VERSION 5.7 ;
  NOWIREEXTENSIONATPIN ON ;
  DIVIDERCHAR "/" ;
  BUSBITCHARS "[]" ;
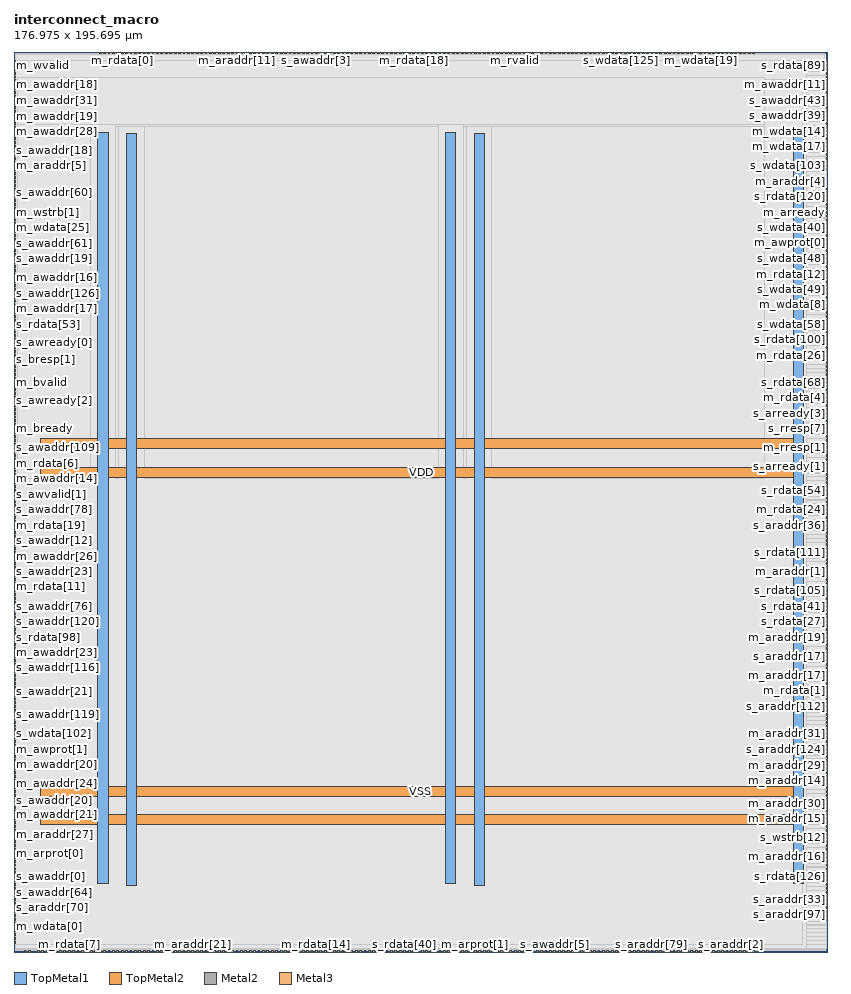
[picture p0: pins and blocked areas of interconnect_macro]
MACRO interconnect_macro
  CLASS BLOCK ;
  FOREIGN interconnect_macro ;
  ORIGIN 0.000 0.000 ;
  SIZE 176.975 BY 195.695 ;
  PIN VDD
    DIRECTION INOUT ;
    USE POWER ;
    PORT
      LAYER TopMetal1 ;
        RECT 18.260 14.900 20.460 178.290 ;
    END
    PORT
      LAYER TopMetal1 ;
        RECT 93.860 14.900 96.060 178.290 ;
    END
    PORT
      LAYER TopMetal1 ;
        RECT 169.460 14.900 171.660 178.290 ;
    END
    PORT
      LAYER TopMetal2 ;
        RECT 5.760 27.620 171.660 29.820 ;
    END
    PORT
      LAYER TopMetal2 ;
        RECT 5.760 103.220 171.660 105.420 ;
    END
  END VDD
  PIN VSS
    DIRECTION INOUT ;
    USE GROUND ;
    PORT
      LAYER TopMetal1 ;
        RECT 24.460 14.490 26.660 177.880 ;
    END
    PORT
      LAYER TopMetal1 ;
        RECT 100.060 14.490 102.260 177.880 ;
    END
    PORT
      LAYER TopMetal2 ;
        RECT 5.760 33.820 170.880 36.020 ;
    END
    PORT
      LAYER TopMetal2 ;
        RECT 5.760 109.420 170.880 111.620 ;
    END
  END VSS
  PIN clk_i
    DIRECTION INPUT ;
    USE SIGNAL ;
    PORT
      LAYER Metal2 ;
        RECT 2.200 0.000 2.600 0.400 ;
    END
  END clk_i
  PIN m_araddr[0]
    DIRECTION INPUT ;
    USE SIGNAL ;
    ANTENNAGATEAREA 0.109200 ;
    PORT
      LAYER Metal2 ;
        RECT 5.080 0.000 5.480 0.400 ;
    END
  END m_araddr[0]
  PIN m_araddr[10]
    DIRECTION INPUT ;
    USE SIGNAL ;
    ANTENNAGATEAREA 0.109200 ;
    PORT
      LAYER Metal2 ;
        RECT 18.520 195.295 18.920 195.695 ;
    END
  END m_araddr[10]
  PIN m_araddr[11]
    DIRECTION INPUT ;
    USE SIGNAL ;
    ANTENNAGATEAREA 0.109200 ;
    PORT
      LAYER Metal2 ;
        RECT 48.280 195.295 48.680 195.695 ;
    END
  END m_araddr[11]
  PIN m_araddr[12]
    DIRECTION INPUT ;
    USE SIGNAL ;
    ANTENNAGATEAREA 0.180700 ;
    PORT
      LAYER Metal3 ;
        RECT 176.575 6.940 176.975 7.340 ;
    END
  END m_araddr[12]
  PIN m_araddr[13]
    DIRECTION INPUT ;
    USE SIGNAL ;
    ANTENNAGATEAREA 0.180700 ;
    PORT
      LAYER Metal3 ;
        RECT 176.575 12.820 176.975 13.220 ;
    END
  END m_araddr[13]
  PIN m_araddr[14]
    DIRECTION INPUT ;
    USE SIGNAL ;
    ANTENNAGATEAREA 0.180700 ;
    PORT
      LAYER Metal3 ;
        RECT 176.575 37.180 176.975 37.580 ;
    END
  END m_araddr[14]
  PIN m_araddr[15]
    DIRECTION INPUT ;
    USE SIGNAL ;
    ANTENNAGATEAREA 0.180700 ;
    PORT
      LAYER Metal3 ;
        RECT 176.575 28.780 176.975 29.180 ;
    END
  END m_araddr[15]
  PIN m_araddr[16]
    DIRECTION INPUT ;
    USE SIGNAL ;
    ANTENNAGATEAREA 0.180700 ;
    PORT
      LAYER Metal3 ;
        RECT 176.575 22.060 176.975 22.460 ;
    END
  END m_araddr[16]
  PIN m_araddr[17]
    DIRECTION INPUT ;
    USE SIGNAL ;
    ANTENNAGATEAREA 0.180700 ;
    PORT
      LAYER Metal3 ;
        RECT 176.575 61.540 176.975 61.940 ;
    END
  END m_araddr[17]
  PIN m_araddr[18]
    DIRECTION INPUT ;
    USE SIGNAL ;
    ANTENNAGATEAREA 0.180700 ;
    PORT
      LAYER Metal3 ;
        RECT 176.575 18.700 176.975 19.100 ;
    END
  END m_araddr[18]
  PIN m_araddr[19]
    DIRECTION INPUT ;
    USE SIGNAL ;
    ANTENNAGATEAREA 0.180700 ;
    PORT
      LAYER Metal3 ;
        RECT 176.575 68.260 176.975 68.660 ;
    END
  END m_araddr[19]
  PIN m_araddr[1]
    DIRECTION INPUT ;
    USE SIGNAL ;
    ANTENNAGATEAREA 0.109200 ;
    PORT
      LAYER Metal3 ;
        RECT 176.575 82.540 176.975 82.940 ;
    END
  END m_araddr[1]
  PIN m_araddr[20]
    DIRECTION INPUT ;
    USE SIGNAL ;
    ANTENNAGATEAREA 0.180700 ;
    PORT
      LAYER Metal2 ;
        RECT 61.720 0.000 62.120 0.400 ;
    END
  END m_araddr[20]
  PIN m_araddr[21]
    DIRECTION INPUT ;
    USE SIGNAL ;
    ANTENNAGATEAREA 0.180700 ;
    PORT
      LAYER Metal2 ;
        RECT 38.680 0.000 39.080 0.400 ;
    END
  END m_araddr[21]
  PIN m_araddr[22]
    DIRECTION INPUT ;
    USE SIGNAL ;
    ANTENNAGATEAREA 0.180700 ;
    PORT
      LAYER Metal2 ;
        RECT 63.640 0.000 64.040 0.400 ;
    END
  END m_araddr[22]
  PIN m_araddr[23]
    DIRECTION INPUT ;
    USE SIGNAL ;
    ANTENNAGATEAREA 0.180700 ;
    PORT
      LAYER Metal2 ;
        RECT 36.760 0.000 37.160 0.400 ;
    END
  END m_araddr[23]
  PIN m_araddr[24]
    DIRECTION INPUT ;
    USE SIGNAL ;
    ANTENNAGATEAREA 0.180700 ;
    PORT
      LAYER Metal2 ;
        RECT 40.600 0.000 41.000 0.400 ;
    END
  END m_araddr[24]
  PIN m_araddr[25]
    DIRECTION INPUT ;
    USE SIGNAL ;
    ANTENNAGATEAREA 0.180700 ;
    PORT
      LAYER Metal2 ;
        RECT 49.240 0.000 49.640 0.400 ;
    END
  END m_araddr[25]
  PIN m_araddr[26]
    DIRECTION INPUT ;
    USE SIGNAL ;
    ANTENNAGATEAREA 0.180700 ;
    PORT
      LAYER Metal2 ;
        RECT 52.120 0.000 52.520 0.400 ;
    END
  END m_araddr[26]
  PIN m_araddr[27]
    DIRECTION INPUT ;
    USE SIGNAL ;
    ANTENNAGATEAREA 0.180700 ;
    PORT
      LAYER Metal3 ;
        RECT 0.000 25.420 0.400 25.820 ;
    END
  END m_araddr[27]
  PIN m_araddr[28]
    DIRECTION INPUT ;
    USE SIGNAL ;
    ANTENNAGATEAREA 0.180700 ;
    PORT
      LAYER Metal3 ;
        RECT 176.575 22.900 176.975 23.300 ;
    END
  END m_araddr[28]
  PIN m_araddr[29]
    DIRECTION INPUT ;
    USE SIGNAL ;
    ANTENNAGATEAREA 0.180700 ;
    PORT
      LAYER Metal3 ;
        RECT 176.575 38.860 176.975 39.260 ;
    END
  END m_araddr[29]
  PIN m_araddr[2]
    DIRECTION INPUT ;
    USE SIGNAL ;
    ANTENNAGATEAREA 0.109200 ;
    PORT
      LAYER Metal2 ;
        RECT 158.680 0.000 159.080 0.400 ;
    END
  END m_araddr[2]
  PIN m_araddr[30]
    DIRECTION INPUT ;
    USE SIGNAL ;
    ANTENNAGATEAREA 0.109200 ;
    PORT
      LAYER Metal3 ;
        RECT 176.575 30.460 176.975 30.860 ;
    END
  END m_araddr[30]
  PIN m_araddr[31]
    DIRECTION INPUT ;
    USE SIGNAL ;
    ANTENNAGATEAREA 0.180700 ;
    PORT
      LAYER Metal3 ;
        RECT 176.575 47.260 176.975 47.660 ;
    END
  END m_araddr[31]
  PIN m_araddr[3]
    DIRECTION INPUT ;
    USE SIGNAL ;
    ANTENNAGATEAREA 0.109200 ;
    PORT
      LAYER Metal2 ;
        RECT 160.600 195.295 161.000 195.695 ;
    END
  END m_araddr[3]
  PIN m_araddr[4]
    DIRECTION INPUT ;
    USE SIGNAL ;
    ANTENNAGATEAREA 0.109200 ;
    PORT
      LAYER Metal3 ;
        RECT 176.575 165.700 176.975 166.100 ;
    END
  END m_araddr[4]
  PIN m_araddr[5]
    DIRECTION INPUT ;
    USE SIGNAL ;
    ANTENNAGATEAREA 0.109200 ;
    PORT
      LAYER Metal3 ;
        RECT 0.000 170.740 0.400 171.140 ;
    END
  END m_araddr[5]
  PIN m_araddr[6]
    DIRECTION INPUT ;
    USE SIGNAL ;
    ANTENNAGATEAREA 0.109200 ;
    PORT
      LAYER Metal3 ;
        RECT 0.000 11.980 0.400 12.380 ;
    END
  END m_araddr[6]
  PIN m_araddr[7]
    DIRECTION INPUT ;
    USE SIGNAL ;
    ANTENNAGATEAREA 0.109200 ;
    PORT
      LAYER Metal2 ;
        RECT 143.320 0.000 143.720 0.400 ;
    END
  END m_araddr[7]
  PIN m_araddr[8]
    DIRECTION INPUT ;
    USE SIGNAL ;
    ANTENNAGATEAREA 0.109200 ;
    PORT
      LAYER Metal2 ;
        RECT 63.640 195.295 64.040 195.695 ;
    END
  END m_araddr[8]
  PIN m_araddr[9]
    DIRECTION INPUT ;
    USE SIGNAL ;
    ANTENNAGATEAREA 0.109200 ;
    PORT
      LAYER Metal2 ;
        RECT 59.800 195.295 60.200 195.695 ;
    END
  END m_araddr[9]
  PIN m_arprot[0]
    DIRECTION INPUT ;
    USE SIGNAL ;
    ANTENNAGATEAREA 0.109200 ;
    PORT
      LAYER Metal3 ;
        RECT 0.000 21.220 0.400 21.620 ;
    END
  END m_arprot[0]
  PIN m_arprot[1]
    DIRECTION INPUT ;
    USE SIGNAL ;
    ANTENNAGATEAREA 0.109200 ;
    PORT
      LAYER Metal2 ;
        RECT 100.120 0.000 100.520 0.400 ;
    END
  END m_arprot[1]
  PIN m_arprot[2]
    DIRECTION INPUT ;
    USE SIGNAL ;
    ANTENNAGATEAREA 0.109200 ;
    PORT
      LAYER Metal2 ;
        RECT 140.440 195.295 140.840 195.695 ;
    END
  END m_arprot[2]
  PIN m_arready
    DIRECTION OUTPUT ;
    USE SIGNAL ;
    ANTENNADIFFAREA 0.708600 ;
    PORT
      LAYER Metal3 ;
        RECT 176.575 158.980 176.975 159.380 ;
    END
  END m_arready
  PIN m_arvalid
    DIRECTION INPUT ;
    USE SIGNAL ;
    ANTENNAGATEAREA 0.180700 ;
    PORT
      LAYER Metal3 ;
        RECT 176.575 48.100 176.975 48.500 ;
    END
  END m_arvalid
  PIN m_awaddr[0]
    DIRECTION INPUT ;
    USE SIGNAL ;
    ANTENNAGATEAREA 0.109200 ;
    PORT
      LAYER Metal3 ;
        RECT 0.000 3.580 0.400 3.980 ;
    END
  END m_awaddr[0]
  PIN m_awaddr[10]
    DIRECTION INPUT ;
    USE SIGNAL ;
    ANTENNAGATEAREA 0.109200 ;
    PORT
      LAYER Metal2 ;
        RECT 57.880 195.295 58.280 195.695 ;
    END
  END m_awaddr[10]
  PIN m_awaddr[11]
    DIRECTION INPUT ;
    USE SIGNAL ;
    ANTENNAGATEAREA 0.109200 ;
    PORT
      LAYER Metal3 ;
        RECT 176.575 190.060 176.975 190.460 ;
    END
  END m_awaddr[11]
  PIN m_awaddr[12]
    DIRECTION INPUT ;
    USE SIGNAL ;
    ANTENNAGATEAREA 0.180700 ;
    PORT
      LAYER Metal3 ;
        RECT 0.000 90.100 0.400 90.500 ;
    END
  END m_awaddr[12]
  PIN m_awaddr[13]
    DIRECTION INPUT ;
    USE SIGNAL ;
    ANTENNAGATEAREA 0.180700 ;
    PORT
      LAYER Metal3 ;
        RECT 0.000 193.420 0.400 193.820 ;
    END
  END m_awaddr[13]
  PIN m_awaddr[14]
    DIRECTION INPUT ;
    USE SIGNAL ;
    ANTENNAGATEAREA 0.180700 ;
    PORT
      LAYER Metal3 ;
        RECT 0.000 102.700 0.400 103.100 ;
    END
  END m_awaddr[14]
  PIN m_awaddr[15]
    DIRECTION INPUT ;
    USE SIGNAL ;
    ANTENNAGATEAREA 0.180700 ;
    PORT
      LAYER Metal3 ;
        RECT 0.000 103.540 0.400 103.940 ;
    END
  END m_awaddr[15]
  PIN m_awaddr[16]
    DIRECTION INPUT ;
    USE SIGNAL ;
    ANTENNAGATEAREA 0.180700 ;
    PORT
      LAYER Metal3 ;
        RECT 0.000 146.380 0.400 146.780 ;
    END
  END m_awaddr[16]
  PIN m_awaddr[17]
    DIRECTION INPUT ;
    USE SIGNAL ;
    ANTENNAGATEAREA 0.180700 ;
    PORT
      LAYER Metal3 ;
        RECT 0.000 141.340 0.400 141.740 ;
    END
  END m_awaddr[17]
  PIN m_awaddr[18]
    DIRECTION INPUT ;
    USE SIGNAL ;
    ANTENNAGATEAREA 0.180700 ;
    PORT
      LAYER Metal3 ;
        RECT 0.000 188.380 0.400 188.780 ;
    END
  END m_awaddr[18]
  PIN m_awaddr[19]
    DIRECTION INPUT ;
    USE SIGNAL ;
    ANTENNAGATEAREA 0.180700 ;
    PORT
      LAYER Metal3 ;
        RECT 0.000 179.980 0.400 180.380 ;
    END
  END m_awaddr[19]
  PIN m_awaddr[1]
    DIRECTION INPUT ;
    USE SIGNAL ;
    ANTENNAGATEAREA 0.109200 ;
    PORT
      LAYER Metal2 ;
        RECT 132.760 0.000 133.160 0.400 ;
    END
  END m_awaddr[1]
  PIN m_awaddr[20]
    DIRECTION INPUT ;
    USE SIGNAL ;
    ANTENNAGATEAREA 0.180700 ;
    PORT
      LAYER Metal3 ;
        RECT 0.000 40.540 0.400 40.940 ;
    END
  END m_awaddr[20]
  PIN m_awaddr[21]
    DIRECTION INPUT ;
    USE SIGNAL ;
    ANTENNAGATEAREA 0.180700 ;
    PORT
      LAYER Metal3 ;
        RECT 0.000 29.620 0.400 30.020 ;
    END
  END m_awaddr[21]
  PIN m_awaddr[22]
    DIRECTION INPUT ;
    USE SIGNAL ;
    ANTENNAGATEAREA 0.180700 ;
    PORT
      LAYER Metal3 ;
        RECT 0.000 80.020 0.400 80.420 ;
    END
  END m_awaddr[22]
  PIN m_awaddr[23]
    DIRECTION INPUT ;
    USE SIGNAL ;
    ANTENNAGATEAREA 0.180700 ;
    PORT
      LAYER Metal3 ;
        RECT 0.000 64.900 0.400 65.300 ;
    END
  END m_awaddr[23]
  PIN m_awaddr[24]
    DIRECTION INPUT ;
    USE SIGNAL ;
    ANTENNAGATEAREA 0.180700 ;
    PORT
      LAYER Metal3 ;
        RECT 0.000 36.340 0.400 36.740 ;
    END
  END m_awaddr[24]
  PIN m_awaddr[25]
    DIRECTION INPUT ;
    USE SIGNAL ;
    ANTENNAGATEAREA 0.180700 ;
    PORT
      LAYER Metal3 ;
        RECT 0.000 84.220 0.400 84.620 ;
    END
  END m_awaddr[25]
  PIN m_awaddr[26]
    DIRECTION INPUT ;
    USE SIGNAL ;
    ANTENNAGATEAREA 0.180700 ;
    PORT
      LAYER Metal3 ;
        RECT 0.000 85.900 0.400 86.300 ;
    END
  END m_awaddr[26]
  PIN m_awaddr[27]
    DIRECTION INPUT ;
    USE SIGNAL ;
    ANTENNAGATEAREA 0.180700 ;
    PORT
      LAYER Metal3 ;
        RECT 0.000 75.820 0.400 76.220 ;
    END
  END m_awaddr[27]
  PIN m_awaddr[28]
    DIRECTION INPUT ;
    USE SIGNAL ;
    ANTENNAGATEAREA 0.180700 ;
    PORT
      LAYER Metal3 ;
        RECT 0.000 178.300 0.400 178.700 ;
    END
  END m_awaddr[28]
  PIN m_awaddr[29]
    DIRECTION INPUT ;
    USE SIGNAL ;
    ANTENNAGATEAREA 0.180700 ;
    PORT
      LAYER Metal3 ;
        RECT 0.000 181.660 0.400 182.060 ;
    END
  END m_awaddr[29]
  PIN m_awaddr[2]
    DIRECTION INPUT ;
    USE SIGNAL ;
    ANTENNAGATEAREA 0.109200 ;
    PORT
      LAYER Metal2 ;
        RECT 62.680 0.000 63.080 0.400 ;
    END
  END m_awaddr[2]
  PIN m_awaddr[30]
    DIRECTION INPUT ;
    USE SIGNAL ;
    ANTENNAGATEAREA 0.180700 ;
    PORT
      LAYER Metal3 ;
        RECT 0.000 182.500 0.400 182.900 ;
    END
  END m_awaddr[30]
  PIN m_awaddr[31]
    DIRECTION INPUT ;
    USE SIGNAL ;
    ANTENNAGATEAREA 0.180700 ;
    PORT
      LAYER Metal3 ;
        RECT 0.000 185.020 0.400 185.420 ;
    END
  END m_awaddr[31]
  PIN m_awaddr[3]
    DIRECTION INPUT ;
    USE SIGNAL ;
    ANTENNAGATEAREA 0.109200 ;
    PORT
      LAYER Metal2 ;
        RECT 61.720 195.295 62.120 195.695 ;
    END
  END m_awaddr[3]
  PIN m_awaddr[4]
    DIRECTION INPUT ;
    USE SIGNAL ;
    ANTENNAGATEAREA 0.109200 ;
    PORT
      LAYER Metal3 ;
        RECT 176.575 182.500 176.975 182.900 ;
    END
  END m_awaddr[4]
  PIN m_awaddr[5]
    DIRECTION INPUT ;
    USE SIGNAL ;
    ANTENNAGATEAREA 0.109200 ;
    PORT
      LAYER Metal2 ;
        RECT 140.440 0.000 140.840 0.400 ;
    END
  END m_awaddr[5]
  PIN m_awaddr[6]
    DIRECTION INPUT ;
    USE SIGNAL ;
    ANTENNAGATEAREA 0.109200 ;
    PORT
      LAYER Metal2 ;
        RECT 157.720 0.000 158.120 0.400 ;
    END
  END m_awaddr[6]
  PIN m_awaddr[7]
    DIRECTION INPUT ;
    USE SIGNAL ;
    ANTENNAGATEAREA 0.109200 ;
    PORT
      LAYER Metal3 ;
        RECT 176.575 180.820 176.975 181.220 ;
    END
  END m_awaddr[7]
  PIN m_awaddr[8]
    DIRECTION INPUT ;
    USE SIGNAL ;
    ANTENNAGATEAREA 0.109200 ;
    PORT
      LAYER Metal3 ;
        RECT 0.000 19.540 0.400 19.940 ;
    END
  END m_awaddr[8]
  PIN m_awaddr[9]
    DIRECTION INPUT ;
    USE SIGNAL ;
    ANTENNAGATEAREA 0.109200 ;
    PORT
      LAYER Metal2 ;
        RECT 103.000 195.295 103.400 195.695 ;
    END
  END m_awaddr[9]
  PIN m_awprot[0]
    DIRECTION INPUT ;
    USE SIGNAL ;
    ANTENNAGATEAREA 0.109200 ;
    PORT
      LAYER Metal3 ;
        RECT 176.575 155.620 176.975 156.020 ;
    END
  END m_awprot[0]
  PIN m_awprot[1]
    DIRECTION INPUT ;
    USE SIGNAL ;
    ANTENNAGATEAREA 0.109200 ;
    PORT
      LAYER Metal3 ;
        RECT 0.000 43.900 0.400 44.300 ;
    END
  END m_awprot[1]
  PIN m_awprot[2]
    DIRECTION INPUT ;
    USE SIGNAL ;
    ANTENNAGATEAREA 0.109200 ;
    PORT
      LAYER Metal2 ;
        RECT 43.480 0.000 43.880 0.400 ;
    END
  END m_awprot[2]
  PIN m_awready
    DIRECTION OUTPUT ;
    USE SIGNAL ;
    ANTENNADIFFAREA 0.708600 ;
    PORT
      LAYER Metal3 ;
        RECT 0.000 137.140 0.400 137.540 ;
    END
  END m_awready
  PIN m_awvalid
    DIRECTION INPUT ;
    USE SIGNAL ;
    ANTENNAGATEAREA 0.180700 ;
    PORT
      LAYER Metal3 ;
        RECT 0.000 114.460 0.400 114.860 ;
    END
  END m_awvalid
  PIN m_bready
    DIRECTION INPUT ;
    USE SIGNAL ;
    ANTENNAGATEAREA 0.180700 ;
    PORT
      LAYER Metal3 ;
        RECT 0.000 113.620 0.400 114.020 ;
    END
  END m_bready
  PIN m_bresp[0]
    DIRECTION OUTPUT ;
    USE SIGNAL ;
    ANTENNADIFFAREA 0.708600 ;
    PORT
      LAYER Metal3 ;
        RECT 0.000 122.020 0.400 122.420 ;
    END
  END m_bresp[0]
  PIN m_bresp[1]
    DIRECTION OUTPUT ;
    USE SIGNAL ;
    ANTENNADIFFAREA 0.708600 ;
    PORT
      LAYER Metal3 ;
        RECT 0.000 135.460 0.400 135.860 ;
    END
  END m_bresp[1]
  PIN m_bvalid
    DIRECTION OUTPUT ;
    USE SIGNAL ;
    ANTENNADIFFAREA 0.708600 ;
    PORT
      LAYER Metal3 ;
        RECT 0.000 123.700 0.400 124.100 ;
    END
  END m_bvalid
  PIN m_rdata[0]
    DIRECTION OUTPUT ;
    USE SIGNAL ;
    ANTENNADIFFAREA 0.708600 ;
    PORT
      LAYER Metal2 ;
        RECT 23.320 195.295 23.720 195.695 ;
    END
  END m_rdata[0]
  PIN m_rdata[10]
    DIRECTION OUTPUT ;
    USE SIGNAL ;
    ANTENNADIFFAREA 0.708600 ;
    PORT
      LAYER Metal2 ;
        RECT 35.800 0.000 36.200 0.400 ;
    END
  END m_rdata[10]
  PIN m_rdata[11]
    DIRECTION OUTPUT ;
    USE SIGNAL ;
    ANTENNADIFFAREA 0.708600 ;
    PORT
      LAYER Metal3 ;
        RECT 0.000 79.180 0.400 79.580 ;
    END
  END m_rdata[11]
  PIN m_rdata[12]
    DIRECTION OUTPUT ;
    USE SIGNAL ;
    ANTENNADIFFAREA 0.708600 ;
    PORT
      LAYER Metal3 ;
        RECT 176.575 145.540 176.975 145.940 ;
    END
  END m_rdata[12]
  PIN m_rdata[13]
    DIRECTION OUTPUT ;
    USE SIGNAL ;
    ANTENNADIFFAREA 0.708600 ;
    PORT
      LAYER Metal3 ;
        RECT 0.000 125.380 0.400 125.780 ;
    END
  END m_rdata[13]
  PIN m_rdata[14]
    DIRECTION OUTPUT ;
    USE SIGNAL ;
    ANTENNADIFFAREA 0.708600 ;
    PORT
      LAYER Metal2 ;
        RECT 65.560 0.000 65.960 0.400 ;
    END
  END m_rdata[14]
  PIN m_rdata[15]
    DIRECTION OUTPUT ;
    USE SIGNAL ;
    ANTENNADIFFAREA 0.708600 ;
    PORT
      LAYER Metal3 ;
        RECT 176.575 86.740 176.975 87.140 ;
    END
  END m_rdata[15]
  PIN m_rdata[16]
    DIRECTION OUTPUT ;
    USE SIGNAL ;
    ANTENNADIFFAREA 0.708600 ;
    PORT
      LAYER Metal2 ;
        RECT 106.840 0.000 107.240 0.400 ;
    END
  END m_rdata[16]
  PIN m_rdata[17]
    DIRECTION OUTPUT ;
    USE SIGNAL ;
    ANTENNADIFFAREA 0.708600 ;
    PORT
      LAYER Metal2 ;
        RECT 103.960 0.000 104.360 0.400 ;
    END
  END m_rdata[17]
  PIN m_rdata[18]
    DIRECTION OUTPUT ;
    USE SIGNAL ;
    ANTENNADIFFAREA 0.708600 ;
    PORT
      LAYER Metal2 ;
        RECT 86.680 195.295 87.080 195.695 ;
    END
  END m_rdata[18]
  PIN m_rdata[19]
    DIRECTION OUTPUT ;
    USE SIGNAL ;
    ANTENNADIFFAREA 0.708600 ;
    PORT
      LAYER Metal3 ;
        RECT 0.000 92.620 0.400 93.020 ;
    END
  END m_rdata[19]
  PIN m_rdata[1]
    DIRECTION OUTPUT ;
    USE SIGNAL ;
    ANTENNADIFFAREA 0.708600 ;
    PORT
      LAYER Metal3 ;
        RECT 176.575 58.180 176.975 58.580 ;
    END
  END m_rdata[1]
  PIN m_rdata[20]
    DIRECTION OUTPUT ;
    USE SIGNAL ;
    ANTENNADIFFAREA 0.708600 ;
    PORT
      LAYER Metal2 ;
        RECT 151.960 195.295 152.360 195.695 ;
    END
  END m_rdata[20]
  PIN m_rdata[21]
    DIRECTION OUTPUT ;
    USE SIGNAL ;
    ANTENNADIFFAREA 0.708600 ;
    PORT
      LAYER Metal2 ;
        RECT 27.160 195.295 27.560 195.695 ;
    END
  END m_rdata[21]
  PIN m_rdata[22]
    DIRECTION OUTPUT ;
    USE SIGNAL ;
    ANTENNADIFFAREA 0.708600 ;
    PORT
      LAYER Metal3 ;
        RECT 176.575 95.140 176.975 95.540 ;
    END
  END m_rdata[22]
  PIN m_rdata[23]
    DIRECTION OUTPUT ;
    USE SIGNAL ;
    ANTENNADIFFAREA 0.708600 ;
    PORT
      LAYER Metal2 ;
        RECT 130.840 195.295 131.240 195.695 ;
    END
  END m_rdata[23]
  PIN m_rdata[24]
    DIRECTION OUTPUT ;
    USE SIGNAL ;
    ANTENNADIFFAREA 0.708600 ;
    PORT
      LAYER Metal3 ;
        RECT 176.575 95.980 176.975 96.380 ;
    END
  END m_rdata[24]
  PIN m_rdata[25]
    DIRECTION OUTPUT ;
    USE SIGNAL ;
    ANTENNADIFFAREA 0.708600 ;
    PORT
      LAYER Metal3 ;
        RECT 176.575 151.420 176.975 151.820 ;
    END
  END m_rdata[25]
  PIN m_rdata[26]
    DIRECTION OUTPUT ;
    USE SIGNAL ;
    ANTENNADIFFAREA 0.708600 ;
    PORT
      LAYER Metal3 ;
        RECT 176.575 129.580 176.975 129.980 ;
    END
  END m_rdata[26]
  PIN m_rdata[27]
    DIRECTION OUTPUT ;
    USE SIGNAL ;
    ANTENNADIFFAREA 0.708600 ;
    PORT
      LAYER Metal3 ;
        RECT 176.575 17.860 176.975 18.260 ;
    END
  END m_rdata[27]
  PIN m_rdata[28]
    DIRECTION OUTPUT ;
    USE SIGNAL ;
    ANTENNADIFFAREA 0.708600 ;
    PORT
      LAYER Metal3 ;
        RECT 176.575 81.700 176.975 82.100 ;
    END
  END m_rdata[28]
  PIN m_rdata[29]
    DIRECTION OUTPUT ;
    USE SIGNAL ;
    ANTENNADIFFAREA 0.708600 ;
    PORT
      LAYER Metal3 ;
        RECT 176.575 101.020 176.975 101.420 ;
    END
  END m_rdata[29]
  PIN m_rdata[2]
    DIRECTION OUTPUT ;
    USE SIGNAL ;
    ANTENNADIFFAREA 0.708600 ;
    PORT
      LAYER Metal3 ;
        RECT 0.000 69.940 0.400 70.340 ;
    END
  END m_rdata[2]
  PIN m_rdata[30]
    DIRECTION OUTPUT ;
    USE SIGNAL ;
    ANTENNADIFFAREA 0.708600 ;
    PORT
      LAYER Metal3 ;
        RECT 176.575 23.740 176.975 24.140 ;
    END
  END m_rdata[30]
  PIN m_rdata[31]
    DIRECTION OUTPUT ;
    USE SIGNAL ;
    ANTENNADIFFAREA 0.708600 ;
    PORT
      LAYER Metal3 ;
        RECT 176.575 108.580 176.975 108.980 ;
    END
  END m_rdata[31]
  PIN m_rdata[3]
    DIRECTION OUTPUT ;
    USE SIGNAL ;
    ANTENNADIFFAREA 0.708600 ;
    PORT
      LAYER Metal2 ;
        RECT 114.520 0.000 114.920 0.400 ;
    END
  END m_rdata[3]
  PIN m_rdata[4]
    DIRECTION OUTPUT ;
    USE SIGNAL ;
    ANTENNADIFFAREA 0.708600 ;
    PORT
      LAYER Metal3 ;
        RECT 176.575 120.340 176.975 120.740 ;
    END
  END m_rdata[4]
  PIN m_rdata[5]
    DIRECTION OUTPUT ;
    USE SIGNAL ;
    ANTENNADIFFAREA 0.708600 ;
    PORT
      LAYER Metal2 ;
        RECT 159.640 195.295 160.040 195.695 ;
    END
  END m_rdata[5]
  PIN m_rdata[6]
    DIRECTION OUTPUT ;
    USE SIGNAL ;
    ANTENNADIFFAREA 0.708600 ;
    PORT
      LAYER Metal3 ;
        RECT 0.000 106.060 0.400 106.460 ;
    END
  END m_rdata[6]
  PIN m_rdata[7]
    DIRECTION OUTPUT ;
    USE SIGNAL ;
    ANTENNADIFFAREA 0.708600 ;
    PORT
      LAYER Metal2 ;
        RECT 11.800 0.000 12.200 0.400 ;
    END
  END m_rdata[7]
  PIN m_rdata[8]
    DIRECTION OUTPUT ;
    USE SIGNAL ;
    ANTENNADIFFAREA 0.708600 ;
    PORT
      LAYER Metal2 ;
        RECT 91.480 0.000 91.880 0.400 ;
    END
  END m_rdata[8]
  PIN m_rdata[9]
    DIRECTION OUTPUT ;
    USE SIGNAL ;
    ANTENNADIFFAREA 0.708600 ;
    PORT
      LAYER Metal3 ;
        RECT 176.575 77.500 176.975 77.900 ;
    END
  END m_rdata[9]
  PIN m_rready
    DIRECTION INPUT ;
    USE SIGNAL ;
    ANTENNAGATEAREA 0.180700 ;
    PORT
      LAYER Metal3 ;
        RECT 176.575 56.500 176.975 56.900 ;
    END
  END m_rready
  PIN m_rresp[0]
    DIRECTION OUTPUT ;
    USE SIGNAL ;
    ANTENNADIFFAREA 0.708600 ;
    PORT
      LAYER Metal3 ;
        RECT 176.575 104.380 176.975 104.780 ;
    END
  END m_rresp[0]
  PIN m_rresp[1]
    DIRECTION OUTPUT ;
    USE SIGNAL ;
    ANTENNADIFFAREA 0.708600 ;
    PORT
      LAYER Metal3 ;
        RECT 176.575 109.420 176.975 109.820 ;
    END
  END m_rresp[1]
  PIN m_rvalid
    DIRECTION OUTPUT ;
    USE SIGNAL ;
    ANTENNADIFFAREA 0.708600 ;
    PORT
      LAYER Metal2 ;
        RECT 108.760 195.295 109.160 195.695 ;
    END
  END m_rvalid
  PIN m_wdata[0]
    DIRECTION INPUT ;
    USE SIGNAL ;
    ANTENNAGATEAREA 0.109200 ;
    PORT
      LAYER Metal3 ;
        RECT 0.000 6.940 0.400 7.340 ;
    END
  END m_wdata[0]
  PIN m_wdata[10]
    DIRECTION INPUT ;
    USE SIGNAL ;
    ANTENNAGATEAREA 0.109200 ;
    PORT
      LAYER Metal2 ;
        RECT 114.520 195.295 114.920 195.695 ;
    END
  END m_wdata[10]
  PIN m_wdata[11]
    DIRECTION INPUT ;
    USE SIGNAL ;
    ANTENNAGATEAREA 0.109200 ;
    PORT
      LAYER Metal3 ;
        RECT 176.575 115.300 176.975 115.700 ;
    END
  END m_wdata[11]
  PIN m_wdata[12]
    DIRECTION INPUT ;
    USE SIGNAL ;
    ANTENNAGATEAREA 0.109200 ;
    PORT
      LAYER Metal3 ;
        RECT 0.000 166.540 0.400 166.940 ;
    END
  END m_wdata[12]
  PIN m_wdata[13]
    DIRECTION INPUT ;
    USE SIGNAL ;
    ANTENNAGATEAREA 0.109200 ;
    PORT
      LAYER Metal2 ;
        RECT 8.920 0.000 9.320 0.400 ;
    END
  END m_wdata[13]
  PIN m_wdata[14]
    DIRECTION INPUT ;
    USE SIGNAL ;
    ANTENNAGATEAREA 0.109200 ;
    PORT
      LAYER Metal3 ;
        RECT 176.575 178.300 176.975 178.700 ;
    END
  END m_wdata[14]
  PIN m_wdata[15]
    DIRECTION INPUT ;
    USE SIGNAL ;
    ANTENNAGATEAREA 0.109200 ;
    PORT
      LAYER Metal2 ;
        RECT 49.240 195.295 49.640 195.695 ;
    END
  END m_wdata[15]
  PIN m_wdata[16]
    DIRECTION INPUT ;
    USE SIGNAL ;
    ANTENNAGATEAREA 0.109200 ;
    PORT
      LAYER Metal3 ;
        RECT 176.575 177.460 176.975 177.860 ;
    END
  END m_wdata[16]
  PIN m_wdata[17]
    DIRECTION INPUT ;
    USE SIGNAL ;
    ANTENNAGATEAREA 0.109200 ;
    PORT
      LAYER Metal3 ;
        RECT 176.575 174.940 176.975 175.340 ;
    END
  END m_wdata[17]
  PIN m_wdata[18]
    DIRECTION INPUT ;
    USE SIGNAL ;
    ANTENNAGATEAREA 0.109200 ;
    PORT
      LAYER Metal2 ;
        RECT 128.920 0.000 129.320 0.400 ;
    END
  END m_wdata[18]
  PIN m_wdata[19]
    DIRECTION INPUT ;
    USE SIGNAL ;
    ANTENNAGATEAREA 0.109200 ;
    PORT
      LAYER Metal2 ;
        RECT 149.080 195.295 149.480 195.695 ;
    END
  END m_wdata[19]
  PIN m_wdata[1]
    DIRECTION INPUT ;
    USE SIGNAL ;
    ANTENNAGATEAREA 0.109200 ;
    PORT
      LAYER Metal2 ;
        RECT 50.200 195.295 50.600 195.695 ;
    END
  END m_wdata[1]
  PIN m_wdata[20]
    DIRECTION INPUT ;
    USE SIGNAL ;
    ANTENNAGATEAREA 0.109200 ;
    PORT
      LAYER Metal3 ;
        RECT 0.000 185.860 0.400 186.260 ;
    END
  END m_wdata[20]
  PIN m_wdata[21]
    DIRECTION INPUT ;
    USE SIGNAL ;
    ANTENNAGATEAREA 0.109200 ;
    PORT
      LAYER Metal2 ;
        RECT 156.760 0.000 157.160 0.400 ;
    END
  END m_wdata[21]
  PIN m_wdata[22]
    DIRECTION INPUT ;
    USE SIGNAL ;
    ANTENNAGATEAREA 0.109200 ;
    PORT
      LAYER Metal3 ;
        RECT 0.000 5.260 0.400 5.660 ;
    END
  END m_wdata[22]
  PIN m_wdata[23]
    DIRECTION INPUT ;
    USE SIGNAL ;
    ANTENNAGATEAREA 0.109200 ;
    PORT
      LAYER Metal2 ;
        RECT 98.200 195.295 98.600 195.695 ;
    END
  END m_wdata[23]
  PIN m_wdata[24]
    DIRECTION INPUT ;
    USE SIGNAL ;
    ANTENNAGATEAREA 0.109200 ;
    PORT
      LAYER Metal2 ;
        RECT 93.400 195.295 93.800 195.695 ;
    END
  END m_wdata[24]
  PIN m_wdata[25]
    DIRECTION INPUT ;
    USE SIGNAL ;
    ANTENNAGATEAREA 0.109200 ;
    PORT
      LAYER Metal3 ;
        RECT 0.000 157.300 0.400 157.700 ;
    END
  END m_wdata[25]
  PIN m_wdata[26]
    DIRECTION INPUT ;
    USE SIGNAL ;
    ANTENNAGATEAREA 0.109200 ;
    PORT
      LAYER Metal3 ;
        RECT 176.575 147.220 176.975 147.620 ;
    END
  END m_wdata[26]
  PIN m_wdata[27]
    DIRECTION INPUT ;
    USE SIGNAL ;
    ANTENNAGATEAREA 0.109200 ;
    PORT
      LAYER Metal3 ;
        RECT 176.575 175.780 176.975 176.180 ;
    END
  END m_wdata[27]
  PIN m_wdata[28]
    DIRECTION INPUT ;
    USE SIGNAL ;
    ANTENNAGATEAREA 0.109200 ;
    PORT
      LAYER Metal3 ;
        RECT 176.575 116.140 176.975 116.540 ;
    END
  END m_wdata[28]
  PIN m_wdata[29]
    DIRECTION INPUT ;
    USE SIGNAL ;
    ANTENNAGATEAREA 0.109200 ;
    PORT
      LAYER Metal2 ;
        RECT 111.640 195.295 112.040 195.695 ;
    END
  END m_wdata[29]
  PIN m_wdata[2]
    DIRECTION INPUT ;
    USE SIGNAL ;
    ANTENNAGATEAREA 0.109200 ;
    PORT
      LAYER Metal2 ;
        RECT 17.560 0.000 17.960 0.400 ;
    END
  END m_wdata[2]
  PIN m_wdata[30]
    DIRECTION INPUT ;
    USE SIGNAL ;
    ANTENNAGATEAREA 0.109200 ;
    PORT
      LAYER Metal2 ;
        RECT 73.240 0.000 73.640 0.400 ;
    END
  END m_wdata[30]
  PIN m_wdata[31]
    DIRECTION INPUT ;
    USE SIGNAL ;
    ANTENNAGATEAREA 0.109200 ;
    PORT
      LAYER Metal3 ;
        RECT 0.000 80.860 0.400 81.260 ;
    END
  END m_wdata[31]
  PIN m_wdata[3]
    DIRECTION INPUT ;
    USE SIGNAL ;
    ANTENNAGATEAREA 0.109200 ;
    PORT
      LAYER Metal2 ;
        RECT 86.680 0.000 87.080 0.400 ;
    END
  END m_wdata[3]
  PIN m_wdata[4]
    DIRECTION INPUT ;
    USE SIGNAL ;
    ANTENNAGATEAREA 0.109200 ;
    PORT
      LAYER Metal2 ;
        RECT 36.760 195.295 37.160 195.695 ;
    END
  END m_wdata[4]
  PIN m_wdata[5]
    DIRECTION INPUT ;
    USE SIGNAL ;
    ANTENNAGATEAREA 0.109200 ;
    PORT
      LAYER Metal2 ;
        RECT 125.080 195.295 125.480 195.695 ;
    END
  END m_wdata[5]
  PIN m_wdata[6]
    DIRECTION INPUT ;
    USE SIGNAL ;
    ANTENNAGATEAREA 0.109200 ;
    PORT
      LAYER Metal3 ;
        RECT 0.000 13.660 0.400 14.060 ;
    END
  END m_wdata[6]
  PIN m_wdata[7]
    DIRECTION INPUT ;
    USE SIGNAL ;
    ANTENNAGATEAREA 0.109200 ;
    PORT
      LAYER Metal3 ;
        RECT 176.575 169.900 176.975 170.300 ;
    END
  END m_wdata[7]
  PIN m_wdata[8]
    DIRECTION INPUT ;
    USE SIGNAL ;
    ANTENNAGATEAREA 0.109200 ;
    PORT
      LAYER Metal3 ;
        RECT 176.575 140.500 176.975 140.900 ;
    END
  END m_wdata[8]
  PIN m_wdata[9]
    DIRECTION INPUT ;
    USE SIGNAL ;
    ANTENNAGATEAREA 0.109200 ;
    PORT
      LAYER Metal3 ;
        RECT 176.575 146.380 176.975 146.780 ;
    END
  END m_wdata[9]
  PIN m_wready
    DIRECTION OUTPUT ;
    USE SIGNAL ;
    ANTENNADIFFAREA 0.708600 ;
    PORT
      LAYER Metal3 ;
        RECT 0.000 122.860 0.400 123.260 ;
    END
  END m_wready
  PIN m_wstrb[0]
    DIRECTION INPUT ;
    USE SIGNAL ;
    ANTENNAGATEAREA 0.109200 ;
    PORT
      LAYER Metal3 ;
        RECT 176.575 27.940 176.975 28.340 ;
    END
  END m_wstrb[0]
  PIN m_wstrb[1]
    DIRECTION INPUT ;
    USE SIGNAL ;
    ANTENNAGATEAREA 0.109200 ;
    PORT
      LAYER Metal3 ;
        RECT 0.000 160.660 0.400 161.060 ;
    END
  END m_wstrb[1]
  PIN m_wstrb[2]
    DIRECTION INPUT ;
    USE SIGNAL ;
    ANTENNAGATEAREA 0.109200 ;
    PORT
      LAYER Metal2 ;
        RECT 83.800 195.295 84.200 195.695 ;
    END
  END m_wstrb[2]
  PIN m_wstrb[3]
    DIRECTION INPUT ;
    USE SIGNAL ;
    ANTENNAGATEAREA 0.109200 ;
    PORT
      LAYER Metal2 ;
        RECT 91.480 195.295 91.880 195.695 ;
    END
  END m_wstrb[3]
  PIN m_wvalid
    DIRECTION INPUT ;
    USE SIGNAL ;
    ANTENNAGATEAREA 0.180700 ;
    PORT
      LAYER Metal3 ;
        RECT 0.000 192.580 0.400 192.980 ;
    END
  END m_wvalid
  PIN rst_ni
    DIRECTION INPUT ;
    USE SIGNAL ;
    PORT
      LAYER Metal2 ;
        RECT 3.160 0.000 3.560 0.400 ;
    END
  END rst_ni
  PIN s_araddr[0]
    DIRECTION OUTPUT ;
    USE SIGNAL ;
    ANTENNADIFFAREA 0.708600 ;
    PORT
      LAYER Metal2 ;
        RECT 30.040 0.000 30.440 0.400 ;
    END
  END s_araddr[0]
  PIN s_araddr[100]
    DIRECTION OUTPUT ;
    USE SIGNAL ;
    ANTENNADIFFAREA 0.708600 ;
    PORT
      LAYER Metal3 ;
        RECT 176.575 162.340 176.975 162.740 ;
    END
  END s_araddr[100]
  PIN s_araddr[101]
    DIRECTION OUTPUT ;
    USE SIGNAL ;
    ANTENNADIFFAREA 0.708600 ;
    PORT
      LAYER Metal3 ;
        RECT 0.000 168.220 0.400 168.620 ;
    END
  END s_araddr[101]
  PIN s_araddr[102]
    DIRECTION OUTPUT ;
    USE SIGNAL ;
    ANTENNADIFFAREA 0.708600 ;
    PORT
      LAYER Metal3 ;
        RECT 0.000 15.340 0.400 15.740 ;
    END
  END s_araddr[102]
  PIN s_araddr[103]
    DIRECTION OUTPUT ;
    USE SIGNAL ;
    ANTENNADIFFAREA 0.708600 ;
    PORT
      LAYER Metal2 ;
        RECT 135.640 0.000 136.040 0.400 ;
    END
  END s_araddr[103]
  PIN s_araddr[104]
    DIRECTION OUTPUT ;
    USE SIGNAL ;
    ANTENNADIFFAREA 0.708600 ;
    PORT
      LAYER Metal2 ;
        RECT 55.960 195.295 56.360 195.695 ;
    END
  END s_araddr[104]
  PIN s_araddr[105]
    DIRECTION OUTPUT ;
    USE SIGNAL ;
    ANTENNADIFFAREA 0.708600 ;
    PORT
      LAYER Metal2 ;
        RECT 75.160 195.295 75.560 195.695 ;
    END
  END s_araddr[105]
  PIN s_araddr[106]
    DIRECTION OUTPUT ;
    USE SIGNAL ;
    ANTENNADIFFAREA 0.708600 ;
    PORT
      LAYER Metal2 ;
        RECT 41.560 195.295 41.960 195.695 ;
    END
  END s_araddr[106]
  PIN s_araddr[107]
    DIRECTION OUTPUT ;
    USE SIGNAL ;
    ANTENNADIFFAREA 0.708600 ;
    PORT
      LAYER Metal2 ;
        RECT 21.400 195.295 21.800 195.695 ;
    END
  END s_araddr[107]
  PIN s_araddr[108]
    DIRECTION OUTPUT ;
    USE SIGNAL ;
    ANTENNADIFFAREA 0.708600 ;
    PORT
      LAYER Metal2 ;
        RECT 134.680 0.000 135.080 0.400 ;
    END
  END s_araddr[108]
  PIN s_araddr[109]
    DIRECTION OUTPUT ;
    USE SIGNAL ;
    ANTENNADIFFAREA 0.708600 ;
    PORT
      LAYER Metal2 ;
        RECT 111.640 0.000 112.040 0.400 ;
    END
  END s_araddr[109]
  PIN s_araddr[10]
    DIRECTION OUTPUT ;
    USE SIGNAL ;
    ANTENNADIFFAREA 0.708600 ;
    PORT
      LAYER Metal2 ;
        RECT 44.440 195.295 44.840 195.695 ;
    END
  END s_araddr[10]
  PIN s_araddr[110]
    DIRECTION OUTPUT ;
    USE SIGNAL ;
    ANTENNADIFFAREA 0.708600 ;
    PORT
      LAYER Metal3 ;
        RECT 176.575 32.140 176.975 32.540 ;
    END
  END s_araddr[110]
  PIN s_araddr[111]
    DIRECTION OUTPUT ;
    USE SIGNAL ;
    ANTENNADIFFAREA 0.708600 ;
    PORT
      LAYER Metal2 ;
        RECT 151.000 0.000 151.400 0.400 ;
    END
  END s_araddr[111]
  PIN s_araddr[112]
    DIRECTION OUTPUT ;
    USE SIGNAL ;
    ANTENNADIFFAREA 0.708600 ;
    PORT
      LAYER Metal3 ;
        RECT 176.575 53.140 176.975 53.540 ;
    END
  END s_araddr[112]
  PIN s_araddr[113]
    DIRECTION OUTPUT ;
    USE SIGNAL ;
    ANTENNADIFFAREA 0.708600 ;
    PORT
      LAYER Metal3 ;
        RECT 176.575 20.380 176.975 20.780 ;
    END
  END s_araddr[113]
  PIN s_araddr[114]
    DIRECTION OUTPUT ;
    USE SIGNAL ;
    ANTENNADIFFAREA 0.708600 ;
    PORT
      LAYER Metal3 ;
        RECT 176.575 70.780 176.975 71.180 ;
    END
  END s_araddr[114]
  PIN s_araddr[115]
    DIRECTION OUTPUT ;
    USE SIGNAL ;
    ANTENNADIFFAREA 0.708600 ;
    PORT
      LAYER Metal3 ;
        RECT 176.575 14.500 176.975 14.900 ;
    END
  END s_araddr[115]
  PIN s_araddr[116]
    DIRECTION OUTPUT ;
    USE SIGNAL ;
    ANTENNADIFFAREA 0.708600 ;
    PORT
      LAYER Metal2 ;
        RECT 26.200 0.000 26.600 0.400 ;
    END
  END s_araddr[116]
  PIN s_araddr[117]
    DIRECTION OUTPUT ;
    USE SIGNAL ;
    ANTENNADIFFAREA 0.708600 ;
    PORT
      LAYER Metal2 ;
        RECT 41.560 0.000 41.960 0.400 ;
    END
  END s_araddr[117]
  PIN s_araddr[118]
    DIRECTION OUTPUT ;
    USE SIGNAL ;
    ANTENNADIFFAREA 0.708600 ;
    PORT
      LAYER Metal2 ;
        RECT 24.280 0.000 24.680 0.400 ;
    END
  END s_araddr[118]
  PIN s_araddr[119]
    DIRECTION OUTPUT ;
    USE SIGNAL ;
    ANTENNADIFFAREA 0.708600 ;
    PORT
      LAYER Metal2 ;
        RECT 79.000 0.000 79.400 0.400 ;
    END
  END s_araddr[119]
  PIN s_araddr[11]
    DIRECTION OUTPUT ;
    USE SIGNAL ;
    ANTENNADIFFAREA 0.708600 ;
    PORT
      LAYER Metal2 ;
        RECT 30.040 195.295 30.440 195.695 ;
    END
  END s_araddr[11]
  PIN s_araddr[120]
    DIRECTION OUTPUT ;
    USE SIGNAL ;
    ANTENNADIFFAREA 0.708600 ;
    PORT
      LAYER Metal2 ;
        RECT 53.080 0.000 53.480 0.400 ;
    END
  END s_araddr[120]
  PIN s_araddr[121]
    DIRECTION OUTPUT ;
    USE SIGNAL ;
    ANTENNADIFFAREA 0.708600 ;
    PORT
      LAYER Metal3 ;
        RECT 0.000 7.780 0.400 8.180 ;
    END
  END s_araddr[121]
  PIN s_araddr[122]
    DIRECTION OUTPUT ;
    USE SIGNAL ;
    ANTENNADIFFAREA 0.708600 ;
    PORT
      LAYER Metal2 ;
        RECT 45.400 0.000 45.800 0.400 ;
    END
  END s_araddr[122]
  PIN s_araddr[123]
    DIRECTION OUTPUT ;
    USE SIGNAL ;
    ANTENNADIFFAREA 0.708600 ;
    PORT
      LAYER Metal3 ;
        RECT 0.000 22.900 0.400 23.300 ;
    END
  END s_araddr[123]
  PIN s_araddr[124]
    DIRECTION OUTPUT ;
    USE SIGNAL ;
    ANTENNADIFFAREA 0.708600 ;
    PORT
      LAYER Metal3 ;
        RECT 176.575 43.900 176.975 44.300 ;
    END
  END s_araddr[124]
  PIN s_araddr[125]
    DIRECTION OUTPUT ;
    USE SIGNAL ;
    ANTENNADIFFAREA 0.708600 ;
    PORT
      LAYER Metal3 ;
        RECT 176.575 40.540 176.975 40.940 ;
    END
  END s_araddr[125]
  PIN s_araddr[126]
    DIRECTION OUTPUT ;
    USE SIGNAL ;
    ANTENNADIFFAREA 0.708600 ;
    PORT
      LAYER Metal3 ;
        RECT 176.575 32.980 176.975 33.380 ;
    END
  END s_araddr[126]
  PIN s_araddr[127]
    DIRECTION OUTPUT ;
    USE SIGNAL ;
    ANTENNADIFFAREA 0.708600 ;
    PORT
      LAYER Metal3 ;
        RECT 176.575 52.300 176.975 52.700 ;
    END
  END s_araddr[127]
  PIN s_araddr[12]
    DIRECTION OUTPUT ;
    USE SIGNAL ;
    ANTENNADIFFAREA 0.708600 ;
    PORT
      LAYER Metal2 ;
        RECT 144.280 0.000 144.680 0.400 ;
    END
  END s_araddr[12]
  PIN s_araddr[13]
    DIRECTION OUTPUT ;
    USE SIGNAL ;
    ANTENNADIFFAREA 0.708600 ;
    PORT
      LAYER Metal2 ;
        RECT 103.000 0.000 103.400 0.400 ;
    END
  END s_araddr[13]
  PIN s_araddr[14]
    DIRECTION OUTPUT ;
    USE SIGNAL ;
    ANTENNADIFFAREA 0.708600 ;
    PORT
      LAYER Metal3 ;
        RECT 176.575 31.300 176.975 31.700 ;
    END
  END s_araddr[14]
  PIN s_araddr[15]
    DIRECTION OUTPUT ;
    USE SIGNAL ;
    ANTENNADIFFAREA 0.708600 ;
    PORT
      LAYER Metal2 ;
        RECT 137.560 0.000 137.960 0.400 ;
    END
  END s_araddr[15]
  PIN s_araddr[16]
    DIRECTION OUTPUT ;
    USE SIGNAL ;
    ANTENNADIFFAREA 0.708600 ;
    PORT
      LAYER Metal3 ;
        RECT 176.575 60.700 176.975 61.100 ;
    END
  END s_araddr[16]
  PIN s_araddr[17]
    DIRECTION OUTPUT ;
    USE SIGNAL ;
    ANTENNADIFFAREA 0.708600 ;
    PORT
      LAYER Metal3 ;
        RECT 176.575 64.060 176.975 64.460 ;
    END
  END s_araddr[17]
  PIN s_araddr[18]
    DIRECTION OUTPUT ;
    USE SIGNAL ;
    ANTENNADIFFAREA 0.708600 ;
    PORT
      LAYER Metal3 ;
        RECT 176.575 69.940 176.975 70.340 ;
    END
  END s_araddr[18]
  PIN s_araddr[19]
    DIRECTION OUTPUT ;
    USE SIGNAL ;
    ANTENNADIFFAREA 0.708600 ;
    PORT
      LAYER Metal3 ;
        RECT 176.575 76.660 176.975 77.060 ;
    END
  END s_araddr[19]
  PIN s_araddr[1]
    DIRECTION OUTPUT ;
    USE SIGNAL ;
    ANTENNADIFFAREA 0.708600 ;
    PORT
      LAYER Metal3 ;
        RECT 176.575 11.980 176.975 12.380 ;
    END
  END s_araddr[1]
  PIN s_araddr[20]
    DIRECTION OUTPUT ;
    USE SIGNAL ;
    ANTENNADIFFAREA 0.708600 ;
    PORT
      LAYER Metal2 ;
        RECT 68.440 0.000 68.840 0.400 ;
    END
  END s_araddr[20]
  PIN s_araddr[21]
    DIRECTION OUTPUT ;
    USE SIGNAL ;
    ANTENNADIFFAREA 0.708600 ;
    PORT
      LAYER Metal2 ;
        RECT 60.760 0.000 61.160 0.400 ;
    END
  END s_araddr[21]
  PIN s_araddr[22]
    DIRECTION OUTPUT ;
    USE SIGNAL ;
    ANTENNADIFFAREA 0.708600 ;
    PORT
      LAYER Metal2 ;
        RECT 22.360 0.000 22.760 0.400 ;
    END
  END s_araddr[22]
  PIN s_araddr[23]
    DIRECTION OUTPUT ;
    USE SIGNAL ;
    ANTENNADIFFAREA 0.708600 ;
    PORT
      LAYER Metal2 ;
        RECT 10.840 0.000 11.240 0.400 ;
    END
  END s_araddr[23]
  PIN s_araddr[24]
    DIRECTION OUTPUT ;
    USE SIGNAL ;
    ANTENNADIFFAREA 0.708600 ;
    PORT
      LAYER Metal2 ;
        RECT 51.160 0.000 51.560 0.400 ;
    END
  END s_araddr[24]
  PIN s_araddr[25]
    DIRECTION OUTPUT ;
    USE SIGNAL ;
    ANTENNADIFFAREA 0.708600 ;
    PORT
      LAYER Metal3 ;
        RECT 0.000 6.100 0.400 6.500 ;
    END
  END s_araddr[25]
  PIN s_araddr[26]
    DIRECTION OUTPUT ;
    USE SIGNAL ;
    ANTENNADIFFAREA 0.708600 ;
    PORT
      LAYER Metal2 ;
        RECT 46.360 0.000 46.760 0.400 ;
    END
  END s_araddr[26]
  PIN s_araddr[27]
    DIRECTION OUTPUT ;
    USE SIGNAL ;
    ANTENNADIFFAREA 0.708600 ;
    PORT
      LAYER Metal3 ;
        RECT 0.000 4.420 0.400 4.820 ;
    END
  END s_araddr[27]
  PIN s_araddr[28]
    DIRECTION OUTPUT ;
    USE SIGNAL ;
    ANTENNADIFFAREA 0.708600 ;
    PORT
      LAYER Metal3 ;
        RECT 176.575 38.020 176.975 38.420 ;
    END
  END s_araddr[28]
  PIN s_araddr[29]
    DIRECTION OUTPUT ;
    USE SIGNAL ;
    ANTENNADIFFAREA 0.708600 ;
    PORT
      LAYER Metal3 ;
        RECT 176.575 43.060 176.975 43.460 ;
    END
  END s_araddr[29]
  PIN s_araddr[2]
    DIRECTION OUTPUT ;
    USE SIGNAL ;
    ANTENNADIFFAREA 0.708600 ;
    PORT
      LAYER Metal2 ;
        RECT 155.800 0.000 156.200 0.400 ;
    END
  END s_araddr[2]
  PIN s_araddr[30]
    DIRECTION OUTPUT ;
    USE SIGNAL ;
    ANTENNADIFFAREA 0.708600 ;
    PORT
      LAYER Metal3 ;
        RECT 176.575 35.500 176.975 35.900 ;
    END
  END s_araddr[30]
  PIN s_araddr[31]
    DIRECTION OUTPUT ;
    USE SIGNAL ;
    ANTENNADIFFAREA 0.708600 ;
    PORT
      LAYER Metal3 ;
        RECT 176.575 46.420 176.975 46.820 ;
    END
  END s_araddr[31]
  PIN s_araddr[32]
    DIRECTION OUTPUT ;
    USE SIGNAL ;
    ANTENNADIFFAREA 0.708600 ;
    PORT
      LAYER Metal2 ;
        RECT 28.120 0.000 28.520 0.400 ;
    END
  END s_araddr[32]
  PIN s_araddr[33]
    DIRECTION OUTPUT ;
    USE SIGNAL ;
    ANTENNADIFFAREA 0.708600 ;
    PORT
      LAYER Metal3 ;
        RECT 176.575 11.140 176.975 11.540 ;
    END
  END s_araddr[33]
  PIN s_araddr[34]
    DIRECTION OUTPUT ;
    USE SIGNAL ;
    ANTENNADIFFAREA 0.708600 ;
    PORT
      LAYER Metal2 ;
        RECT 154.840 0.000 155.240 0.400 ;
    END
  END s_araddr[34]
  PIN s_araddr[35]
    DIRECTION OUTPUT ;
    USE SIGNAL ;
    ANTENNADIFFAREA 0.708600 ;
    PORT
      LAYER Metal2 ;
        RECT 106.840 195.295 107.240 195.695 ;
    END
  END s_araddr[35]
  PIN s_araddr[36]
    DIRECTION OUTPUT ;
    USE SIGNAL ;
    ANTENNADIFFAREA 0.708600 ;
    PORT
      LAYER Metal3 ;
        RECT 176.575 92.620 176.975 93.020 ;
    END
  END s_araddr[36]
  PIN s_araddr[37]
    DIRECTION OUTPUT ;
    USE SIGNAL ;
    ANTENNADIFFAREA 0.708600 ;
    PORT
      LAYER Metal3 ;
        RECT 0.000 180.820 0.400 181.220 ;
    END
  END s_araddr[37]
  PIN s_araddr[38]
    DIRECTION OUTPUT ;
    USE SIGNAL ;
    ANTENNADIFFAREA 0.708600 ;
    PORT
      LAYER Metal3 ;
        RECT 0.000 22.060 0.400 22.460 ;
    END
  END s_araddr[38]
  PIN s_araddr[39]
    DIRECTION OUTPUT ;
    USE SIGNAL ;
    ANTENNADIFFAREA 0.708600 ;
    PORT
      LAYER Metal2 ;
        RECT 130.840 0.000 131.240 0.400 ;
    END
  END s_araddr[39]
  PIN s_araddr[3]
    DIRECTION OUTPUT ;
    USE SIGNAL ;
    ANTENNADIFFAREA 0.708600 ;
    PORT
      LAYER Metal2 ;
        RECT 133.720 195.295 134.120 195.695 ;
    END
  END s_araddr[3]
  PIN s_araddr[40]
    DIRECTION OUTPUT ;
    USE SIGNAL ;
    ANTENNADIFFAREA 0.708600 ;
    PORT
      LAYER Metal2 ;
        RECT 71.320 195.295 71.720 195.695 ;
    END
  END s_araddr[40]
  PIN s_araddr[41]
    DIRECTION OUTPUT ;
    USE SIGNAL ;
    ANTENNADIFFAREA 0.708600 ;
    PORT
      LAYER Metal2 ;
        RECT 82.840 195.295 83.240 195.695 ;
    END
  END s_araddr[41]
  PIN s_araddr[42]
    DIRECTION OUTPUT ;
    USE SIGNAL ;
    ANTENNADIFFAREA 0.708600 ;
    PORT
      LAYER Metal2 ;
        RECT 45.400 195.295 45.800 195.695 ;
    END
  END s_araddr[42]
  PIN s_araddr[43]
    DIRECTION OUTPUT ;
    USE SIGNAL ;
    ANTENNADIFFAREA 0.708600 ;
    PORT
      LAYER Metal2 ;
        RECT 29.080 195.295 29.480 195.695 ;
    END
  END s_araddr[43]
  PIN s_araddr[44]
    DIRECTION OUTPUT ;
    USE SIGNAL ;
    ANTENNADIFFAREA 0.708600 ;
    PORT
      LAYER Metal2 ;
        RECT 133.720 0.000 134.120 0.400 ;
    END
  END s_araddr[44]
  PIN s_araddr[45]
    DIRECTION OUTPUT ;
    USE SIGNAL ;
    ANTENNADIFFAREA 0.708600 ;
    PORT
      LAYER Metal2 ;
        RECT 105.880 0.000 106.280 0.400 ;
    END
  END s_araddr[45]
  PIN s_araddr[46]
    DIRECTION OUTPUT ;
    USE SIGNAL ;
    ANTENNADIFFAREA 0.708600 ;
    PORT
      LAYER Metal3 ;
        RECT 176.575 36.340 176.975 36.740 ;
    END
  END s_araddr[46]
  PIN s_araddr[47]
    DIRECTION OUTPUT ;
    USE SIGNAL ;
    ANTENNADIFFAREA 0.708600 ;
    PORT
      LAYER Metal2 ;
        RECT 139.480 0.000 139.880 0.400 ;
    END
  END s_araddr[47]
  PIN s_araddr[48]
    DIRECTION OUTPUT ;
    USE SIGNAL ;
    ANTENNADIFFAREA 0.708600 ;
    PORT
      LAYER Metal3 ;
        RECT 176.575 54.820 176.975 55.220 ;
    END
  END s_araddr[48]
  PIN s_araddr[49]
    DIRECTION OUTPUT ;
    USE SIGNAL ;
    ANTENNADIFFAREA 0.708600 ;
    PORT
      LAYER Metal3 ;
        RECT 176.575 62.380 176.975 62.780 ;
    END
  END s_araddr[49]
  PIN s_araddr[4]
    DIRECTION OUTPUT ;
    USE SIGNAL ;
    ANTENNADIFFAREA 0.708600 ;
    PORT
      LAYER Metal3 ;
        RECT 176.575 93.460 176.975 93.860 ;
    END
  END s_araddr[4]
  PIN s_araddr[50]
    DIRECTION OUTPUT ;
    USE SIGNAL ;
    ANTENNADIFFAREA 0.708600 ;
    PORT
      LAYER Metal3 ;
        RECT 176.575 69.100 176.975 69.500 ;
    END
  END s_araddr[50]
  PIN s_araddr[51]
    DIRECTION OUTPUT ;
    USE SIGNAL ;
    ANTENNADIFFAREA 0.708600 ;
    PORT
      LAYER Metal3 ;
        RECT 176.575 13.660 176.975 14.060 ;
    END
  END s_araddr[51]
  PIN s_araddr[52]
    DIRECTION OUTPUT ;
    USE SIGNAL ;
    ANTENNADIFFAREA 0.708600 ;
    PORT
      LAYER Metal2 ;
        RECT 67.480 0.000 67.880 0.400 ;
    END
  END s_araddr[52]
  PIN s_araddr[53]
    DIRECTION OUTPUT ;
    USE SIGNAL ;
    ANTENNADIFFAREA 0.708600 ;
    PORT
      LAYER Metal2 ;
        RECT 39.640 0.000 40.040 0.400 ;
    END
  END s_araddr[53]
  PIN s_araddr[54]
    DIRECTION OUTPUT ;
    USE SIGNAL ;
    ANTENNADIFFAREA 0.708600 ;
    PORT
      LAYER Metal2 ;
        RECT 23.320 0.000 23.720 0.400 ;
    END
  END s_araddr[54]
  PIN s_araddr[55]
    DIRECTION OUTPUT ;
    USE SIGNAL ;
    ANTENNADIFFAREA 0.708600 ;
    PORT
      LAYER Metal2 ;
        RECT 79.960 0.000 80.360 0.400 ;
    END
  END s_araddr[55]
  PIN s_araddr[56]
    DIRECTION OUTPUT ;
    USE SIGNAL ;
    ANTENNADIFFAREA 0.708600 ;
    PORT
      LAYER Metal2 ;
        RECT 48.280 0.000 48.680 0.400 ;
    END
  END s_araddr[56]
  PIN s_araddr[57]
    DIRECTION OUTPUT ;
    USE SIGNAL ;
    ANTENNADIFFAREA 0.708600 ;
    PORT
      LAYER Metal3 ;
        RECT 0.000 2.740 0.400 3.140 ;
    END
  END s_araddr[57]
  PIN s_araddr[58]
    DIRECTION OUTPUT ;
    USE SIGNAL ;
    ANTENNADIFFAREA 0.708600 ;
    PORT
      LAYER Metal2 ;
        RECT 44.440 0.000 44.840 0.400 ;
    END
  END s_araddr[58]
  PIN s_araddr[59]
    DIRECTION OUTPUT ;
    USE SIGNAL ;
    ANTENNADIFFAREA 0.708600 ;
    PORT
      LAYER Metal3 ;
        RECT 0.000 18.700 0.400 19.100 ;
    END
  END s_araddr[59]
  PIN s_araddr[5]
    DIRECTION OUTPUT ;
    USE SIGNAL ;
    ANTENNADIFFAREA 0.708600 ;
    PORT
      LAYER Metal3 ;
        RECT 0.000 167.380 0.400 167.780 ;
    END
  END s_araddr[5]
  PIN s_araddr[60]
    DIRECTION OUTPUT ;
    USE SIGNAL ;
    ANTENNADIFFAREA 0.708600 ;
    PORT
      LAYER Metal3 ;
        RECT 176.575 45.580 176.975 45.980 ;
    END
  END s_araddr[60]
  PIN s_araddr[61]
    DIRECTION OUTPUT ;
    USE SIGNAL ;
    ANTENNADIFFAREA 0.708600 ;
    PORT
      LAYER Metal3 ;
        RECT 176.575 42.220 176.975 42.620 ;
    END
  END s_araddr[61]
  PIN s_araddr[62]
    DIRECTION OUTPUT ;
    USE SIGNAL ;
    ANTENNADIFFAREA 0.708600 ;
    PORT
      LAYER Metal3 ;
        RECT 176.575 34.660 176.975 35.060 ;
    END
  END s_araddr[62]
  PIN s_araddr[63]
    DIRECTION OUTPUT ;
    USE SIGNAL ;
    ANTENNADIFFAREA 0.708600 ;
    PORT
      LAYER Metal3 ;
        RECT 176.575 51.460 176.975 51.860 ;
    END
  END s_araddr[63]
  PIN s_araddr[64]
    DIRECTION OUTPUT ;
    USE SIGNAL ;
    ANTENNADIFFAREA 0.708600 ;
    PORT
      LAYER Metal2 ;
        RECT 27.160 0.000 27.560 0.400 ;
    END
  END s_araddr[64]
  PIN s_araddr[65]
    DIRECTION OUTPUT ;
    USE SIGNAL ;
    ANTENNADIFFAREA 0.708600 ;
    PORT
      LAYER Metal3 ;
        RECT 176.575 10.300 176.975 10.700 ;
    END
  END s_araddr[65]
  PIN s_araddr[66]
    DIRECTION OUTPUT ;
    USE SIGNAL ;
    ANTENNADIFFAREA 0.708600 ;
    PORT
      LAYER Metal2 ;
        RECT 152.920 0.000 153.320 0.400 ;
    END
  END s_araddr[66]
  PIN s_araddr[67]
    DIRECTION OUTPUT ;
    USE SIGNAL ;
    ANTENNADIFFAREA 0.708600 ;
    PORT
      LAYER Metal2 ;
        RECT 137.560 195.295 137.960 195.695 ;
    END
  END s_araddr[67]
  PIN s_araddr[68]
    DIRECTION OUTPUT ;
    USE SIGNAL ;
    ANTENNADIFFAREA 0.708600 ;
    PORT
      LAYER Metal3 ;
        RECT 176.575 97.660 176.975 98.060 ;
    END
  END s_araddr[68]
  PIN s_araddr[69]
    DIRECTION OUTPUT ;
    USE SIGNAL ;
    ANTENNADIFFAREA 0.708600 ;
    PORT
      LAYER Metal3 ;
        RECT 0.000 169.060 0.400 169.460 ;
    END
  END s_araddr[69]
  PIN s_araddr[6]
    DIRECTION OUTPUT ;
    USE SIGNAL ;
    ANTENNADIFFAREA 0.708600 ;
    PORT
      LAYER Metal3 ;
        RECT 0.000 20.380 0.400 20.780 ;
    END
  END s_araddr[6]
  PIN s_araddr[70]
    DIRECTION OUTPUT ;
    USE SIGNAL ;
    ANTENNADIFFAREA 0.708600 ;
    PORT
      LAYER Metal3 ;
        RECT 0.000 9.460 0.400 9.860 ;
    END
  END s_araddr[70]
  PIN s_araddr[71]
    DIRECTION OUTPUT ;
    USE SIGNAL ;
    ANTENNADIFFAREA 0.708600 ;
    PORT
      LAYER Metal2 ;
        RECT 129.880 0.000 130.280 0.400 ;
    END
  END s_araddr[71]
  PIN s_araddr[72]
    DIRECTION OUTPUT ;
    USE SIGNAL ;
    ANTENNADIFFAREA 0.708600 ;
    PORT
      LAYER Metal2 ;
        RECT 19.480 195.295 19.880 195.695 ;
    END
  END s_araddr[72]
  PIN s_araddr[73]
    DIRECTION OUTPUT ;
    USE SIGNAL ;
    ANTENNADIFFAREA 0.708600 ;
    PORT
      LAYER Metal2 ;
        RECT 79.000 195.295 79.400 195.695 ;
    END
  END s_araddr[73]
  PIN s_araddr[74]
    DIRECTION OUTPUT ;
    USE SIGNAL ;
    ANTENNADIFFAREA 0.708600 ;
    PORT
      LAYER Metal2 ;
        RECT 38.680 195.295 39.080 195.695 ;
    END
  END s_araddr[74]
  PIN s_araddr[75]
    DIRECTION OUTPUT ;
    USE SIGNAL ;
    ANTENNADIFFAREA 0.708600 ;
    PORT
      LAYER Metal2 ;
        RECT 70.360 195.295 70.760 195.695 ;
    END
  END s_araddr[75]
  PIN s_araddr[76]
    DIRECTION OUTPUT ;
    USE SIGNAL ;
    ANTENNADIFFAREA 0.708600 ;
    PORT
      LAYER Metal2 ;
        RECT 136.600 0.000 137.000 0.400 ;
    END
  END s_araddr[76]
  PIN s_araddr[77]
    DIRECTION OUTPUT ;
    USE SIGNAL ;
    ANTENNADIFFAREA 0.708600 ;
    PORT
      LAYER Metal2 ;
        RECT 102.040 0.000 102.440 0.400 ;
    END
  END s_araddr[77]
  PIN s_araddr[78]
    DIRECTION OUTPUT ;
    USE SIGNAL ;
    ANTENNADIFFAREA 0.708600 ;
    PORT
      LAYER Metal3 ;
        RECT 176.575 29.620 176.975 30.020 ;
    END
  END s_araddr[78]
  PIN s_araddr[79]
    DIRECTION OUTPUT ;
    USE SIGNAL ;
    ANTENNADIFFAREA 0.708600 ;
    PORT
      LAYER Metal2 ;
        RECT 138.520 0.000 138.920 0.400 ;
    END
  END s_araddr[79]
  PIN s_araddr[7]
    DIRECTION OUTPUT ;
    USE SIGNAL ;
    ANTENNADIFFAREA 0.708600 ;
    PORT
      LAYER Metal2 ;
        RECT 131.800 0.000 132.200 0.400 ;
    END
  END s_araddr[7]
  PIN s_araddr[80]
    DIRECTION OUTPUT ;
    USE SIGNAL ;
    ANTENNADIFFAREA 0.708600 ;
    PORT
      LAYER Metal3 ;
        RECT 176.575 57.340 176.975 57.740 ;
    END
  END s_araddr[80]
  PIN s_araddr[81]
    DIRECTION OUTPUT ;
    USE SIGNAL ;
    ANTENNADIFFAREA 0.708600 ;
    PORT
      LAYER Metal3 ;
        RECT 176.575 64.900 176.975 65.300 ;
    END
  END s_araddr[81]
  PIN s_araddr[82]
    DIRECTION OUTPUT ;
    USE SIGNAL ;
    ANTENNADIFFAREA 0.708600 ;
    PORT
      LAYER Metal3 ;
        RECT 176.575 66.580 176.975 66.980 ;
    END
  END s_araddr[82]
  PIN s_araddr[83]
    DIRECTION OUTPUT ;
    USE SIGNAL ;
    ANTENNADIFFAREA 0.708600 ;
    PORT
      LAYER Metal3 ;
        RECT 176.575 75.820 176.975 76.220 ;
    END
  END s_araddr[83]
  PIN s_araddr[84]
    DIRECTION OUTPUT ;
    USE SIGNAL ;
    ANTENNADIFFAREA 0.708600 ;
    PORT
      LAYER Metal2 ;
        RECT 69.400 0.000 69.800 0.400 ;
    END
  END s_araddr[84]
  PIN s_araddr[85]
    DIRECTION OUTPUT ;
    USE SIGNAL ;
    ANTENNADIFFAREA 0.708600 ;
    PORT
      LAYER Metal2 ;
        RECT 59.800 0.000 60.200 0.400 ;
    END
  END s_araddr[85]
  PIN s_araddr[86]
    DIRECTION OUTPUT ;
    USE SIGNAL ;
    ANTENNADIFFAREA 0.708600 ;
    PORT
      LAYER Metal2 ;
        RECT 21.400 0.000 21.800 0.400 ;
    END
  END s_araddr[86]
  PIN s_araddr[87]
    DIRECTION OUTPUT ;
    USE SIGNAL ;
    ANTENNADIFFAREA 0.708600 ;
    PORT
      LAYER Metal2 ;
        RECT 9.880 0.000 10.280 0.400 ;
    END
  END s_araddr[87]
  PIN s_araddr[88]
    DIRECTION OUTPUT ;
    USE SIGNAL ;
    ANTENNADIFFAREA 0.708600 ;
    PORT
      LAYER Metal2 ;
        RECT 50.200 0.000 50.600 0.400 ;
    END
  END s_araddr[88]
  PIN s_araddr[89]
    DIRECTION OUTPUT ;
    USE SIGNAL ;
    ANTENNADIFFAREA 0.708600 ;
    PORT
      LAYER Metal3 ;
        RECT 0.000 8.620 0.400 9.020 ;
    END
  END s_araddr[89]
  PIN s_araddr[8]
    DIRECTION OUTPUT ;
    USE SIGNAL ;
    ANTENNADIFFAREA 0.708600 ;
    PORT
      LAYER Metal2 ;
        RECT 51.160 195.295 51.560 195.695 ;
    END
  END s_araddr[8]
  PIN s_araddr[90]
    DIRECTION OUTPUT ;
    USE SIGNAL ;
    ANTENNADIFFAREA 0.708600 ;
    PORT
      LAYER Metal2 ;
        RECT 54.040 0.000 54.440 0.400 ;
    END
  END s_araddr[90]
  PIN s_araddr[91]
    DIRECTION OUTPUT ;
    USE SIGNAL ;
    ANTENNADIFFAREA 0.708600 ;
    PORT
      LAYER Metal3 ;
        RECT 0.000 17.860 0.400 18.260 ;
    END
  END s_araddr[91]
  PIN s_araddr[92]
    DIRECTION OUTPUT ;
    USE SIGNAL ;
    ANTENNADIFFAREA 0.708600 ;
    PORT
      LAYER Metal3 ;
        RECT 176.575 39.700 176.975 40.100 ;
    END
  END s_araddr[92]
  PIN s_araddr[93]
    DIRECTION OUTPUT ;
    USE SIGNAL ;
    ANTENNADIFFAREA 0.708600 ;
    PORT
      LAYER Metal3 ;
        RECT 176.575 41.380 176.975 41.780 ;
    END
  END s_araddr[93]
  PIN s_araddr[94]
    DIRECTION OUTPUT ;
    USE SIGNAL ;
    ANTENNADIFFAREA 0.708600 ;
    PORT
      LAYER Metal3 ;
        RECT 176.575 33.820 176.975 34.220 ;
    END
  END s_araddr[94]
  PIN s_araddr[95]
    DIRECTION OUTPUT ;
    USE SIGNAL ;
    ANTENNADIFFAREA 0.708600 ;
    PORT
      LAYER Metal3 ;
        RECT 176.575 50.620 176.975 51.020 ;
    END
  END s_araddr[95]
  PIN s_araddr[96]
    DIRECTION OUTPUT ;
    USE SIGNAL ;
    ANTENNADIFFAREA 0.708600 ;
    PORT
      LAYER Metal2 ;
        RECT 29.080 0.000 29.480 0.400 ;
    END
  END s_araddr[96]
  PIN s_araddr[97]
    DIRECTION OUTPUT ;
    USE SIGNAL ;
    ANTENNADIFFAREA 0.708600 ;
    PORT
      LAYER Metal3 ;
        RECT 176.575 9.460 176.975 9.860 ;
    END
  END s_araddr[97]
  PIN s_araddr[98]
    DIRECTION OUTPUT ;
    USE SIGNAL ;
    ANTENNADIFFAREA 0.708600 ;
    PORT
      LAYER Metal2 ;
        RECT 153.880 0.000 154.280 0.400 ;
    END
  END s_araddr[98]
  PIN s_araddr[99]
    DIRECTION OUTPUT ;
    USE SIGNAL ;
    ANTENNADIFFAREA 0.708600 ;
    PORT
      LAYER Metal2 ;
        RECT 138.520 195.295 138.920 195.695 ;
    END
  END s_araddr[99]
  PIN s_araddr[9]
    DIRECTION OUTPUT ;
    USE SIGNAL ;
    ANTENNADIFFAREA 0.708600 ;
    PORT
      LAYER Metal2 ;
        RECT 25.240 195.295 25.640 195.695 ;
    END
  END s_araddr[9]
  PIN s_arprot[0]
    DIRECTION OUTPUT ;
    USE SIGNAL ;
    ANTENNADIFFAREA 0.708600 ;
    PORT
      LAYER Metal3 ;
        RECT 0.000 24.580 0.400 24.980 ;
    END
  END s_arprot[0]
  PIN s_arprot[10]
    DIRECTION OUTPUT ;
    USE SIGNAL ;
    ANTENNADIFFAREA 0.708600 ;
    PORT
      LAYER Metal2 ;
        RECT 93.400 0.000 93.800 0.400 ;
    END
  END s_arprot[10]
  PIN s_arprot[11]
    DIRECTION OUTPUT ;
    USE SIGNAL ;
    ANTENNADIFFAREA 0.708600 ;
    PORT
      LAYER Metal2 ;
        RECT 116.440 195.295 116.840 195.695 ;
    END
  END s_arprot[11]
  PIN s_arprot[1]
    DIRECTION OUTPUT ;
    USE SIGNAL ;
    ANTENNADIFFAREA 0.708600 ;
    PORT
      LAYER Metal2 ;
        RECT 88.600 0.000 89.000 0.400 ;
    END
  END s_arprot[1]
  PIN s_arprot[2]
    DIRECTION OUTPUT ;
    USE SIGNAL ;
    ANTENNADIFFAREA 0.708600 ;
    PORT
      LAYER Metal2 ;
        RECT 120.280 195.295 120.680 195.695 ;
    END
  END s_arprot[2]
  PIN s_arprot[3]
    DIRECTION OUTPUT ;
    USE SIGNAL ;
    ANTENNADIFFAREA 0.708600 ;
    PORT
      LAYER Metal3 ;
        RECT 0.000 23.740 0.400 24.140 ;
    END
  END s_arprot[3]
  PIN s_arprot[4]
    DIRECTION OUTPUT ;
    USE SIGNAL ;
    ANTENNADIFFAREA 0.708600 ;
    PORT
      LAYER Metal2 ;
        RECT 99.160 0.000 99.560 0.400 ;
    END
  END s_arprot[4]
  PIN s_arprot[5]
    DIRECTION OUTPUT ;
    USE SIGNAL ;
    ANTENNADIFFAREA 0.708600 ;
    PORT
      LAYER Metal2 ;
        RECT 117.400 195.295 117.800 195.695 ;
    END
  END s_arprot[5]
  PIN s_arprot[6]
    DIRECTION OUTPUT ;
    USE SIGNAL ;
    ANTENNADIFFAREA 0.708600 ;
    PORT
      LAYER Metal3 ;
        RECT 0.000 17.020 0.400 17.420 ;
    END
  END s_arprot[6]
  PIN s_arprot[7]
    DIRECTION OUTPUT ;
    USE SIGNAL ;
    ANTENNADIFFAREA 0.708600 ;
    PORT
      LAYER Metal2 ;
        RECT 97.240 0.000 97.640 0.400 ;
    END
  END s_arprot[7]
  PIN s_arprot[8]
    DIRECTION OUTPUT ;
    USE SIGNAL ;
    ANTENNADIFFAREA 0.708600 ;
    PORT
      LAYER Metal2 ;
        RECT 119.320 195.295 119.720 195.695 ;
    END
  END s_arprot[8]
  PIN s_arprot[9]
    DIRECTION OUTPUT ;
    USE SIGNAL ;
    ANTENNADIFFAREA 0.708600 ;
    PORT
      LAYER Metal3 ;
        RECT 0.000 10.300 0.400 10.700 ;
    END
  END s_arprot[9]
  PIN s_arready[0]
    DIRECTION INPUT ;
    USE SIGNAL ;
    ANTENNAGATEAREA 0.180700 ;
    PORT
      LAYER Metal3 ;
        RECT 176.575 111.940 176.975 112.340 ;
    END
  END s_arready[0]
  PIN s_arready[1]
    DIRECTION INPUT ;
    USE SIGNAL ;
    ANTENNAGATEAREA 0.180700 ;
    PORT
      LAYER Metal3 ;
        RECT 176.575 106.900 176.975 107.300 ;
    END
  END s_arready[1]
  PIN s_arready[2]
    DIRECTION INPUT ;
    USE SIGNAL ;
    ANTENNAGATEAREA 0.180700 ;
    PORT
      LAYER Metal2 ;
        RECT 97.240 195.295 97.640 195.695 ;
    END
  END s_arready[2]
  PIN s_arready[3]
    DIRECTION INPUT ;
    USE SIGNAL ;
    ANTENNAGATEAREA 0.180700 ;
    PORT
      LAYER Metal3 ;
        RECT 176.575 116.980 176.975 117.380 ;
    END
  END s_arready[3]
  PIN s_arvalid[0]
    DIRECTION OUTPUT ;
    USE SIGNAL ;
    ANTENNADIFFAREA 0.708600 ;
    PORT
      LAYER Metal3 ;
        RECT 176.575 53.980 176.975 54.380 ;
    END
  END s_arvalid[0]
  PIN s_arvalid[1]
    DIRECTION OUTPUT ;
    USE SIGNAL ;
    ANTENNADIFFAREA 0.708600 ;
    PORT
      LAYER Metal3 ;
        RECT 176.575 48.940 176.975 49.340 ;
    END
  END s_arvalid[1]
  PIN s_arvalid[2]
    DIRECTION OUTPUT ;
    USE SIGNAL ;
    ANTENNADIFFAREA 0.708600 ;
    PORT
      LAYER Metal3 ;
        RECT 176.575 49.780 176.975 50.180 ;
    END
  END s_arvalid[2]
  PIN s_arvalid[3]
    DIRECTION OUTPUT ;
    USE SIGNAL ;
    ANTENNADIFFAREA 0.708600 ;
    PORT
      LAYER Metal2 ;
        RECT 145.240 0.000 145.640 0.400 ;
    END
  END s_arvalid[3]
  PIN s_awaddr[0]
    DIRECTION OUTPUT ;
    USE SIGNAL ;
    ANTENNADIFFAREA 0.708600 ;
    PORT
      LAYER Metal3 ;
        RECT 0.000 16.180 0.400 16.580 ;
    END
  END s_awaddr[0]
  PIN s_awaddr[100]
    DIRECTION OUTPUT ;
    USE SIGNAL ;
    ANTENNADIFFAREA 0.708600 ;
    PORT
      LAYER Metal3 ;
        RECT 176.575 174.100 176.975 174.500 ;
    END
  END s_awaddr[100]
  PIN s_awaddr[101]
    DIRECTION OUTPUT ;
    USE SIGNAL ;
    ANTENNADIFFAREA 0.708600 ;
    PORT
      LAYER Metal2 ;
        RECT 120.280 0.000 120.680 0.400 ;
    END
  END s_awaddr[101]
  PIN s_awaddr[102]
    DIRECTION OUTPUT ;
    USE SIGNAL ;
    ANTENNADIFFAREA 0.708600 ;
    PORT
      LAYER Metal2 ;
        RECT 115.480 0.000 115.880 0.400 ;
    END
  END s_awaddr[102]
  PIN s_awaddr[103]
    DIRECTION OUTPUT ;
    USE SIGNAL ;
    ANTENNADIFFAREA 0.708600 ;
    PORT
      LAYER Metal3 ;
        RECT 176.575 186.700 176.975 187.100 ;
    END
  END s_awaddr[103]
  PIN s_awaddr[104]
    DIRECTION OUTPUT ;
    USE SIGNAL ;
    ANTENNADIFFAREA 0.708600 ;
    PORT
      LAYER Metal3 ;
        RECT 0.000 1.900 0.400 2.300 ;
    END
  END s_awaddr[104]
  PIN s_awaddr[105]
    DIRECTION OUTPUT ;
    USE SIGNAL ;
    ANTENNADIFFAREA 0.708600 ;
    PORT
      LAYER Metal2 ;
        RECT 103.960 195.295 104.360 195.695 ;
    END
  END s_awaddr[105]
  PIN s_awaddr[106]
    DIRECTION OUTPUT ;
    USE SIGNAL ;
    ANTENNADIFFAREA 0.708600 ;
    PORT
      LAYER Metal2 ;
        RECT 72.280 195.295 72.680 195.695 ;
    END
  END s_awaddr[106]
  PIN s_awaddr[107]
    DIRECTION OUTPUT ;
    USE SIGNAL ;
    ANTENNADIFFAREA 0.708600 ;
    PORT
      LAYER Metal3 ;
        RECT 176.575 176.620 176.975 177.020 ;
    END
  END s_awaddr[107]
  PIN s_awaddr[108]
    DIRECTION OUTPUT ;
    USE SIGNAL ;
    ANTENNADIFFAREA 0.708600 ;
    PORT
      LAYER Metal3 ;
        RECT 0.000 87.580 0.400 87.980 ;
    END
  END s_awaddr[108]
  PIN s_awaddr[109]
    DIRECTION OUTPUT ;
    USE SIGNAL ;
    ANTENNADIFFAREA 0.708600 ;
    PORT
      LAYER Metal3 ;
        RECT 0.000 109.420 0.400 109.820 ;
    END
  END s_awaddr[109]
  PIN s_awaddr[10]
    DIRECTION OUTPUT ;
    USE SIGNAL ;
    ANTENNADIFFAREA 0.708600 ;
    PORT
      LAYER Metal2 ;
        RECT 62.680 195.295 63.080 195.695 ;
    END
  END s_awaddr[10]
  PIN s_awaddr[110]
    DIRECTION OUTPUT ;
    USE SIGNAL ;
    ANTENNADIFFAREA 0.708600 ;
    PORT
      LAYER Metal3 ;
        RECT 0.000 97.660 0.400 98.060 ;
    END
  END s_awaddr[110]
  PIN s_awaddr[111]
    DIRECTION OUTPUT ;
    USE SIGNAL ;
    ANTENNADIFFAREA 0.708600 ;
    PORT
      LAYER Metal3 ;
        RECT 0.000 90.940 0.400 91.340 ;
    END
  END s_awaddr[111]
  PIN s_awaddr[112]
    DIRECTION OUTPUT ;
    USE SIGNAL ;
    ANTENNADIFFAREA 0.708600 ;
    PORT
      LAYER Metal3 ;
        RECT 0.000 191.740 0.400 192.140 ;
    END
  END s_awaddr[112]
  PIN s_awaddr[113]
    DIRECTION OUTPUT ;
    USE SIGNAL ;
    ANTENNADIFFAREA 0.708600 ;
    PORT
      LAYER Metal3 ;
        RECT 0.000 139.660 0.400 140.060 ;
    END
  END s_awaddr[113]
  PIN s_awaddr[114]
    DIRECTION OUTPUT ;
    USE SIGNAL ;
    ANTENNADIFFAREA 0.708600 ;
    PORT
      LAYER Metal3 ;
        RECT 0.000 147.220 0.400 147.620 ;
    END
  END s_awaddr[114]
  PIN s_awaddr[115]
    DIRECTION OUTPUT ;
    USE SIGNAL ;
    ANTENNADIFFAREA 0.708600 ;
    PORT
      LAYER Metal3 ;
        RECT 0.000 148.060 0.400 148.460 ;
    END
  END s_awaddr[115]
  PIN s_awaddr[116]
    DIRECTION OUTPUT ;
    USE SIGNAL ;
    ANTENNADIFFAREA 0.708600 ;
    PORT
      LAYER Metal3 ;
        RECT 0.000 63.220 0.400 63.620 ;
    END
  END s_awaddr[116]
  PIN s_awaddr[117]
    DIRECTION OUTPUT ;
    USE SIGNAL ;
    ANTENNADIFFAREA 0.708600 ;
    PORT
      LAYER Metal3 ;
        RECT 0.000 76.660 0.400 77.060 ;
    END
  END s_awaddr[117]
  PIN s_awaddr[118]
    DIRECTION OUTPUT ;
    USE SIGNAL ;
    ANTENNADIFFAREA 0.708600 ;
    PORT
      LAYER Metal3 ;
        RECT 0.000 73.300 0.400 73.700 ;
    END
  END s_awaddr[118]
  PIN s_awaddr[119]
    DIRECTION OUTPUT ;
    USE SIGNAL ;
    ANTENNADIFFAREA 0.708600 ;
    PORT
      LAYER Metal3 ;
        RECT 0.000 51.460 0.400 51.860 ;
    END
  END s_awaddr[119]
  PIN s_awaddr[11]
    DIRECTION OUTPUT ;
    USE SIGNAL ;
    ANTENNADIFFAREA 0.708600 ;
    PORT
      LAYER Metal3 ;
        RECT 176.575 190.900 176.975 191.300 ;
    END
  END s_awaddr[11]
  PIN s_awaddr[120]
    DIRECTION OUTPUT ;
    USE SIGNAL ;
    ANTENNADIFFAREA 0.708600 ;
    PORT
      LAYER Metal3 ;
        RECT 0.000 71.620 0.400 72.020 ;
    END
  END s_awaddr[120]
  PIN s_awaddr[121]
    DIRECTION OUTPUT ;
    USE SIGNAL ;
    ANTENNADIFFAREA 0.708600 ;
    PORT
      LAYER Metal3 ;
        RECT 0.000 35.500 0.400 35.900 ;
    END
  END s_awaddr[121]
  PIN s_awaddr[122]
    DIRECTION OUTPUT ;
    USE SIGNAL ;
    ANTENNADIFFAREA 0.708600 ;
    PORT
      LAYER Metal3 ;
        RECT 0.000 64.060 0.400 64.460 ;
    END
  END s_awaddr[122]
  PIN s_awaddr[123]
    DIRECTION OUTPUT ;
    USE SIGNAL ;
    ANTENNADIFFAREA 0.708600 ;
    PORT
      LAYER Metal3 ;
        RECT 0.000 70.780 0.400 71.180 ;
    END
  END s_awaddr[123]
  PIN s_awaddr[124]
    DIRECTION OUTPUT ;
    USE SIGNAL ;
    ANTENNADIFFAREA 0.708600 ;
    PORT
      LAYER Metal3 ;
        RECT 0.000 165.700 0.400 166.100 ;
    END
  END s_awaddr[124]
  PIN s_awaddr[125]
    DIRECTION OUTPUT ;
    USE SIGNAL ;
    ANTENNADIFFAREA 0.708600 ;
    PORT
      LAYER Metal3 ;
        RECT 0.000 151.420 0.400 151.820 ;
    END
  END s_awaddr[125]
  PIN s_awaddr[126]
    DIRECTION OUTPUT ;
    USE SIGNAL ;
    ANTENNADIFFAREA 0.708600 ;
    PORT
      LAYER Metal3 ;
        RECT 0.000 143.020 0.400 143.420 ;
    END
  END s_awaddr[126]
  PIN s_awaddr[127]
    DIRECTION OUTPUT ;
    USE SIGNAL ;
    ANTENNADIFFAREA 0.708600 ;
    PORT
      LAYER Metal3 ;
        RECT 0.000 144.700 0.400 145.100 ;
    END
  END s_awaddr[127]
  PIN s_awaddr[12]
    DIRECTION OUTPUT ;
    USE SIGNAL ;
    ANTENNADIFFAREA 0.708600 ;
    PORT
      LAYER Metal3 ;
        RECT 0.000 89.260 0.400 89.660 ;
    END
  END s_awaddr[12]
  PIN s_awaddr[13]
    DIRECTION OUTPUT ;
    USE SIGNAL ;
    ANTENNADIFFAREA 0.708600 ;
    PORT
      LAYER Metal3 ;
        RECT 0.000 115.300 0.400 115.700 ;
    END
  END s_awaddr[13]
  PIN s_awaddr[14]
    DIRECTION OUTPUT ;
    USE SIGNAL ;
    ANTENNADIFFAREA 0.708600 ;
    PORT
      LAYER Metal3 ;
        RECT 0.000 94.300 0.400 94.700 ;
    END
  END s_awaddr[14]
  PIN s_awaddr[15]
    DIRECTION OUTPUT ;
    USE SIGNAL ;
    ANTENNADIFFAREA 0.708600 ;
    PORT
      LAYER Metal3 ;
        RECT 0.000 93.460 0.400 93.860 ;
    END
  END s_awaddr[15]
  PIN s_awaddr[16]
    DIRECTION OUTPUT ;
    USE SIGNAL ;
    ANTENNADIFFAREA 0.708600 ;
    PORT
      LAYER Metal3 ;
        RECT 0.000 177.460 0.400 177.860 ;
    END
  END s_awaddr[16]
  PIN s_awaddr[17]
    DIRECTION OUTPUT ;
    USE SIGNAL ;
    ANTENNADIFFAREA 0.708600 ;
    PORT
      LAYER Metal3 ;
        RECT 0.000 137.980 0.400 138.380 ;
    END
  END s_awaddr[17]
  PIN s_awaddr[18]
    DIRECTION OUTPUT ;
    USE SIGNAL ;
    ANTENNADIFFAREA 0.708600 ;
    PORT
      LAYER Metal3 ;
        RECT 0.000 174.100 0.400 174.500 ;
    END
  END s_awaddr[18]
  PIN s_awaddr[19]
    DIRECTION OUTPUT ;
    USE SIGNAL ;
    ANTENNADIFFAREA 0.708600 ;
    PORT
      LAYER Metal3 ;
        RECT 0.000 150.580 0.400 150.980 ;
    END
  END s_awaddr[19]
  PIN s_awaddr[1]
    DIRECTION OUTPUT ;
    USE SIGNAL ;
    ANTENNADIFFAREA 0.708600 ;
    PORT
      LAYER Metal2 ;
        RECT 116.440 0.000 116.840 0.400 ;
    END
  END s_awaddr[1]
  PIN s_awaddr[20]
    DIRECTION OUTPUT ;
    USE SIGNAL ;
    ANTENNADIFFAREA 0.708600 ;
    PORT
      LAYER Metal3 ;
        RECT 0.000 31.300 0.400 31.700 ;
    END
  END s_awaddr[20]
  PIN s_awaddr[21]
    DIRECTION OUTPUT ;
    USE SIGNAL ;
    ANTENNADIFFAREA 0.708600 ;
    PORT
      LAYER Metal3 ;
        RECT 0.000 56.500 0.400 56.900 ;
    END
  END s_awaddr[21]
  PIN s_awaddr[22]
    DIRECTION OUTPUT ;
    USE SIGNAL ;
    ANTENNADIFFAREA 0.708600 ;
    PORT
      LAYER Metal3 ;
        RECT 0.000 81.700 0.400 82.100 ;
    END
  END s_awaddr[22]
  PIN s_awaddr[23]
    DIRECTION OUTPUT ;
    USE SIGNAL ;
    ANTENNADIFFAREA 0.708600 ;
    PORT
      LAYER Metal3 ;
        RECT 0.000 82.540 0.400 82.940 ;
    END
  END s_awaddr[23]
  PIN s_awaddr[24]
    DIRECTION OUTPUT ;
    USE SIGNAL ;
    ANTENNADIFFAREA 0.708600 ;
    PORT
      LAYER Metal3 ;
        RECT 0.000 62.380 0.400 62.780 ;
    END
  END s_awaddr[24]
  PIN s_awaddr[25]
    DIRECTION OUTPUT ;
    USE SIGNAL ;
    ANTENNADIFFAREA 0.708600 ;
    PORT
      LAYER Metal3 ;
        RECT 0.000 58.180 0.400 58.580 ;
    END
  END s_awaddr[25]
  PIN s_awaddr[26]
    DIRECTION OUTPUT ;
    USE SIGNAL ;
    ANTENNADIFFAREA 0.708600 ;
    PORT
      LAYER Metal3 ;
        RECT 0.000 85.060 0.400 85.460 ;
    END
  END s_awaddr[26]
  PIN s_awaddr[27]
    DIRECTION OUTPUT ;
    USE SIGNAL ;
    ANTENNADIFFAREA 0.708600 ;
    PORT
      LAYER Metal3 ;
        RECT 0.000 74.140 0.400 74.540 ;
    END
  END s_awaddr[27]
  PIN s_awaddr[28]
    DIRECTION OUTPUT ;
    USE SIGNAL ;
    ANTENNADIFFAREA 0.708600 ;
    PORT
      LAYER Metal3 ;
        RECT 0.000 169.900 0.400 170.300 ;
    END
  END s_awaddr[28]
  PIN s_awaddr[29]
    DIRECTION OUTPUT ;
    USE SIGNAL ;
    ANTENNADIFFAREA 0.708600 ;
    PORT
      LAYER Metal3 ;
        RECT 0.000 153.100 0.400 153.500 ;
    END
  END s_awaddr[29]
  PIN s_awaddr[2]
    DIRECTION OUTPUT ;
    USE SIGNAL ;
    ANTENNADIFFAREA 0.708600 ;
    PORT
      LAYER Metal2 ;
        RECT 66.520 0.000 66.920 0.400 ;
    END
  END s_awaddr[2]
  PIN s_awaddr[30]
    DIRECTION OUTPUT ;
    USE SIGNAL ;
    ANTENNADIFFAREA 0.708600 ;
    PORT
      LAYER Metal3 ;
        RECT 0.000 187.540 0.400 187.940 ;
    END
  END s_awaddr[30]
  PIN s_awaddr[31]
    DIRECTION OUTPUT ;
    USE SIGNAL ;
    ANTENNADIFFAREA 0.708600 ;
    PORT
      LAYER Metal3 ;
        RECT 0.000 145.540 0.400 145.940 ;
    END
  END s_awaddr[31]
  PIN s_awaddr[32]
    DIRECTION OUTPUT ;
    USE SIGNAL ;
    ANTENNADIFFAREA 0.708600 ;
    PORT
      LAYER Metal3 ;
        RECT 0.000 14.500 0.400 14.900 ;
    END
  END s_awaddr[32]
  PIN s_awaddr[33]
    DIRECTION OUTPUT ;
    USE SIGNAL ;
    ANTENNADIFFAREA 0.708600 ;
    PORT
      LAYER Metal2 ;
        RECT 112.600 0.000 113.000 0.400 ;
    END
  END s_awaddr[33]
  PIN s_awaddr[34]
    DIRECTION OUTPUT ;
    USE SIGNAL ;
    ANTENNADIFFAREA 0.708600 ;
    PORT
      LAYER Metal2 ;
        RECT 34.840 0.000 35.240 0.400 ;
    END
  END s_awaddr[34]
  PIN s_awaddr[35]
    DIRECTION OUTPUT ;
    USE SIGNAL ;
    ANTENNADIFFAREA 0.708600 ;
    PORT
      LAYER Metal2 ;
        RECT 68.440 195.295 68.840 195.695 ;
    END
  END s_awaddr[35]
  PIN s_awaddr[36]
    DIRECTION OUTPUT ;
    USE SIGNAL ;
    ANTENNADIFFAREA 0.708600 ;
    PORT
      LAYER Metal3 ;
        RECT 176.575 173.260 176.975 173.660 ;
    END
  END s_awaddr[36]
  PIN s_awaddr[37]
    DIRECTION OUTPUT ;
    USE SIGNAL ;
    ANTENNADIFFAREA 0.708600 ;
    PORT
      LAYER Metal2 ;
        RECT 119.320 0.000 119.720 0.400 ;
    END
  END s_awaddr[37]
  PIN s_awaddr[38]
    DIRECTION OUTPUT ;
    USE SIGNAL ;
    ANTENNADIFFAREA 0.708600 ;
    PORT
      LAYER Metal2 ;
        RECT 108.760 0.000 109.160 0.400 ;
    END
  END s_awaddr[38]
  PIN s_awaddr[39]
    DIRECTION OUTPUT ;
    USE SIGNAL ;
    ANTENNADIFFAREA 0.708600 ;
    PORT
      LAYER Metal3 ;
        RECT 176.575 181.660 176.975 182.060 ;
    END
  END s_awaddr[39]
  PIN s_awaddr[3]
    DIRECTION OUTPUT ;
    USE SIGNAL ;
    ANTENNADIFFAREA 0.708600 ;
    PORT
      LAYER Metal2 ;
        RECT 65.560 195.295 65.960 195.695 ;
    END
  END s_awaddr[3]
  PIN s_awaddr[40]
    DIRECTION OUTPUT ;
    USE SIGNAL ;
    ANTENNADIFFAREA 0.708600 ;
    PORT
      LAYER Metal3 ;
        RECT 0.000 12.820 0.400 13.220 ;
    END
  END s_awaddr[40]
  PIN s_awaddr[41]
    DIRECTION OUTPUT ;
    USE SIGNAL ;
    ANTENNADIFFAREA 0.708600 ;
    PORT
      LAYER Metal2 ;
        RECT 143.320 195.295 143.720 195.695 ;
    END
  END s_awaddr[41]
  PIN s_awaddr[42]
    DIRECTION OUTPUT ;
    USE SIGNAL ;
    ANTENNADIFFAREA 0.708600 ;
    PORT
      LAYER Metal2 ;
        RECT 77.080 195.295 77.480 195.695 ;
    END
  END s_awaddr[42]
  PIN s_awaddr[43]
    DIRECTION OUTPUT ;
    USE SIGNAL ;
    ANTENNADIFFAREA 0.708600 ;
    PORT
      LAYER Metal3 ;
        RECT 176.575 185.020 176.975 185.420 ;
    END
  END s_awaddr[43]
  PIN s_awaddr[44]
    DIRECTION OUTPUT ;
    USE SIGNAL ;
    ANTENNADIFFAREA 0.708600 ;
    PORT
      LAYER Metal3 ;
        RECT 0.000 57.340 0.400 57.740 ;
    END
  END s_awaddr[44]
  PIN s_awaddr[45]
    DIRECTION OUTPUT ;
    USE SIGNAL ;
    ANTENNADIFFAREA 0.708600 ;
    PORT
      LAYER Metal3 ;
        RECT 0.000 107.740 0.400 108.140 ;
    END
  END s_awaddr[45]
  PIN s_awaddr[46]
    DIRECTION OUTPUT ;
    USE SIGNAL ;
    ANTENNADIFFAREA 0.708600 ;
    PORT
      LAYER Metal3 ;
        RECT 0.000 95.140 0.400 95.540 ;
    END
  END s_awaddr[46]
  PIN s_awaddr[47]
    DIRECTION OUTPUT ;
    USE SIGNAL ;
    ANTENNADIFFAREA 0.708600 ;
    PORT
      LAYER Metal3 ;
        RECT 0.000 69.100 0.400 69.500 ;
    END
  END s_awaddr[47]
  PIN s_awaddr[48]
    DIRECTION OUTPUT ;
    USE SIGNAL ;
    ANTENNADIFFAREA 0.708600 ;
    PORT
      LAYER Metal3 ;
        RECT 0.000 179.140 0.400 179.540 ;
    END
  END s_awaddr[48]
  PIN s_awaddr[49]
    DIRECTION OUTPUT ;
    USE SIGNAL ;
    ANTENNADIFFAREA 0.708600 ;
    PORT
      LAYER Metal3 ;
        RECT 0.000 175.780 0.400 176.180 ;
    END
  END s_awaddr[49]
  PIN s_awaddr[4]
    DIRECTION OUTPUT ;
    USE SIGNAL ;
    ANTENNADIFFAREA 0.708600 ;
    PORT
      LAYER Metal3 ;
        RECT 176.575 189.220 176.975 189.620 ;
    END
  END s_awaddr[4]
  PIN s_awaddr[50]
    DIRECTION OUTPUT ;
    USE SIGNAL ;
    ANTENNADIFFAREA 0.708600 ;
    PORT
      LAYER Metal3 ;
        RECT 0.000 154.780 0.400 155.180 ;
    END
  END s_awaddr[50]
  PIN s_awaddr[51]
    DIRECTION OUTPUT ;
    USE SIGNAL ;
    ANTENNADIFFAREA 0.708600 ;
    PORT
      LAYER Metal3 ;
        RECT 0.000 148.900 0.400 149.300 ;
    END
  END s_awaddr[51]
  PIN s_awaddr[52]
    DIRECTION OUTPUT ;
    USE SIGNAL ;
    ANTENNADIFFAREA 0.708600 ;
    PORT
      LAYER Metal3 ;
        RECT 0.000 30.460 0.400 30.860 ;
    END
  END s_awaddr[52]
  PIN s_awaddr[53]
    DIRECTION OUTPUT ;
    USE SIGNAL ;
    ANTENNADIFFAREA 0.708600 ;
    PORT
      LAYER Metal3 ;
        RECT 0.000 52.300 0.400 52.700 ;
    END
  END s_awaddr[53]
  PIN s_awaddr[54]
    DIRECTION OUTPUT ;
    USE SIGNAL ;
    ANTENNADIFFAREA 0.708600 ;
    PORT
      LAYER Metal3 ;
        RECT 0.000 65.740 0.400 66.140 ;
    END
  END s_awaddr[54]
  PIN s_awaddr[55]
    DIRECTION OUTPUT ;
    USE SIGNAL ;
    ANTENNADIFFAREA 0.708600 ;
    PORT
      LAYER Metal3 ;
        RECT 0.000 41.380 0.400 41.780 ;
    END
  END s_awaddr[55]
  PIN s_awaddr[56]
    DIRECTION OUTPUT ;
    USE SIGNAL ;
    ANTENNADIFFAREA 0.708600 ;
    PORT
      LAYER Metal3 ;
        RECT 0.000 26.260 0.400 26.660 ;
    END
  END s_awaddr[56]
  PIN s_awaddr[57]
    DIRECTION OUTPUT ;
    USE SIGNAL ;
    ANTENNADIFFAREA 0.708600 ;
    PORT
      LAYER Metal3 ;
        RECT 0.000 59.860 0.400 60.260 ;
    END
  END s_awaddr[57]
  PIN s_awaddr[58]
    DIRECTION OUTPUT ;
    USE SIGNAL ;
    ANTENNADIFFAREA 0.708600 ;
    PORT
      LAYER Metal3 ;
        RECT 0.000 42.220 0.400 42.620 ;
    END
  END s_awaddr[58]
  PIN s_awaddr[59]
    DIRECTION OUTPUT ;
    USE SIGNAL ;
    ANTENNADIFFAREA 0.708600 ;
    PORT
      LAYER Metal3 ;
        RECT 0.000 72.460 0.400 72.860 ;
    END
  END s_awaddr[59]
  PIN s_awaddr[5]
    DIRECTION OUTPUT ;
    USE SIGNAL ;
    ANTENNADIFFAREA 0.708600 ;
    PORT
      LAYER Metal2 ;
        RECT 117.400 0.000 117.800 0.400 ;
    END
  END s_awaddr[5]
  PIN s_awaddr[60]
    DIRECTION OUTPUT ;
    USE SIGNAL ;
    ANTENNADIFFAREA 0.708600 ;
    PORT
      LAYER Metal3 ;
        RECT 0.000 164.860 0.400 165.260 ;
    END
  END s_awaddr[60]
  PIN s_awaddr[61]
    DIRECTION OUTPUT ;
    USE SIGNAL ;
    ANTENNADIFFAREA 0.708600 ;
    PORT
      LAYER Metal3 ;
        RECT 0.000 153.940 0.400 154.340 ;
    END
  END s_awaddr[61]
  PIN s_awaddr[62]
    DIRECTION OUTPUT ;
    USE SIGNAL ;
    ANTENNADIFFAREA 0.708600 ;
    PORT
      LAYER Metal3 ;
        RECT 0.000 140.500 0.400 140.900 ;
    END
  END s_awaddr[62]
  PIN s_awaddr[63]
    DIRECTION OUTPUT ;
    USE SIGNAL ;
    ANTENNADIFFAREA 0.708600 ;
    PORT
      LAYER Metal3 ;
        RECT 0.000 143.860 0.400 144.260 ;
    END
  END s_awaddr[63]
  PIN s_awaddr[64]
    DIRECTION OUTPUT ;
    USE SIGNAL ;
    ANTENNADIFFAREA 0.708600 ;
    PORT
      LAYER Metal3 ;
        RECT 0.000 11.140 0.400 11.540 ;
    END
  END s_awaddr[64]
  PIN s_awaddr[65]
    DIRECTION OUTPUT ;
    USE SIGNAL ;
    ANTENNADIFFAREA 0.708600 ;
    PORT
      LAYER Metal2 ;
        RECT 127.960 0.000 128.360 0.400 ;
    END
  END s_awaddr[65]
  PIN s_awaddr[66]
    DIRECTION OUTPUT ;
    USE SIGNAL ;
    ANTENNADIFFAREA 0.708600 ;
    PORT
      LAYER Metal2 ;
        RECT 33.880 0.000 34.280 0.400 ;
    END
  END s_awaddr[66]
  PIN s_awaddr[67]
    DIRECTION OUTPUT ;
    USE SIGNAL ;
    ANTENNADIFFAREA 0.708600 ;
    PORT
      LAYER Metal2 ;
        RECT 55.000 195.295 55.400 195.695 ;
    END
  END s_awaddr[67]
  PIN s_awaddr[68]
    DIRECTION OUTPUT ;
    USE SIGNAL ;
    ANTENNADIFFAREA 0.708600 ;
    PORT
      LAYER Metal3 ;
        RECT 176.575 185.860 176.975 186.260 ;
    END
  END s_awaddr[68]
  PIN s_awaddr[69]
    DIRECTION OUTPUT ;
    USE SIGNAL ;
    ANTENNADIFFAREA 0.708600 ;
    PORT
      LAYER Metal2 ;
        RECT 142.360 0.000 142.760 0.400 ;
    END
  END s_awaddr[69]
  PIN s_awaddr[6]
    DIRECTION OUTPUT ;
    USE SIGNAL ;
    ANTENNADIFFAREA 0.708600 ;
    PORT
      LAYER Metal2 ;
        RECT 104.920 0.000 105.320 0.400 ;
    END
  END s_awaddr[6]
  PIN s_awaddr[70]
    DIRECTION OUTPUT ;
    USE SIGNAL ;
    ANTENNADIFFAREA 0.708600 ;
    PORT
      LAYER Metal2 ;
        RECT 109.720 0.000 110.120 0.400 ;
    END
  END s_awaddr[70]
  PIN s_awaddr[71]
    DIRECTION OUTPUT ;
    USE SIGNAL ;
    ANTENNADIFFAREA 0.708600 ;
    PORT
      LAYER Metal3 ;
        RECT 176.575 179.140 176.975 179.540 ;
    END
  END s_awaddr[71]
  PIN s_awaddr[72]
    DIRECTION OUTPUT ;
    USE SIGNAL ;
    ANTENNADIFFAREA 0.708600 ;
    PORT
      LAYER Metal2 ;
        RECT 31.960 0.000 32.360 0.400 ;
    END
  END s_awaddr[72]
  PIN s_awaddr[73]
    DIRECTION OUTPUT ;
    USE SIGNAL ;
    ANTENNADIFFAREA 0.708600 ;
    PORT
      LAYER Metal2 ;
        RECT 147.160 195.295 147.560 195.695 ;
    END
  END s_awaddr[73]
  PIN s_awaddr[74]
    DIRECTION OUTPUT ;
    USE SIGNAL ;
    ANTENNADIFFAREA 0.708600 ;
    PORT
      LAYER Metal2 ;
        RECT 73.240 195.295 73.640 195.695 ;
    END
  END s_awaddr[74]
  PIN s_awaddr[75]
    DIRECTION OUTPUT ;
    USE SIGNAL ;
    ANTENNADIFFAREA 0.708600 ;
    PORT
      LAYER Metal3 ;
        RECT 176.575 183.340 176.975 183.740 ;
    END
  END s_awaddr[75]
  PIN s_awaddr[76]
    DIRECTION OUTPUT ;
    USE SIGNAL ;
    ANTENNADIFFAREA 0.708600 ;
    PORT
      LAYER Metal3 ;
        RECT 0.000 74.980 0.400 75.380 ;
    END
  END s_awaddr[76]
  PIN s_awaddr[77]
    DIRECTION OUTPUT ;
    USE SIGNAL ;
    ANTENNADIFFAREA 0.708600 ;
    PORT
      LAYER Metal3 ;
        RECT 0.000 173.260 0.400 173.660 ;
    END
  END s_awaddr[77]
  PIN s_awaddr[78]
    DIRECTION OUTPUT ;
    USE SIGNAL ;
    ANTENNADIFFAREA 0.708600 ;
    PORT
      LAYER Metal3 ;
        RECT 0.000 95.980 0.400 96.380 ;
    END
  END s_awaddr[78]
  PIN s_awaddr[79]
    DIRECTION OUTPUT ;
    USE SIGNAL ;
    ANTENNADIFFAREA 0.708600 ;
    PORT
      LAYER Metal3 ;
        RECT 0.000 91.780 0.400 92.180 ;
    END
  END s_awaddr[79]
  PIN s_awaddr[7]
    DIRECTION OUTPUT ;
    USE SIGNAL ;
    ANTENNADIFFAREA 0.708600 ;
    PORT
      LAYER Metal3 ;
        RECT 176.575 184.180 176.975 184.580 ;
    END
  END s_awaddr[7]
  PIN s_awaddr[80]
    DIRECTION OUTPUT ;
    USE SIGNAL ;
    ANTENNADIFFAREA 0.708600 ;
    PORT
      LAYER Metal3 ;
        RECT 0.000 190.060 0.400 190.460 ;
    END
  END s_awaddr[80]
  PIN s_awaddr[81]
    DIRECTION OUTPUT ;
    USE SIGNAL ;
    ANTENNADIFFAREA 0.708600 ;
    PORT
      LAYER Metal3 ;
        RECT 0.000 138.820 0.400 139.220 ;
    END
  END s_awaddr[81]
  PIN s_awaddr[82]
    DIRECTION OUTPUT ;
    USE SIGNAL ;
    ANTENNADIFFAREA 0.708600 ;
    PORT
      LAYER Metal3 ;
        RECT 0.000 155.620 0.400 156.020 ;
    END
  END s_awaddr[82]
  PIN s_awaddr[83]
    DIRECTION OUTPUT ;
    USE SIGNAL ;
    ANTENNADIFFAREA 0.708600 ;
    PORT
      LAYER Metal3 ;
        RECT 0.000 149.740 0.400 150.140 ;
    END
  END s_awaddr[83]
  PIN s_awaddr[84]
    DIRECTION OUTPUT ;
    USE SIGNAL ;
    ANTENNADIFFAREA 0.708600 ;
    PORT
      LAYER Metal3 ;
        RECT 0.000 33.820 0.400 34.220 ;
    END
  END s_awaddr[84]
  PIN s_awaddr[85]
    DIRECTION OUTPUT ;
    USE SIGNAL ;
    ANTENNADIFFAREA 0.708600 ;
    PORT
      LAYER Metal3 ;
        RECT 0.000 28.780 0.400 29.180 ;
    END
  END s_awaddr[85]
  PIN s_awaddr[86]
    DIRECTION OUTPUT ;
    USE SIGNAL ;
    ANTENNADIFFAREA 0.708600 ;
    PORT
      LAYER Metal3 ;
        RECT 0.000 60.700 0.400 61.100 ;
    END
  END s_awaddr[86]
  PIN s_awaddr[87]
    DIRECTION OUTPUT ;
    USE SIGNAL ;
    ANTENNADIFFAREA 0.708600 ;
    PORT
      LAYER Metal3 ;
        RECT 0.000 77.500 0.400 77.900 ;
    END
  END s_awaddr[87]
  PIN s_awaddr[88]
    DIRECTION OUTPUT ;
    USE SIGNAL ;
    ANTENNADIFFAREA 0.708600 ;
    PORT
      LAYER Metal3 ;
        RECT 0.000 54.820 0.400 55.220 ;
    END
  END s_awaddr[88]
  PIN s_awaddr[89]
    DIRECTION OUTPUT ;
    USE SIGNAL ;
    ANTENNADIFFAREA 0.708600 ;
    PORT
      LAYER Metal3 ;
        RECT 0.000 27.940 0.400 28.340 ;
    END
  END s_awaddr[89]
  PIN s_awaddr[8]
    DIRECTION OUTPUT ;
    USE SIGNAL ;
    ANTENNADIFFAREA 0.708600 ;
    PORT
      LAYER Metal2 ;
        RECT 32.920 0.000 33.320 0.400 ;
    END
  END s_awaddr[8]
  PIN s_awaddr[90]
    DIRECTION OUTPUT ;
    USE SIGNAL ;
    ANTENNADIFFAREA 0.708600 ;
    PORT
      LAYER Metal3 ;
        RECT 0.000 83.380 0.400 83.780 ;
    END
  END s_awaddr[90]
  PIN s_awaddr[91]
    DIRECTION OUTPUT ;
    USE SIGNAL ;
    ANTENNADIFFAREA 0.708600 ;
    PORT
      LAYER Metal3 ;
        RECT 0.000 67.420 0.400 67.820 ;
    END
  END s_awaddr[91]
  PIN s_awaddr[92]
    DIRECTION OUTPUT ;
    USE SIGNAL ;
    ANTENNADIFFAREA 0.708600 ;
    PORT
      LAYER Metal3 ;
        RECT 0.000 171.580 0.400 171.980 ;
    END
  END s_awaddr[92]
  PIN s_awaddr[93]
    DIRECTION OUTPUT ;
    USE SIGNAL ;
    ANTENNADIFFAREA 0.708600 ;
    PORT
      LAYER Metal3 ;
        RECT 0.000 152.260 0.400 152.660 ;
    END
  END s_awaddr[93]
  PIN s_awaddr[94]
    DIRECTION OUTPUT ;
    USE SIGNAL ;
    ANTENNADIFFAREA 0.708600 ;
    PORT
      LAYER Metal3 ;
        RECT 0.000 190.900 0.400 191.300 ;
    END
  END s_awaddr[94]
  PIN s_awaddr[95]
    DIRECTION OUTPUT ;
    USE SIGNAL ;
    ANTENNADIFFAREA 0.708600 ;
    PORT
      LAYER Metal3 ;
        RECT 0.000 142.180 0.400 142.580 ;
    END
  END s_awaddr[95]
  PIN s_awaddr[96]
    DIRECTION OUTPUT ;
    USE SIGNAL ;
    ANTENNADIFFAREA 0.708600 ;
    PORT
      LAYER Metal2 ;
        RECT 47.320 0.000 47.720 0.400 ;
    END
  END s_awaddr[96]
  PIN s_awaddr[97]
    DIRECTION OUTPUT ;
    USE SIGNAL ;
    ANTENNADIFFAREA 0.708600 ;
    PORT
      LAYER Metal2 ;
        RECT 122.200 0.000 122.600 0.400 ;
    END
  END s_awaddr[97]
  PIN s_awaddr[98]
    DIRECTION OUTPUT ;
    USE SIGNAL ;
    ANTENNADIFFAREA 0.708600 ;
    PORT
      LAYER Metal2 ;
        RECT 31.000 0.000 31.400 0.400 ;
    END
  END s_awaddr[98]
  PIN s_awaddr[99]
    DIRECTION OUTPUT ;
    USE SIGNAL ;
    ANTENNADIFFAREA 0.708600 ;
    PORT
      LAYER Metal2 ;
        RECT 66.520 195.295 66.920 195.695 ;
    END
  END s_awaddr[99]
  PIN s_awaddr[9]
    DIRECTION OUTPUT ;
    USE SIGNAL ;
    ANTENNADIFFAREA 0.708600 ;
    PORT
      LAYER Metal2 ;
        RECT 148.120 195.295 148.520 195.695 ;
    END
  END s_awaddr[9]
  PIN s_awprot[0]
    DIRECTION OUTPUT ;
    USE SIGNAL ;
    ANTENNADIFFAREA 0.708600 ;
    PORT
      LAYER Metal3 ;
        RECT 176.575 125.380 176.975 125.780 ;
    END
  END s_awprot[0]
  PIN s_awprot[10]
    DIRECTION OUTPUT ;
    USE SIGNAL ;
    ANTENNADIFFAREA 0.708600 ;
    PORT
      LAYER Metal3 ;
        RECT 0.000 66.580 0.400 66.980 ;
    END
  END s_awprot[10]
  PIN s_awprot[11]
    DIRECTION OUTPUT ;
    USE SIGNAL ;
    ANTENNADIFFAREA 0.708600 ;
    PORT
      LAYER Metal2 ;
        RECT 57.880 0.000 58.280 0.400 ;
    END
  END s_awprot[11]
  PIN s_awprot[1]
    DIRECTION OUTPUT ;
    USE SIGNAL ;
    ANTENNADIFFAREA 0.708600 ;
    PORT
      LAYER Metal3 ;
        RECT 0.000 61.540 0.400 61.940 ;
    END
  END s_awprot[1]
  PIN s_awprot[2]
    DIRECTION OUTPUT ;
    USE SIGNAL ;
    ANTENNADIFFAREA 0.708600 ;
    PORT
      LAYER Metal2 ;
        RECT 56.920 0.000 57.320 0.400 ;
    END
  END s_awprot[2]
  PIN s_awprot[3]
    DIRECTION OUTPUT ;
    USE SIGNAL ;
    ANTENNADIFFAREA 0.708600 ;
    PORT
      LAYER Metal3 ;
        RECT 176.575 153.940 176.975 154.340 ;
    END
  END s_awprot[3]
  PIN s_awprot[4]
    DIRECTION OUTPUT ;
    USE SIGNAL ;
    ANTENNADIFFAREA 0.708600 ;
    PORT
      LAYER Metal3 ;
        RECT 0.000 53.980 0.400 54.380 ;
    END
  END s_awprot[4]
  PIN s_awprot[5]
    DIRECTION OUTPUT ;
    USE SIGNAL ;
    ANTENNADIFFAREA 0.708600 ;
    PORT
      LAYER Metal2 ;
        RECT 55.960 0.000 56.360 0.400 ;
    END
  END s_awprot[5]
  PIN s_awprot[6]
    DIRECTION OUTPUT ;
    USE SIGNAL ;
    ANTENNADIFFAREA 0.708600 ;
    PORT
      LAYER Metal3 ;
        RECT 176.575 122.860 176.975 123.260 ;
    END
  END s_awprot[6]
  PIN s_awprot[7]
    DIRECTION OUTPUT ;
    USE SIGNAL ;
    ANTENNADIFFAREA 0.708600 ;
    PORT
      LAYER Metal3 ;
        RECT 0.000 59.020 0.400 59.420 ;
    END
  END s_awprot[7]
  PIN s_awprot[8]
    DIRECTION OUTPUT ;
    USE SIGNAL ;
    ANTENNADIFFAREA 0.708600 ;
    PORT
      LAYER Metal2 ;
        RECT 55.000 0.000 55.400 0.400 ;
    END
  END s_awprot[8]
  PIN s_awprot[9]
    DIRECTION OUTPUT ;
    USE SIGNAL ;
    ANTENNADIFFAREA 0.708600 ;
    PORT
      LAYER Metal3 ;
        RECT 176.575 122.020 176.975 122.420 ;
    END
  END s_awprot[9]
  PIN s_awready[0]
    DIRECTION INPUT ;
    USE SIGNAL ;
    ANTENNAGATEAREA 0.180700 ;
    PORT
      LAYER Metal3 ;
        RECT 0.000 133.780 0.400 134.180 ;
    END
  END s_awready[0]
  PIN s_awready[1]
    DIRECTION INPUT ;
    USE SIGNAL ;
    ANTENNAGATEAREA 0.180700 ;
    PORT
      LAYER Metal3 ;
        RECT 0.000 134.620 0.400 135.020 ;
    END
  END s_awready[1]
  PIN s_awready[2]
    DIRECTION INPUT ;
    USE SIGNAL ;
    ANTENNAGATEAREA 0.180700 ;
    PORT
      LAYER Metal3 ;
        RECT 0.000 121.180 0.400 121.580 ;
    END
  END s_awready[2]
  PIN s_awready[3]
    DIRECTION INPUT ;
    USE SIGNAL ;
    ANTENNAGATEAREA 0.180700 ;
    PORT
      LAYER Metal3 ;
        RECT 0.000 118.660 0.400 119.060 ;
    END
  END s_awready[3]
  PIN s_awvalid[0]
    DIRECTION OUTPUT ;
    USE SIGNAL ;
    ANTENNADIFFAREA 0.708600 ;
    PORT
      LAYER Metal3 ;
        RECT 0.000 110.260 0.400 110.660 ;
    END
  END s_awvalid[0]
  PIN s_awvalid[1]
    DIRECTION OUTPUT ;
    USE SIGNAL ;
    ANTENNADIFFAREA 0.708600 ;
    PORT
      LAYER Metal3 ;
        RECT 0.000 99.340 0.400 99.740 ;
    END
  END s_awvalid[1]
  PIN s_awvalid[2]
    DIRECTION OUTPUT ;
    USE SIGNAL ;
    ANTENNADIFFAREA 0.708600 ;
    PORT
      LAYER Metal3 ;
        RECT 0.000 101.020 0.400 101.420 ;
    END
  END s_awvalid[2]
  PIN s_awvalid[3]
    DIRECTION OUTPUT ;
    USE SIGNAL ;
    ANTENNADIFFAREA 0.708600 ;
    PORT
      LAYER Metal3 ;
        RECT 0.000 176.620 0.400 177.020 ;
    END
  END s_awvalid[3]
  PIN s_bready[0]
    DIRECTION OUTPUT ;
    USE SIGNAL ;
    ANTENNADIFFAREA 0.708600 ;
    PORT
      LAYER Metal3 ;
        RECT 0.000 111.100 0.400 111.500 ;
    END
  END s_bready[0]
  PIN s_bready[1]
    DIRECTION OUTPUT ;
    USE SIGNAL ;
    ANTENNADIFFAREA 0.708600 ;
    PORT
      LAYER Metal3 ;
        RECT 0.000 100.180 0.400 100.580 ;
    END
  END s_bready[1]
  PIN s_bready[2]
    DIRECTION OUTPUT ;
    USE SIGNAL ;
    ANTENNADIFFAREA 0.708600 ;
    PORT
      LAYER Metal3 ;
        RECT 0.000 101.860 0.400 102.260 ;
    END
  END s_bready[2]
  PIN s_bready[3]
    DIRECTION OUTPUT ;
    USE SIGNAL ;
    ANTENNADIFFAREA 0.708600 ;
    PORT
      LAYER Metal3 ;
        RECT 0.000 108.580 0.400 108.980 ;
    END
  END s_bready[3]
  PIN s_bresp[0]
    DIRECTION INPUT ;
    USE SIGNAL ;
    ANTENNAGATEAREA 0.180700 ;
    PORT
      LAYER Metal3 ;
        RECT 0.000 132.940 0.400 133.340 ;
    END
  END s_bresp[0]
  PIN s_bresp[1]
    DIRECTION INPUT ;
    USE SIGNAL ;
    ANTENNAGATEAREA 0.180700 ;
    PORT
      LAYER Metal3 ;
        RECT 0.000 128.740 0.400 129.140 ;
    END
  END s_bresp[1]
  PIN s_bresp[2]
    DIRECTION INPUT ;
    USE SIGNAL ;
    ANTENNAGATEAREA 0.180700 ;
    PORT
      LAYER Metal3 ;
        RECT 0.000 112.780 0.400 113.180 ;
    END
  END s_bresp[2]
  PIN s_bresp[3]
    DIRECTION INPUT ;
    USE SIGNAL ;
    ANTENNAGATEAREA 0.180700 ;
    PORT
      LAYER Metal3 ;
        RECT 0.000 129.580 0.400 129.980 ;
    END
  END s_bresp[3]
  PIN s_bresp[4]
    DIRECTION INPUT ;
    USE SIGNAL ;
    ANTENNAGATEAREA 0.180700 ;
    PORT
      LAYER Metal3 ;
        RECT 0.000 120.340 0.400 120.740 ;
    END
  END s_bresp[4]
  PIN s_bresp[5]
    DIRECTION INPUT ;
    USE SIGNAL ;
    ANTENNAGATEAREA 0.180700 ;
    PORT
      LAYER Metal3 ;
        RECT 0.000 127.900 0.400 128.300 ;
    END
  END s_bresp[5]
  PIN s_bresp[6]
    DIRECTION INPUT ;
    USE SIGNAL ;
    ANTENNAGATEAREA 0.180700 ;
    PORT
      LAYER Metal3 ;
        RECT 0.000 126.220 0.400 126.620 ;
    END
  END s_bresp[6]
  PIN s_bresp[7]
    DIRECTION INPUT ;
    USE SIGNAL ;
    ANTENNAGATEAREA 0.180700 ;
    PORT
      LAYER Metal3 ;
        RECT 0.000 127.060 0.400 127.460 ;
    END
  END s_bresp[7]
  PIN s_bvalid[0]
    DIRECTION INPUT ;
    USE SIGNAL ;
    ANTENNAGATEAREA 0.180700 ;
    PORT
      LAYER Metal3 ;
        RECT 0.000 131.260 0.400 131.660 ;
    END
  END s_bvalid[0]
  PIN s_bvalid[1]
    DIRECTION INPUT ;
    USE SIGNAL ;
    ANTENNAGATEAREA 0.180700 ;
    PORT
      LAYER Metal3 ;
        RECT 0.000 111.940 0.400 112.340 ;
    END
  END s_bvalid[1]
  PIN s_bvalid[2]
    DIRECTION INPUT ;
    USE SIGNAL ;
    ANTENNAGATEAREA 0.180700 ;
    PORT
      LAYER Metal3 ;
        RECT 0.000 117.820 0.400 118.220 ;
    END
  END s_bvalid[2]
  PIN s_bvalid[3]
    DIRECTION INPUT ;
    USE SIGNAL ;
    ANTENNAGATEAREA 0.180700 ;
    PORT
      LAYER Metal3 ;
        RECT 0.000 116.980 0.400 117.380 ;
    END
  END s_bvalid[3]
  PIN s_rdata[0]
    DIRECTION INPUT ;
    USE SIGNAL ;
    ANTENNAGATEAREA 0.180700 ;
    PORT
      LAYER Metal2 ;
        RECT 81.880 195.295 82.280 195.695 ;
    END
  END s_rdata[0]
  PIN s_rdata[100]
    DIRECTION INPUT ;
    USE SIGNAL ;
    ANTENNAGATEAREA 0.180700 ;
    PORT
      LAYER Metal3 ;
        RECT 176.575 134.620 176.975 135.020 ;
    END
  END s_rdata[100]
  PIN s_rdata[101]
    DIRECTION INPUT ;
    USE SIGNAL ;
    ANTENNAGATEAREA 0.180700 ;
    PORT
      LAYER Metal2 ;
        RECT 88.600 195.295 89.000 195.695 ;
    END
  END s_rdata[101]
  PIN s_rdata[102]
    DIRECTION INPUT ;
    USE SIGNAL ;
    ANTENNAGATEAREA 0.180700 ;
    PORT
      LAYER Metal3 ;
        RECT 0.000 106.900 0.400 107.300 ;
    END
  END s_rdata[102]
  PIN s_rdata[103]
    DIRECTION INPUT ;
    USE SIGNAL ;
    ANTENNAGATEAREA 0.180700 ;
    PORT
      LAYER Metal2 ;
        RECT 12.760 0.000 13.160 0.400 ;
    END
  END s_rdata[103]
  PIN s_rdata[104]
    DIRECTION INPUT ;
    USE SIGNAL ;
    ANTENNAGATEAREA 0.180700 ;
    PORT
      LAYER Metal2 ;
        RECT 95.320 0.000 95.720 0.400 ;
    END
  END s_rdata[104]
  PIN s_rdata[105]
    DIRECTION INPUT ;
    USE SIGNAL ;
    ANTENNAGATEAREA 0.180700 ;
    PORT
      LAYER Metal3 ;
        RECT 176.575 78.340 176.975 78.740 ;
    END
  END s_rdata[105]
  PIN s_rdata[106]
    DIRECTION INPUT ;
    USE SIGNAL ;
    ANTENNAGATEAREA 0.180700 ;
    PORT
      LAYER Metal2 ;
        RECT 37.720 0.000 38.120 0.400 ;
    END
  END s_rdata[106]
  PIN s_rdata[107]
    DIRECTION INPUT ;
    USE SIGNAL ;
    ANTENNAGATEAREA 0.180700 ;
    PORT
      LAYER Metal3 ;
        RECT 0.000 53.140 0.400 53.540 ;
    END
  END s_rdata[107]
  PIN s_rdata[108]
    DIRECTION INPUT ;
    USE SIGNAL ;
    ANTENNAGATEAREA 0.180700 ;
    PORT
      LAYER Metal3 ;
        RECT 176.575 126.220 176.975 126.620 ;
    END
  END s_rdata[108]
  PIN s_rdata[109]
    DIRECTION INPUT ;
    USE SIGNAL ;
    ANTENNAGATEAREA 0.180700 ;
    PORT
      LAYER Metal3 ;
        RECT 0.000 119.500 0.400 119.900 ;
    END
  END s_rdata[109]
  PIN s_rdata[10]
    DIRECTION INPUT ;
    USE SIGNAL ;
    ANTENNAGATEAREA 0.180700 ;
    PORT
      LAYER Metal2 ;
        RECT 70.360 0.000 70.760 0.400 ;
    END
  END s_rdata[10]
  PIN s_rdata[110]
    DIRECTION INPUT ;
    USE SIGNAL ;
    ANTENNAGATEAREA 0.180700 ;
    PORT
      LAYER Metal2 ;
        RECT 64.600 0.000 65.000 0.400 ;
    END
  END s_rdata[110]
  PIN s_rdata[111]
    DIRECTION INPUT ;
    USE SIGNAL ;
    ANTENNAGATEAREA 0.180700 ;
    PORT
      LAYER Metal3 ;
        RECT 176.575 85.060 176.975 85.460 ;
    END
  END s_rdata[111]
  PIN s_rdata[112]
    DIRECTION INPUT ;
    USE SIGNAL ;
    ANTENNAGATEAREA 0.180700 ;
    PORT
      LAYER Metal2 ;
        RECT 141.400 0.000 141.800 0.400 ;
    END
  END s_rdata[112]
  PIN s_rdata[113]
    DIRECTION INPUT ;
    USE SIGNAL ;
    ANTENNAGATEAREA 0.180700 ;
    PORT
      LAYER Metal2 ;
        RECT 151.960 0.000 152.360 0.400 ;
    END
  END s_rdata[113]
  PIN s_rdata[114]
    DIRECTION INPUT ;
    USE SIGNAL ;
    ANTENNAGATEAREA 0.180700 ;
    PORT
      LAYER Metal2 ;
        RECT 78.040 195.295 78.440 195.695 ;
    END
  END s_rdata[114]
  PIN s_rdata[115]
    DIRECTION INPUT ;
    USE SIGNAL ;
    ANTENNAGATEAREA 0.180700 ;
    PORT
      LAYER Metal3 ;
        RECT 0.000 96.820 0.400 97.220 ;
    END
  END s_rdata[115]
  PIN s_rdata[116]
    DIRECTION INPUT ;
    USE SIGNAL ;
    ANTENNAGATEAREA 0.180700 ;
    PORT
      LAYER Metal2 ;
        RECT 151.000 195.295 151.400 195.695 ;
    END
  END s_rdata[116]
  PIN s_rdata[117]
    DIRECTION INPUT ;
    USE SIGNAL ;
    ANTENNAGATEAREA 0.180700 ;
    PORT
      LAYER Metal2 ;
        RECT 69.400 195.295 69.800 195.695 ;
    END
  END s_rdata[117]
  PIN s_rdata[118]
    DIRECTION INPUT ;
    USE SIGNAL ;
    ANTENNAGATEAREA 0.180700 ;
    PORT
      LAYER Metal3 ;
        RECT 176.575 91.780 176.975 92.180 ;
    END
  END s_rdata[118]
  PIN s_rdata[119]
    DIRECTION INPUT ;
    USE SIGNAL ;
    ANTENNAGATEAREA 0.180700 ;
    PORT
      LAYER Metal2 ;
        RECT 118.360 195.295 118.760 195.695 ;
    END
  END s_rdata[119]
  PIN s_rdata[11]
    DIRECTION INPUT ;
    USE SIGNAL ;
    ANTENNAGATEAREA 0.180700 ;
    PORT
      LAYER Metal2 ;
        RECT 72.280 0.000 72.680 0.400 ;
    END
  END s_rdata[11]
  PIN s_rdata[120]
    DIRECTION INPUT ;
    USE SIGNAL ;
    ANTENNAGATEAREA 0.180700 ;
    PORT
      LAYER Metal3 ;
        RECT 176.575 164.020 176.975 164.420 ;
    END
  END s_rdata[120]
  PIN s_rdata[121]
    DIRECTION INPUT ;
    USE SIGNAL ;
    ANTENNAGATEAREA 0.180700 ;
    PORT
      LAYER Metal3 ;
        RECT 176.575 154.780 176.975 155.180 ;
    END
  END s_rdata[121]
  PIN s_rdata[122]
    DIRECTION INPUT ;
    USE SIGNAL ;
    ANTENNAGATEAREA 0.180700 ;
    PORT
      LAYER Metal3 ;
        RECT 176.575 142.180 176.975 142.580 ;
    END
  END s_rdata[122]
  PIN s_rdata[123]
    DIRECTION INPUT ;
    USE SIGNAL ;
    ANTENNAGATEAREA 0.180700 ;
    PORT
      LAYER Metal3 ;
        RECT 176.575 44.740 176.975 45.140 ;
    END
  END s_rdata[123]
  PIN s_rdata[124]
    DIRECTION INPUT ;
    USE SIGNAL ;
    ANTENNAGATEAREA 0.180700 ;
    PORT
      LAYER Metal3 ;
        RECT 176.575 80.860 176.975 81.260 ;
    END
  END s_rdata[124]
  PIN s_rdata[125]
    DIRECTION INPUT ;
    USE SIGNAL ;
    ANTENNAGATEAREA 0.180700 ;
    PORT
      LAYER Metal3 ;
        RECT 176.575 96.820 176.975 97.220 ;
    END
  END s_rdata[125]
  PIN s_rdata[126]
    DIRECTION INPUT ;
    USE SIGNAL ;
    ANTENNAGATEAREA 0.180700 ;
    PORT
      LAYER Metal3 ;
        RECT 176.575 16.180 176.975 16.580 ;
    END
  END s_rdata[126]
  PIN s_rdata[127]
    DIRECTION INPUT ;
    USE SIGNAL ;
    ANTENNAGATEAREA 0.180700 ;
    PORT
      LAYER Metal3 ;
        RECT 176.575 164.860 176.975 165.260 ;
    END
  END s_rdata[127]
  PIN s_rdata[12]
    DIRECTION INPUT ;
    USE SIGNAL ;
    ANTENNAGATEAREA 0.180700 ;
    PORT
      LAYER Metal3 ;
        RECT 176.575 139.660 176.975 140.060 ;
    END
  END s_rdata[12]
  PIN s_rdata[13]
    DIRECTION INPUT ;
    USE SIGNAL ;
    ANTENNAGATEAREA 0.180700 ;
    PORT
      LAYER Metal3 ;
        RECT 0.000 116.140 0.400 116.540 ;
    END
  END s_rdata[13]
  PIN s_rdata[14]
    DIRECTION INPUT ;
    USE SIGNAL ;
    ANTENNAGATEAREA 0.180700 ;
    PORT
      LAYER Metal2 ;
        RECT 25.240 0.000 25.640 0.400 ;
    END
  END s_rdata[14]
  PIN s_rdata[15]
    DIRECTION INPUT ;
    USE SIGNAL ;
    ANTENNAGATEAREA 0.180700 ;
    PORT
      LAYER Metal3 ;
        RECT 176.575 84.220 176.975 84.620 ;
    END
  END s_rdata[15]
  PIN s_rdata[16]
    DIRECTION INPUT ;
    USE SIGNAL ;
    ANTENNAGATEAREA 0.180700 ;
    PORT
      LAYER Metal2 ;
        RECT 159.640 0.000 160.040 0.400 ;
    END
  END s_rdata[16]
  PIN s_rdata[17]
    DIRECTION INPUT ;
    USE SIGNAL ;
    ANTENNAGATEAREA 0.180700 ;
    PORT
      LAYER Metal2 ;
        RECT 94.360 0.000 94.760 0.400 ;
    END
  END s_rdata[17]
  PIN s_rdata[18]
    DIRECTION INPUT ;
    USE SIGNAL ;
    ANTENNAGATEAREA 0.180700 ;
    PORT
      LAYER Metal2 ;
        RECT 87.640 195.295 88.040 195.695 ;
    END
  END s_rdata[18]
  PIN s_rdata[19]
    DIRECTION INPUT ;
    USE SIGNAL ;
    ANTENNAGATEAREA 0.180700 ;
    PORT
      LAYER Metal3 ;
        RECT 0.000 86.740 0.400 87.140 ;
    END
  END s_rdata[19]
  PIN s_rdata[1]
    DIRECTION INPUT ;
    USE SIGNAL ;
    ANTENNAGATEAREA 0.180700 ;
    PORT
      LAYER Metal3 ;
        RECT 176.575 63.220 176.975 63.620 ;
    END
  END s_rdata[1]
  PIN s_rdata[20]
    DIRECTION INPUT ;
    USE SIGNAL ;
    ANTENNAGATEAREA 0.180700 ;
    PORT
      LAYER Metal2 ;
        RECT 152.920 195.295 153.320 195.695 ;
    END
  END s_rdata[20]
  PIN s_rdata[21]
    DIRECTION INPUT ;
    USE SIGNAL ;
    ANTENNAGATEAREA 0.180700 ;
    PORT
      LAYER Metal3 ;
        RECT 0.000 124.540 0.400 124.940 ;
    END
  END s_rdata[21]
  PIN s_rdata[22]
    DIRECTION INPUT ;
    USE SIGNAL ;
    ANTENNAGATEAREA 0.180700 ;
    PORT
      LAYER Metal3 ;
        RECT 176.575 94.300 176.975 94.700 ;
    END
  END s_rdata[22]
  PIN s_rdata[23]
    DIRECTION INPUT ;
    USE SIGNAL ;
    ANTENNAGATEAREA 0.180700 ;
    PORT
      LAYER Metal3 ;
        RECT 176.575 160.660 176.975 161.060 ;
    END
  END s_rdata[23]
  PIN s_rdata[24]
    DIRECTION INPUT ;
    USE SIGNAL ;
    ANTENNAGATEAREA 0.180700 ;
    PORT
      LAYER Metal3 ;
        RECT 176.575 87.580 176.975 87.980 ;
    END
  END s_rdata[24]
  PIN s_rdata[25]
    DIRECTION INPUT ;
    USE SIGNAL ;
    ANTENNAGATEAREA 0.180700 ;
    PORT
      LAYER Metal3 ;
        RECT 176.575 141.340 176.975 141.740 ;
    END
  END s_rdata[25]
  PIN s_rdata[26]
    DIRECTION INPUT ;
    USE SIGNAL ;
    ANTENNAGATEAREA 0.180700 ;
    PORT
      LAYER Metal3 ;
        RECT 176.575 148.900 176.975 149.300 ;
    END
  END s_rdata[26]
  PIN s_rdata[27]
    DIRECTION INPUT ;
    USE SIGNAL ;
    ANTENNAGATEAREA 0.180700 ;
    PORT
      LAYER Metal3 ;
        RECT 176.575 71.620 176.975 72.020 ;
    END
  END s_rdata[27]
  PIN s_rdata[28]
    DIRECTION INPUT ;
    USE SIGNAL ;
    ANTENNAGATEAREA 0.180700 ;
    PORT
      LAYER Metal3 ;
        RECT 176.575 79.180 176.975 79.580 ;
    END
  END s_rdata[28]
  PIN s_rdata[29]
    DIRECTION INPUT ;
    USE SIGNAL ;
    ANTENNAGATEAREA 0.180700 ;
    PORT
      LAYER Metal3 ;
        RECT 176.575 88.420 176.975 88.820 ;
    END
  END s_rdata[29]
  PIN s_rdata[2]
    DIRECTION INPUT ;
    USE SIGNAL ;
    ANTENNAGATEAREA 0.180700 ;
    PORT
      LAYER Metal3 ;
        RECT 0.000 88.420 0.400 88.820 ;
    END
  END s_rdata[2]
  PIN s_rdata[30]
    DIRECTION INPUT ;
    USE SIGNAL ;
    ANTENNAGATEAREA 0.180700 ;
    PORT
      LAYER Metal3 ;
        RECT 176.575 74.140 176.975 74.540 ;
    END
  END s_rdata[30]
  PIN s_rdata[31]
    DIRECTION INPUT ;
    USE SIGNAL ;
    ANTENNAGATEAREA 0.180700 ;
    PORT
      LAYER Metal3 ;
        RECT 176.575 110.260 176.975 110.660 ;
    END
  END s_rdata[31]
  PIN s_rdata[32]
    DIRECTION INPUT ;
    USE SIGNAL ;
    ANTENNAGATEAREA 0.180700 ;
    PORT
      LAYER Metal2 ;
        RECT 67.480 195.295 67.880 195.695 ;
    END
  END s_rdata[32]
  PIN s_rdata[33]
    DIRECTION INPUT ;
    USE SIGNAL ;
    ANTENNAGATEAREA 0.180700 ;
    PORT
      LAYER Metal3 ;
        RECT 176.575 67.420 176.975 67.820 ;
    END
  END s_rdata[33]
  PIN s_rdata[34]
    DIRECTION INPUT ;
    USE SIGNAL ;
    ANTENNAGATEAREA 0.180700 ;
    PORT
      LAYER Metal2 ;
        RECT 78.040 0.000 78.440 0.400 ;
    END
  END s_rdata[34]
  PIN s_rdata[35]
    DIRECTION INPUT ;
    USE SIGNAL ;
    ANTENNAGATEAREA 0.180700 ;
    PORT
      LAYER Metal2 ;
        RECT 110.680 0.000 111.080 0.400 ;
    END
  END s_rdata[35]
  PIN s_rdata[36]
    DIRECTION INPUT ;
    USE SIGNAL ;
    ANTENNAGATEAREA 0.180700 ;
    PORT
      LAYER Metal3 ;
        RECT 176.575 131.260 176.975 131.660 ;
    END
  END s_rdata[36]
  PIN s_rdata[37]
    DIRECTION INPUT ;
    USE SIGNAL ;
    ANTENNAGATEAREA 0.180700 ;
    PORT
      LAYER Metal2 ;
        RECT 92.440 195.295 92.840 195.695 ;
    END
  END s_rdata[37]
  PIN s_rdata[38]
    DIRECTION INPUT ;
    USE SIGNAL ;
    ANTENNAGATEAREA 0.180700 ;
    PORT
      LAYER Metal3 ;
        RECT 0.000 105.220 0.400 105.620 ;
    END
  END s_rdata[38]
  PIN s_rdata[39]
    DIRECTION INPUT ;
    USE SIGNAL ;
    ANTENNAGATEAREA 0.180700 ;
    PORT
      LAYER Metal2 ;
        RECT 83.800 0.000 84.200 0.400 ;
    END
  END s_rdata[39]
  PIN s_rdata[3]
    DIRECTION INPUT ;
    USE SIGNAL ;
    ANTENNAGATEAREA 0.180700 ;
    PORT
      LAYER Metal2 ;
        RECT 113.560 0.000 113.960 0.400 ;
    END
  END s_rdata[3]
  PIN s_rdata[40]
    DIRECTION INPUT ;
    USE SIGNAL ;
    ANTENNAGATEAREA 0.180700 ;
    PORT
      LAYER Metal2 ;
        RECT 84.760 0.000 85.160 0.400 ;
    END
  END s_rdata[40]
  PIN s_rdata[41]
    DIRECTION INPUT ;
    USE SIGNAL ;
    ANTENNAGATEAREA 0.180700 ;
    PORT
      LAYER Metal3 ;
        RECT 176.575 74.980 176.975 75.380 ;
    END
  END s_rdata[41]
  PIN s_rdata[42]
    DIRECTION INPUT ;
    USE SIGNAL ;
    ANTENNAGATEAREA 0.180700 ;
    PORT
      LAYER Metal2 ;
        RECT 18.520 0.000 18.920 0.400 ;
    END
  END s_rdata[42]
  PIN s_rdata[43]
    DIRECTION INPUT ;
    USE SIGNAL ;
    ANTENNAGATEAREA 0.180700 ;
    PORT
      LAYER Metal2 ;
        RECT 77.080 0.000 77.480 0.400 ;
    END
  END s_rdata[43]
  PIN s_rdata[44]
    DIRECTION INPUT ;
    USE SIGNAL ;
    ANTENNAGATEAREA 0.180700 ;
    PORT
      LAYER Metal3 ;
        RECT 176.575 132.100 176.975 132.500 ;
    END
  END s_rdata[44]
  PIN s_rdata[45]
    DIRECTION INPUT ;
    USE SIGNAL ;
    ANTENNAGATEAREA 0.180700 ;
    PORT
      LAYER Metal3 ;
        RECT 0.000 174.940 0.400 175.340 ;
    END
  END s_rdata[45]
  PIN s_rdata[46]
    DIRECTION INPUT ;
    USE SIGNAL ;
    ANTENNAGATEAREA 0.180700 ;
    PORT
      LAYER Metal2 ;
        RECT 74.200 0.000 74.600 0.400 ;
    END
  END s_rdata[46]
  PIN s_rdata[47]
    DIRECTION INPUT ;
    USE SIGNAL ;
    ANTENNAGATEAREA 0.180700 ;
    PORT
      LAYER Metal3 ;
        RECT 176.575 8.620 176.975 9.020 ;
    END
  END s_rdata[47]
  PIN s_rdata[48]
    DIRECTION INPUT ;
    USE SIGNAL ;
    ANTENNAGATEAREA 0.180700 ;
    PORT
      LAYER Metal2 ;
        RECT 118.360 0.000 118.760 0.400 ;
    END
  END s_rdata[48]
  PIN s_rdata[49]
    DIRECTION INPUT ;
    USE SIGNAL ;
    ANTENNAGATEAREA 0.180700 ;
    PORT
      LAYER Metal2 ;
        RECT 96.280 0.000 96.680 0.400 ;
    END
  END s_rdata[49]
  PIN s_rdata[4]
    DIRECTION INPUT ;
    USE SIGNAL ;
    ANTENNAGATEAREA 0.180700 ;
    PORT
      LAYER Metal3 ;
        RECT 176.575 112.780 176.975 113.180 ;
    END
  END s_rdata[4]
  PIN s_rdata[50]
    DIRECTION INPUT ;
    USE SIGNAL ;
    ANTENNAGATEAREA 0.180700 ;
    PORT
      LAYER Metal2 ;
        RECT 90.520 195.295 90.920 195.695 ;
    END
  END s_rdata[50]
  PIN s_rdata[51]
    DIRECTION INPUT ;
    USE SIGNAL ;
    ANTENNAGATEAREA 0.180700 ;
    PORT
      LAYER Metal3 ;
        RECT 0.000 98.500 0.400 98.900 ;
    END
  END s_rdata[51]
  PIN s_rdata[52]
    DIRECTION INPUT ;
    USE SIGNAL ;
    ANTENNAGATEAREA 0.180700 ;
    PORT
      LAYER Metal2 ;
        RECT 100.120 195.295 100.520 195.695 ;
    END
  END s_rdata[52]
  PIN s_rdata[53]
    DIRECTION INPUT ;
    USE SIGNAL ;
    ANTENNAGATEAREA 0.180700 ;
    PORT
      LAYER Metal3 ;
        RECT 0.000 136.300 0.400 136.700 ;
    END
  END s_rdata[53]
  PIN s_rdata[54]
    DIRECTION INPUT ;
    USE SIGNAL ;
    ANTENNAGATEAREA 0.180700 ;
    PORT
      LAYER Metal3 ;
        RECT 176.575 100.180 176.975 100.580 ;
    END
  END s_rdata[54]
  PIN s_rdata[55]
    DIRECTION INPUT ;
    USE SIGNAL ;
    ANTENNAGATEAREA 0.180700 ;
    PORT
      LAYER Metal3 ;
        RECT 176.575 159.820 176.975 160.220 ;
    END
  END s_rdata[55]
  PIN s_rdata[56]
    DIRECTION INPUT ;
    USE SIGNAL ;
    ANTENNAGATEAREA 0.180700 ;
    PORT
      LAYER Metal3 ;
        RECT 176.575 7.780 176.975 8.180 ;
    END
  END s_rdata[56]
  PIN s_rdata[57]
    DIRECTION INPUT ;
    USE SIGNAL ;
    ANTENNAGATEAREA 0.180700 ;
    PORT
      LAYER Metal3 ;
        RECT 176.575 121.180 176.975 121.580 ;
    END
  END s_rdata[57]
  PIN s_rdata[58]
    DIRECTION INPUT ;
    USE SIGNAL ;
    ANTENNAGATEAREA 0.180700 ;
    PORT
      LAYER Metal3 ;
        RECT 176.575 119.500 176.975 119.900 ;
    END
  END s_rdata[58]
  PIN s_rdata[59]
    DIRECTION INPUT ;
    USE SIGNAL ;
    ANTENNAGATEAREA 0.180700 ;
    PORT
      LAYER Metal3 ;
        RECT 176.575 17.020 176.975 17.420 ;
    END
  END s_rdata[59]
  PIN s_rdata[5]
    DIRECTION INPUT ;
    USE SIGNAL ;
    ANTENNAGATEAREA 0.180700 ;
    PORT
      LAYER Metal2 ;
        RECT 89.560 195.295 89.960 195.695 ;
    END
  END s_rdata[5]
  PIN s_rdata[60]
    DIRECTION INPUT ;
    USE SIGNAL ;
    ANTENNAGATEAREA 0.180700 ;
    PORT
      LAYER Metal3 ;
        RECT 176.575 83.380 176.975 83.780 ;
    END
  END s_rdata[60]
  PIN s_rdata[61]
    DIRECTION INPUT ;
    USE SIGNAL ;
    ANTENNAGATEAREA 0.180700 ;
    PORT
      LAYER Metal3 ;
        RECT 176.575 85.900 176.975 86.300 ;
    END
  END s_rdata[61]
  PIN s_rdata[62]
    DIRECTION INPUT ;
    USE SIGNAL ;
    ANTENNAGATEAREA 0.180700 ;
    PORT
      LAYER Metal3 ;
        RECT 176.575 73.300 176.975 73.700 ;
    END
  END s_rdata[62]
  PIN s_rdata[63]
    DIRECTION INPUT ;
    USE SIGNAL ;
    ANTENNAGATEAREA 0.180700 ;
    PORT
      LAYER Metal3 ;
        RECT 176.575 163.180 176.975 163.580 ;
    END
  END s_rdata[63]
  PIN s_rdata[64]
    DIRECTION INPUT ;
    USE SIGNAL ;
    ANTENNAGATEAREA 0.180700 ;
    PORT
      LAYER Metal2 ;
        RECT 76.120 195.295 76.520 195.695 ;
    END
  END s_rdata[64]
  PIN s_rdata[65]
    DIRECTION INPUT ;
    USE SIGNAL ;
    ANTENNAGATEAREA 0.180700 ;
    PORT
      LAYER Metal2 ;
        RECT 160.600 0.000 161.000 0.400 ;
    END
  END s_rdata[65]
  PIN s_rdata[66]
    DIRECTION INPUT ;
    USE SIGNAL ;
    ANTENNAGATEAREA 0.180700 ;
    PORT
      LAYER Metal3 ;
        RECT 0.000 38.020 0.400 38.420 ;
    END
  END s_rdata[66]
  PIN s_rdata[67]
    DIRECTION INPUT ;
    USE SIGNAL ;
    ANTENNAGATEAREA 0.180700 ;
    PORT
      LAYER Metal2 ;
        RECT 107.800 0.000 108.200 0.400 ;
    END
  END s_rdata[67]
  PIN s_rdata[68]
    DIRECTION INPUT ;
    USE SIGNAL ;
    ANTENNAGATEAREA 0.180700 ;
    PORT
      LAYER Metal3 ;
        RECT 176.575 123.700 176.975 124.100 ;
    END
  END s_rdata[68]
  PIN s_rdata[69]
    DIRECTION INPUT ;
    USE SIGNAL ;
    ANTENNAGATEAREA 0.180700 ;
    PORT
      LAYER Metal2 ;
        RECT 85.720 195.295 86.120 195.695 ;
    END
  END s_rdata[69]
  PIN s_rdata[6]
    DIRECTION INPUT ;
    USE SIGNAL ;
    ANTENNAGATEAREA 0.180700 ;
    PORT
      LAYER Metal3 ;
        RECT 0.000 104.380 0.400 104.780 ;
    END
  END s_rdata[6]
  PIN s_rdata[70]
    DIRECTION INPUT ;
    USE SIGNAL ;
    ANTENNAGATEAREA 0.180700 ;
    PORT
      LAYER Metal3 ;
        RECT 0.000 172.420 0.400 172.820 ;
    END
  END s_rdata[70]
  PIN s_rdata[71]
    DIRECTION INPUT ;
    USE SIGNAL ;
    ANTENNAGATEAREA 0.180700 ;
    PORT
      LAYER Metal2 ;
        RECT 71.320 0.000 71.720 0.400 ;
    END
  END s_rdata[71]
  PIN s_rdata[72]
    DIRECTION INPUT ;
    USE SIGNAL ;
    ANTENNAGATEAREA 0.180700 ;
    PORT
      LAYER Metal2 ;
        RECT 82.840 0.000 83.240 0.400 ;
    END
  END s_rdata[72]
  PIN s_rdata[73]
    DIRECTION INPUT ;
    USE SIGNAL ;
    ANTENNAGATEAREA 0.180700 ;
    PORT
      LAYER Metal3 ;
        RECT 176.575 65.740 176.975 66.140 ;
    END
  END s_rdata[73]
  PIN s_rdata[74]
    DIRECTION INPUT ;
    USE SIGNAL ;
    ANTENNAGATEAREA 0.180700 ;
    PORT
      LAYER Metal2 ;
        RECT 42.520 0.000 42.920 0.400 ;
    END
  END s_rdata[74]
  PIN s_rdata[75]
    DIRECTION INPUT ;
    USE SIGNAL ;
    ANTENNAGATEAREA 0.180700 ;
    PORT
      LAYER Metal3 ;
        RECT 0.000 78.340 0.400 78.740 ;
    END
  END s_rdata[75]
  PIN s_rdata[76]
    DIRECTION INPUT ;
    USE SIGNAL ;
    ANTENNAGATEAREA 0.180700 ;
    PORT
      LAYER Metal2 ;
        RECT 124.120 195.295 124.520 195.695 ;
    END
  END s_rdata[76]
  PIN s_rdata[77]
    DIRECTION INPUT ;
    USE SIGNAL ;
    ANTENNAGATEAREA 0.180700 ;
    PORT
      LAYER Metal3 ;
        RECT 0.000 130.420 0.400 130.820 ;
    END
  END s_rdata[77]
  PIN s_rdata[78]
    DIRECTION INPUT ;
    USE SIGNAL ;
    ANTENNAGATEAREA 0.180700 ;
    PORT
      LAYER Metal2 ;
        RECT 58.840 0.000 59.240 0.400 ;
    END
  END s_rdata[78]
  PIN s_rdata[79]
    DIRECTION INPUT ;
    USE SIGNAL ;
    ANTENNAGATEAREA 0.180700 ;
    PORT
      LAYER Metal3 ;
        RECT 176.575 89.260 176.975 89.660 ;
    END
  END s_rdata[79]
  PIN s_rdata[7]
    DIRECTION INPUT ;
    USE SIGNAL ;
    ANTENNAGATEAREA 0.180700 ;
    PORT
      LAYER Metal2 ;
        RECT 80.920 0.000 81.320 0.400 ;
    END
  END s_rdata[7]
  PIN s_rdata[80]
    DIRECTION INPUT ;
    USE SIGNAL ;
    ANTENNAGATEAREA 0.180700 ;
    PORT
      LAYER Metal2 ;
        RECT 126.040 0.000 126.440 0.400 ;
    END
  END s_rdata[80]
  PIN s_rdata[81]
    DIRECTION INPUT ;
    USE SIGNAL ;
    ANTENNAGATEAREA 0.180700 ;
    PORT
      LAYER Metal2 ;
        RECT 85.720 0.000 86.120 0.400 ;
    END
  END s_rdata[81]
  PIN s_rdata[82]
    DIRECTION INPUT ;
    USE SIGNAL ;
    ANTENNAGATEAREA 0.180700 ;
    PORT
      LAYER Metal2 ;
        RECT 87.640 0.000 88.040 0.400 ;
    END
  END s_rdata[82]
  PIN s_rdata[83]
    DIRECTION INPUT ;
    USE SIGNAL ;
    ANTENNAGATEAREA 0.180700 ;
    PORT
      LAYER Metal3 ;
        RECT 0.000 27.100 0.400 27.500 ;
    END
  END s_rdata[83]
  PIN s_rdata[84]
    DIRECTION INPUT ;
    USE SIGNAL ;
    ANTENNAGATEAREA 0.180700 ;
    PORT
      LAYER Metal2 ;
        RECT 153.880 195.295 154.280 195.695 ;
    END
  END s_rdata[84]
  PIN s_rdata[85]
    DIRECTION INPUT ;
    USE SIGNAL ;
    ANTENNAGATEAREA 0.180700 ;
    PORT
      LAYER Metal2 ;
        RECT 64.600 195.295 65.000 195.695 ;
    END
  END s_rdata[85]
  PIN s_rdata[86]
    DIRECTION INPUT ;
    USE SIGNAL ;
    ANTENNAGATEAREA 0.180700 ;
    PORT
      LAYER Metal3 ;
        RECT 176.575 90.100 176.975 90.500 ;
    END
  END s_rdata[86]
  PIN s_rdata[87]
    DIRECTION INPUT ;
    USE SIGNAL ;
    ANTENNAGATEAREA 0.180700 ;
    PORT
      LAYER Metal2 ;
        RECT 129.880 195.295 130.280 195.695 ;
    END
  END s_rdata[87]
  PIN s_rdata[88]
    DIRECTION INPUT ;
    USE SIGNAL ;
    ANTENNAGATEAREA 0.180700 ;
    PORT
      LAYER Metal3 ;
        RECT 176.575 161.500 176.975 161.900 ;
    END
  END s_rdata[88]
  PIN s_rdata[89]
    DIRECTION INPUT ;
    USE SIGNAL ;
    ANTENNAGATEAREA 0.180700 ;
    PORT
      LAYER Metal3 ;
        RECT 176.575 192.580 176.975 192.980 ;
    END
  END s_rdata[89]
  PIN s_rdata[8]
    DIRECTION INPUT ;
    USE SIGNAL ;
    ANTENNAGATEAREA 0.180700 ;
    PORT
      LAYER Metal2 ;
        RECT 89.560 0.000 89.960 0.400 ;
    END
  END s_rdata[8]
  PIN s_rdata[90]
    DIRECTION INPUT ;
    USE SIGNAL ;
    ANTENNAGATEAREA 0.180700 ;
    PORT
      LAYER Metal3 ;
        RECT 176.575 193.420 176.975 193.820 ;
    END
  END s_rdata[90]
  PIN s_rdata[91]
    DIRECTION INPUT ;
    USE SIGNAL ;
    ANTENNAGATEAREA 0.180700 ;
    PORT
      LAYER Metal3 ;
        RECT 176.575 72.460 176.975 72.860 ;
    END
  END s_rdata[91]
  PIN s_rdata[92]
    DIRECTION INPUT ;
    USE SIGNAL ;
    ANTENNAGATEAREA 0.180700 ;
    PORT
      LAYER Metal3 ;
        RECT 176.575 80.020 176.975 80.420 ;
    END
  END s_rdata[92]
  PIN s_rdata[93]
    DIRECTION INPUT ;
    USE SIGNAL ;
    ANTENNAGATEAREA 0.180700 ;
    PORT
      LAYER Metal3 ;
        RECT 176.575 101.860 176.975 102.260 ;
    END
  END s_rdata[93]
  PIN s_rdata[94]
    DIRECTION INPUT ;
    USE SIGNAL ;
    ANTENNAGATEAREA 0.180700 ;
    PORT
      LAYER Metal2 ;
        RECT 121.240 0.000 121.640 0.400 ;
    END
  END s_rdata[94]
  PIN s_rdata[95]
    DIRECTION INPUT ;
    USE SIGNAL ;
    ANTENNAGATEAREA 0.180700 ;
    PORT
      LAYER Metal3 ;
        RECT 176.575 105.220 176.975 105.620 ;
    END
  END s_rdata[95]
  PIN s_rdata[96]
    DIRECTION INPUT ;
    USE SIGNAL ;
    ANTENNAGATEAREA 0.180700 ;
    PORT
      LAYER Metal2 ;
        RECT 74.200 195.295 74.600 195.695 ;
    END
  END s_rdata[96]
  PIN s_rdata[97]
    DIRECTION INPUT ;
    USE SIGNAL ;
    ANTENNAGATEAREA 0.180700 ;
    PORT
      LAYER Metal3 ;
        RECT 176.575 59.020 176.975 59.420 ;
    END
  END s_rdata[97]
  PIN s_rdata[98]
    DIRECTION INPUT ;
    USE SIGNAL ;
    ANTENNAGATEAREA 0.180700 ;
    PORT
      LAYER Metal3 ;
        RECT 0.000 68.260 0.400 68.660 ;
    END
  END s_rdata[98]
  PIN s_rdata[99]
    DIRECTION INPUT ;
    USE SIGNAL ;
    ANTENNAGATEAREA 0.180700 ;
    PORT
      LAYER Metal2 ;
        RECT 124.120 0.000 124.520 0.400 ;
    END
  END s_rdata[99]
  PIN s_rdata[9]
    DIRECTION INPUT ;
    USE SIGNAL ;
    ANTENNAGATEAREA 0.180700 ;
    PORT
      LAYER Metal3 ;
        RECT 176.575 15.340 176.975 15.740 ;
    END
  END s_rdata[9]
  PIN s_rready[0]
    DIRECTION OUTPUT ;
    USE SIGNAL ;
    ANTENNADIFFAREA 0.708600 ;
    PORT
      LAYER Metal3 ;
        RECT 176.575 55.660 176.975 56.060 ;
    END
  END s_rready[0]
  PIN s_rready[1]
    DIRECTION OUTPUT ;
    USE SIGNAL ;
    ANTENNADIFFAREA 0.708600 ;
    PORT
      LAYER Metal3 ;
        RECT 176.575 21.220 176.975 21.620 ;
    END
  END s_rready[1]
  PIN s_rready[2]
    DIRECTION OUTPUT ;
    USE SIGNAL ;
    ANTENNADIFFAREA 0.708600 ;
    PORT
      LAYER Metal3 ;
        RECT 176.575 59.860 176.975 60.260 ;
    END
  END s_rready[2]
  PIN s_rready[3]
    DIRECTION OUTPUT ;
    USE SIGNAL ;
    ANTENNADIFFAREA 0.708600 ;
    PORT
      LAYER Metal3 ;
        RECT 176.575 19.540 176.975 19.940 ;
    END
  END s_rready[3]
  PIN s_rresp[0]
    DIRECTION INPUT ;
    USE SIGNAL ;
    ANTENNAGATEAREA 0.180700 ;
    PORT
      LAYER Metal3 ;
        RECT 176.575 102.700 176.975 103.100 ;
    END
  END s_rresp[0]
  PIN s_rresp[1]
    DIRECTION INPUT ;
    USE SIGNAL ;
    ANTENNAGATEAREA 0.180700 ;
    PORT
      LAYER Metal3 ;
        RECT 176.575 107.740 176.975 108.140 ;
    END
  END s_rresp[1]
  PIN s_rresp[2]
    DIRECTION INPUT ;
    USE SIGNAL ;
    ANTENNAGATEAREA 0.180700 ;
    PORT
      LAYER Metal3 ;
        RECT 176.575 99.340 176.975 99.740 ;
    END
  END s_rresp[2]
  PIN s_rresp[3]
    DIRECTION INPUT ;
    USE SIGNAL ;
    ANTENNAGATEAREA 0.180700 ;
    PORT
      LAYER Metal3 ;
        RECT 176.575 130.420 176.975 130.820 ;
    END
  END s_rresp[3]
  PIN s_rresp[4]
    DIRECTION INPUT ;
    USE SIGNAL ;
    ANTENNAGATEAREA 0.180700 ;
    PORT
      LAYER Metal3 ;
        RECT 176.575 90.940 176.975 91.340 ;
    END
  END s_rresp[4]
  PIN s_rresp[5]
    DIRECTION INPUT ;
    USE SIGNAL ;
    ANTENNAGATEAREA 0.180700 ;
    PORT
      LAYER Metal3 ;
        RECT 176.575 118.660 176.975 119.060 ;
    END
  END s_rresp[5]
  PIN s_rresp[6]
    DIRECTION INPUT ;
    USE SIGNAL ;
    ANTENNAGATEAREA 0.180700 ;
    PORT
      LAYER Metal3 ;
        RECT 176.575 98.500 176.975 98.900 ;
    END
  END s_rresp[6]
  PIN s_rresp[7]
    DIRECTION INPUT ;
    USE SIGNAL ;
    ANTENNAGATEAREA 0.180700 ;
    PORT
      LAYER Metal3 ;
        RECT 176.575 113.620 176.975 114.020 ;
    END
  END s_rresp[7]
  PIN s_rvalid[0]
    DIRECTION INPUT ;
    USE SIGNAL ;
    ANTENNAGATEAREA 0.180700 ;
    PORT
      LAYER Metal2 ;
        RECT 107.800 195.295 108.200 195.695 ;
    END
  END s_rvalid[0]
  PIN s_rvalid[1]
    DIRECTION INPUT ;
    USE SIGNAL ;
    ANTENNAGATEAREA 0.180700 ;
    PORT
      LAYER Metal2 ;
        RECT 110.680 195.295 111.080 195.695 ;
    END
  END s_rvalid[1]
  PIN s_rvalid[2]
    DIRECTION INPUT ;
    USE SIGNAL ;
    ANTENNAGATEAREA 0.180700 ;
    PORT
      LAYER Metal2 ;
        RECT 139.480 195.295 139.880 195.695 ;
    END
  END s_rvalid[2]
  PIN s_rvalid[3]
    DIRECTION INPUT ;
    USE SIGNAL ;
    ANTENNAGATEAREA 0.180700 ;
    PORT
      LAYER Metal2 ;
        RECT 109.720 195.295 110.120 195.695 ;
    END
  END s_rvalid[3]
  PIN s_wdata[0]
    DIRECTION OUTPUT ;
    USE SIGNAL ;
    ANTENNADIFFAREA 0.708600 ;
    PORT
      LAYER Metal3 ;
        RECT 0.000 38.860 0.400 39.260 ;
    END
  END s_wdata[0]
  PIN s_wdata[100]
    DIRECTION OUTPUT ;
    USE SIGNAL ;
    ANTENNADIFFAREA 0.708600 ;
    PORT
      LAYER Metal2 ;
        RECT 42.520 195.295 42.920 195.695 ;
    END
  END s_wdata[100]
  PIN s_wdata[101]
    DIRECTION OUTPUT ;
    USE SIGNAL ;
    ANTENNADIFFAREA 0.708600 ;
    PORT
      LAYER Metal2 ;
        RECT 128.920 195.295 129.320 195.695 ;
    END
  END s_wdata[101]
  PIN s_wdata[102]
    DIRECTION OUTPUT ;
    USE SIGNAL ;
    ANTENNADIFFAREA 0.708600 ;
    PORT
      LAYER Metal3 ;
        RECT 0.000 47.260 0.400 47.660 ;
    END
  END s_wdata[102]
  PIN s_wdata[103]
    DIRECTION OUTPUT ;
    USE SIGNAL ;
    ANTENNADIFFAREA 0.708600 ;
    PORT
      LAYER Metal3 ;
        RECT 176.575 170.740 176.975 171.140 ;
    END
  END s_wdata[103]
  PIN s_wdata[104]
    DIRECTION OUTPUT ;
    USE SIGNAL ;
    ANTENNADIFFAREA 0.708600 ;
    PORT
      LAYER Metal3 ;
        RECT 176.575 138.820 176.975 139.220 ;
    END
  END s_wdata[104]
  PIN s_wdata[105]
    DIRECTION OUTPUT ;
    USE SIGNAL ;
    ANTENNADIFFAREA 0.708600 ;
    PORT
      LAYER Metal3 ;
        RECT 176.575 137.140 176.975 137.540 ;
    END
  END s_wdata[105]
  PIN s_wdata[106]
    DIRECTION OUTPUT ;
    USE SIGNAL ;
    ANTENNADIFFAREA 0.708600 ;
    PORT
      LAYER Metal2 ;
        RECT 115.480 195.295 115.880 195.695 ;
    END
  END s_wdata[106]
  PIN s_wdata[107]
    DIRECTION OUTPUT ;
    USE SIGNAL ;
    ANTENNADIFFAREA 0.708600 ;
    PORT
      LAYER Metal3 ;
        RECT 176.575 103.540 176.975 103.940 ;
    END
  END s_wdata[107]
  PIN s_wdata[108]
    DIRECTION OUTPUT ;
    USE SIGNAL ;
    ANTENNADIFFAREA 0.708600 ;
    PORT
      LAYER Metal3 ;
        RECT 0.000 158.980 0.400 159.380 ;
    END
  END s_wdata[108]
  PIN s_wdata[109]
    DIRECTION OUTPUT ;
    USE SIGNAL ;
    ANTENNADIFFAREA 0.708600 ;
    PORT
      LAYER Metal2 ;
        RECT 7.960 0.000 8.360 0.400 ;
    END
  END s_wdata[109]
  PIN s_wdata[10]
    DIRECTION OUTPUT ;
    USE SIGNAL ;
    ANTENNADIFFAREA 0.708600 ;
    PORT
      LAYER Metal2 ;
        RECT 121.240 195.295 121.640 195.695 ;
    END
  END s_wdata[10]
  PIN s_wdata[110]
    DIRECTION OUTPUT ;
    USE SIGNAL ;
    ANTENNADIFFAREA 0.708600 ;
    PORT
      LAYER Metal3 ;
        RECT 176.575 188.380 176.975 188.780 ;
    END
  END s_wdata[110]
  PIN s_wdata[111]
    DIRECTION OUTPUT ;
    USE SIGNAL ;
    ANTENNADIFFAREA 0.708600 ;
    PORT
      LAYER Metal2 ;
        RECT 46.360 195.295 46.760 195.695 ;
    END
  END s_wdata[111]
  PIN s_wdata[112]
    DIRECTION OUTPUT ;
    USE SIGNAL ;
    ANTENNADIFFAREA 0.708600 ;
    PORT
      LAYER Metal3 ;
        RECT 176.575 191.740 176.975 192.140 ;
    END
  END s_wdata[112]
  PIN s_wdata[113]
    DIRECTION OUTPUT ;
    USE SIGNAL ;
    ANTENNADIFFAREA 0.708600 ;
    PORT
      LAYER Metal3 ;
        RECT 176.575 187.540 176.975 187.940 ;
    END
  END s_wdata[113]
  PIN s_wdata[114]
    DIRECTION OUTPUT ;
    USE SIGNAL ;
    ANTENNADIFFAREA 0.708600 ;
    PORT
      LAYER Metal2 ;
        RECT 123.160 0.000 123.560 0.400 ;
    END
  END s_wdata[114]
  PIN s_wdata[115]
    DIRECTION OUTPUT ;
    USE SIGNAL ;
    ANTENNADIFFAREA 0.708600 ;
    PORT
      LAYER Metal2 ;
        RECT 104.920 195.295 105.320 195.695 ;
    END
  END s_wdata[115]
  PIN s_wdata[116]
    DIRECTION OUTPUT ;
    USE SIGNAL ;
    ANTENNADIFFAREA 0.708600 ;
    PORT
      LAYER Metal3 ;
        RECT 0.000 183.340 0.400 183.740 ;
    END
  END s_wdata[116]
  PIN s_wdata[117]
    DIRECTION OUTPUT ;
    USE SIGNAL ;
    ANTENNADIFFAREA 0.708600 ;
    PORT
      LAYER Metal2 ;
        RECT 150.040 0.000 150.440 0.400 ;
    END
  END s_wdata[117]
  PIN s_wdata[118]
    DIRECTION OUTPUT ;
    USE SIGNAL ;
    ANTENNADIFFAREA 0.708600 ;
    PORT
      LAYER Metal3 ;
        RECT 0.000 48.100 0.400 48.500 ;
    END
  END s_wdata[118]
  PIN s_wdata[119]
    DIRECTION OUTPUT ;
    USE SIGNAL ;
    ANTENNADIFFAREA 0.708600 ;
    PORT
      LAYER Metal2 ;
        RECT 99.160 195.295 99.560 195.695 ;
    END
  END s_wdata[119]
  PIN s_wdata[11]
    DIRECTION OUTPUT ;
    USE SIGNAL ;
    ANTENNADIFFAREA 0.708600 ;
    PORT
      LAYER Metal3 ;
        RECT 176.575 152.260 176.975 152.660 ;
    END
  END s_wdata[11]
  PIN s_wdata[120]
    DIRECTION OUTPUT ;
    USE SIGNAL ;
    ANTENNADIFFAREA 0.708600 ;
    PORT
      LAYER Metal2 ;
        RECT 96.280 195.295 96.680 195.695 ;
    END
  END s_wdata[120]
  PIN s_wdata[121]
    DIRECTION OUTPUT ;
    USE SIGNAL ;
    ANTENNADIFFAREA 0.708600 ;
    PORT
      LAYER Metal3 ;
        RECT 0.000 156.460 0.400 156.860 ;
    END
  END s_wdata[121]
  PIN s_wdata[122]
    DIRECTION OUTPUT ;
    USE SIGNAL ;
    ANTENNADIFFAREA 0.708600 ;
    PORT
      LAYER Metal3 ;
        RECT 176.575 127.060 176.975 127.460 ;
    END
  END s_wdata[122]
  PIN s_wdata[123]
    DIRECTION OUTPUT ;
    USE SIGNAL ;
    ANTENNADIFFAREA 0.708600 ;
    PORT
      LAYER Metal3 ;
        RECT 176.575 179.980 176.975 180.380 ;
    END
  END s_wdata[123]
  PIN s_wdata[124]
    DIRECTION OUTPUT ;
    USE SIGNAL ;
    ANTENNADIFFAREA 0.708600 ;
    PORT
      LAYER Metal3 ;
        RECT 176.575 114.460 176.975 114.860 ;
    END
  END s_wdata[124]
  PIN s_wdata[125]
    DIRECTION OUTPUT ;
    USE SIGNAL ;
    ANTENNADIFFAREA 0.708600 ;
    PORT
      LAYER Metal2 ;
        RECT 131.800 195.295 132.200 195.695 ;
    END
  END s_wdata[125]
  PIN s_wdata[126]
    DIRECTION OUTPUT ;
    USE SIGNAL ;
    ANTENNADIFFAREA 0.708600 ;
    PORT
      LAYER Metal2 ;
        RECT 76.120 0.000 76.520 0.400 ;
    END
  END s_wdata[126]
  PIN s_wdata[127]
    DIRECTION OUTPUT ;
    USE SIGNAL ;
    ANTENNADIFFAREA 0.708600 ;
    PORT
      LAYER Metal3 ;
        RECT 0.000 32.980 0.400 33.380 ;
    END
  END s_wdata[127]
  PIN s_wdata[12]
    DIRECTION OUTPUT ;
    USE SIGNAL ;
    ANTENNADIFFAREA 0.708600 ;
    PORT
      LAYER Metal3 ;
        RECT 0.000 159.820 0.400 160.220 ;
    END
  END s_wdata[12]
  PIN s_wdata[13]
    DIRECTION OUTPUT ;
    USE SIGNAL ;
    ANTENNADIFFAREA 0.708600 ;
    PORT
      LAYER Metal2 ;
        RECT 81.880 0.000 82.280 0.400 ;
    END
  END s_wdata[13]
  PIN s_wdata[14]
    DIRECTION OUTPUT ;
    USE SIGNAL ;
    ANTENNADIFFAREA 0.708600 ;
    PORT
      LAYER Metal3 ;
        RECT 176.575 171.580 176.975 171.980 ;
    END
  END s_wdata[14]
  PIN s_wdata[15]
    DIRECTION OUTPUT ;
    USE SIGNAL ;
    ANTENNADIFFAREA 0.708600 ;
    PORT
      LAYER Metal2 ;
        RECT 33.880 195.295 34.280 195.695 ;
    END
  END s_wdata[15]
  PIN s_wdata[16]
    DIRECTION OUTPUT ;
    USE SIGNAL ;
    ANTENNADIFFAREA 0.708600 ;
    PORT
      LAYER Metal3 ;
        RECT 176.575 172.420 176.975 172.820 ;
    END
  END s_wdata[16]
  PIN s_wdata[17]
    DIRECTION OUTPUT ;
    USE SIGNAL ;
    ANTENNADIFFAREA 0.708600 ;
    PORT
      LAYER Metal3 ;
        RECT 176.575 144.700 176.975 145.100 ;
    END
  END s_wdata[17]
  PIN s_wdata[18]
    DIRECTION OUTPUT ;
    USE SIGNAL ;
    ANTENNADIFFAREA 0.708600 ;
    PORT
      LAYER Metal2 ;
        RECT 127.000 0.000 127.400 0.400 ;
    END
  END s_wdata[18]
  PIN s_wdata[19]
    DIRECTION OUTPUT ;
    USE SIGNAL ;
    ANTENNADIFFAREA 0.708600 ;
    PORT
      LAYER Metal2 ;
        RECT 105.880 195.295 106.280 195.695 ;
    END
  END s_wdata[19]
  PIN s_wdata[1]
    DIRECTION OUTPUT ;
    USE SIGNAL ;
    ANTENNADIFFAREA 0.708600 ;
    PORT
      LAYER Metal2 ;
        RECT 37.720 195.295 38.120 195.695 ;
    END
  END s_wdata[1]
  PIN s_wdata[20]
    DIRECTION OUTPUT ;
    USE SIGNAL ;
    ANTENNADIFFAREA 0.708600 ;
    PORT
      LAYER Metal3 ;
        RECT 0.000 184.180 0.400 184.580 ;
    END
  END s_wdata[20]
  PIN s_wdata[21]
    DIRECTION OUTPUT ;
    USE SIGNAL ;
    ANTENNADIFFAREA 0.708600 ;
    PORT
      LAYER Metal2 ;
        RECT 149.080 0.000 149.480 0.400 ;
    END
  END s_wdata[21]
  PIN s_wdata[22]
    DIRECTION OUTPUT ;
    USE SIGNAL ;
    ANTENNADIFFAREA 0.708600 ;
    PORT
      LAYER Metal3 ;
        RECT 0.000 49.780 0.400 50.180 ;
    END
  END s_wdata[22]
  PIN s_wdata[23]
    DIRECTION OUTPUT ;
    USE SIGNAL ;
    ANTENNADIFFAREA 0.708600 ;
    PORT
      LAYER Metal2 ;
        RECT 101.080 195.295 101.480 195.695 ;
    END
  END s_wdata[23]
  PIN s_wdata[24]
    DIRECTION OUTPUT ;
    USE SIGNAL ;
    ANTENNADIFFAREA 0.708600 ;
    PORT
      LAYER Metal2 ;
        RECT 95.320 195.295 95.720 195.695 ;
    END
  END s_wdata[24]
  PIN s_wdata[25]
    DIRECTION OUTPUT ;
    USE SIGNAL ;
    ANTENNADIFFAREA 0.708600 ;
    PORT
      LAYER Metal3 ;
        RECT 0.000 163.180 0.400 163.580 ;
    END
  END s_wdata[25]
  PIN s_wdata[26]
    DIRECTION OUTPUT ;
    USE SIGNAL ;
    ANTENNADIFFAREA 0.708600 ;
    PORT
      LAYER Metal3 ;
        RECT 176.575 128.740 176.975 129.140 ;
    END
  END s_wdata[26]
  PIN s_wdata[27]
    DIRECTION OUTPUT ;
    USE SIGNAL ;
    ANTENNADIFFAREA 0.708600 ;
    PORT
      LAYER Metal2 ;
        RECT 146.200 195.295 146.600 195.695 ;
    END
  END s_wdata[27]
  PIN s_wdata[28]
    DIRECTION OUTPUT ;
    USE SIGNAL ;
    ANTENNADIFFAREA 0.708600 ;
    PORT
      LAYER Metal3 ;
        RECT 176.575 117.820 176.975 118.220 ;
    END
  END s_wdata[28]
  PIN s_wdata[29]
    DIRECTION OUTPUT ;
    USE SIGNAL ;
    ANTENNADIFFAREA 0.708600 ;
    PORT
      LAYER Metal2 ;
        RECT 112.600 195.295 113.000 195.695 ;
    END
  END s_wdata[29]
  PIN s_wdata[2]
    DIRECTION OUTPUT ;
    USE SIGNAL ;
    ANTENNADIFFAREA 0.708600 ;
    PORT
      LAYER Metal2 ;
        RECT 16.600 0.000 17.000 0.400 ;
    END
  END s_wdata[2]
  PIN s_wdata[30]
    DIRECTION OUTPUT ;
    USE SIGNAL ;
    ANTENNADIFFAREA 0.708600 ;
    PORT
      LAYER Metal2 ;
        RECT 20.440 0.000 20.840 0.400 ;
    END
  END s_wdata[30]
  PIN s_wdata[31]
    DIRECTION OUTPUT ;
    USE SIGNAL ;
    ANTENNADIFFAREA 0.708600 ;
    PORT
      LAYER Metal3 ;
        RECT 0.000 43.060 0.400 43.460 ;
    END
  END s_wdata[31]
  PIN s_wdata[32]
    DIRECTION OUTPUT ;
    USE SIGNAL ;
    ANTENNADIFFAREA 0.708600 ;
    PORT
      LAYER Metal3 ;
        RECT 0.000 32.140 0.400 32.540 ;
    END
  END s_wdata[32]
  PIN s_wdata[33]
    DIRECTION OUTPUT ;
    USE SIGNAL ;
    ANTENNADIFFAREA 0.708600 ;
    PORT
      LAYER Metal2 ;
        RECT 56.920 195.295 57.320 195.695 ;
    END
  END s_wdata[33]
  PIN s_wdata[34]
    DIRECTION OUTPUT ;
    USE SIGNAL ;
    ANTENNADIFFAREA 0.708600 ;
    PORT
      LAYER Metal2 ;
        RECT 15.640 0.000 16.040 0.400 ;
    END
  END s_wdata[34]
  PIN s_wdata[35]
    DIRECTION OUTPUT ;
    USE SIGNAL ;
    ANTENNADIFFAREA 0.708600 ;
    PORT
      LAYER Metal2 ;
        RECT 101.080 0.000 101.480 0.400 ;
    END
  END s_wdata[35]
  PIN s_wdata[36]
    DIRECTION OUTPUT ;
    USE SIGNAL ;
    ANTENNADIFFAREA 0.708600 ;
    PORT
      LAYER Metal2 ;
        RECT 35.800 195.295 36.200 195.695 ;
    END
  END s_wdata[36]
  PIN s_wdata[37]
    DIRECTION OUTPUT ;
    USE SIGNAL ;
    ANTENNADIFFAREA 0.708600 ;
    PORT
      LAYER Metal2 ;
        RECT 127.960 195.295 128.360 195.695 ;
    END
  END s_wdata[37]
  PIN s_wdata[38]
    DIRECTION OUTPUT ;
    USE SIGNAL ;
    ANTENNADIFFAREA 0.708600 ;
    PORT
      LAYER Metal3 ;
        RECT 0.000 45.580 0.400 45.980 ;
    END
  END s_wdata[38]
  PIN s_wdata[39]
    DIRECTION OUTPUT ;
    USE SIGNAL ;
    ANTENNADIFFAREA 0.708600 ;
    PORT
      LAYER Metal2 ;
        RECT 136.600 195.295 137.000 195.695 ;
    END
  END s_wdata[39]
  PIN s_wdata[3]
    DIRECTION OUTPUT ;
    USE SIGNAL ;
    ANTENNADIFFAREA 0.708600 ;
    PORT
      LAYER Metal2 ;
        RECT 90.520 0.000 90.920 0.400 ;
    END
  END s_wdata[3]
  PIN s_wdata[40]
    DIRECTION OUTPUT ;
    USE SIGNAL ;
    ANTENNADIFFAREA 0.708600 ;
    PORT
      LAYER Metal3 ;
        RECT 176.575 157.300 176.975 157.700 ;
    END
  END s_wdata[40]
  PIN s_wdata[41]
    DIRECTION OUTPUT ;
    USE SIGNAL ;
    ANTENNADIFFAREA 0.708600 ;
    PORT
      LAYER Metal3 ;
        RECT 176.575 148.060 176.975 148.460 ;
    END
  END s_wdata[41]
  PIN s_wdata[42]
    DIRECTION OUTPUT ;
    USE SIGNAL ;
    ANTENNADIFFAREA 0.708600 ;
    PORT
      LAYER Metal2 ;
        RECT 122.200 195.295 122.600 195.695 ;
    END
  END s_wdata[42]
  PIN s_wdata[43]
    DIRECTION OUTPUT ;
    USE SIGNAL ;
    ANTENNADIFFAREA 0.708600 ;
    PORT
      LAYER Metal3 ;
        RECT 176.575 106.060 176.975 106.460 ;
    END
  END s_wdata[43]
  PIN s_wdata[44]
    DIRECTION OUTPUT ;
    USE SIGNAL ;
    ANTENNADIFFAREA 0.708600 ;
    PORT
      LAYER Metal3 ;
        RECT 0.000 158.140 0.400 158.540 ;
    END
  END s_wdata[44]
  PIN s_wdata[45]
    DIRECTION OUTPUT ;
    USE SIGNAL ;
    ANTENNADIFFAREA 0.708600 ;
    PORT
      LAYER Metal2 ;
        RECT 6.040 0.000 6.440 0.400 ;
    END
  END s_wdata[45]
  PIN s_wdata[46]
    DIRECTION OUTPUT ;
    USE SIGNAL ;
    ANTENNADIFFAREA 0.708600 ;
    PORT
      LAYER Metal3 ;
        RECT 176.575 158.140 176.975 158.540 ;
    END
  END s_wdata[46]
  PIN s_wdata[47]
    DIRECTION OUTPUT ;
    USE SIGNAL ;
    ANTENNADIFFAREA 0.708600 ;
    PORT
      LAYER Metal2 ;
        RECT 58.840 195.295 59.240 195.695 ;
    END
  END s_wdata[47]
  PIN s_wdata[48]
    DIRECTION OUTPUT ;
    USE SIGNAL ;
    ANTENNADIFFAREA 0.708600 ;
    PORT
      LAYER Metal3 ;
        RECT 176.575 150.580 176.975 150.980 ;
    END
  END s_wdata[48]
  PIN s_wdata[49]
    DIRECTION OUTPUT ;
    USE SIGNAL ;
    ANTENNADIFFAREA 0.708600 ;
    PORT
      LAYER Metal3 ;
        RECT 176.575 143.860 176.975 144.260 ;
    END
  END s_wdata[49]
  PIN s_wdata[4]
    DIRECTION OUTPUT ;
    USE SIGNAL ;
    ANTENNADIFFAREA 0.708600 ;
    PORT
      LAYER Metal2 ;
        RECT 39.640 195.295 40.040 195.695 ;
    END
  END s_wdata[4]
  PIN s_wdata[50]
    DIRECTION OUTPUT ;
    USE SIGNAL ;
    ANTENNADIFFAREA 0.708600 ;
    PORT
      LAYER Metal2 ;
        RECT 125.080 0.000 125.480 0.400 ;
    END
  END s_wdata[50]
  PIN s_wdata[51]
    DIRECTION OUTPUT ;
    USE SIGNAL ;
    ANTENNADIFFAREA 0.708600 ;
    PORT
      LAYER Metal2 ;
        RECT 141.400 195.295 141.800 195.695 ;
    END
  END s_wdata[51]
  PIN s_wdata[52]
    DIRECTION OUTPUT ;
    USE SIGNAL ;
    ANTENNADIFFAREA 0.708600 ;
    PORT
      LAYER Metal3 ;
        RECT 0.000 189.220 0.400 189.620 ;
    END
  END s_wdata[52]
  PIN s_wdata[53]
    DIRECTION OUTPUT ;
    USE SIGNAL ;
    ANTENNADIFFAREA 0.708600 ;
    PORT
      LAYER Metal2 ;
        RECT 147.160 0.000 147.560 0.400 ;
    END
  END s_wdata[53]
  PIN s_wdata[54]
    DIRECTION OUTPUT ;
    USE SIGNAL ;
    ANTENNADIFFAREA 0.708600 ;
    PORT
      LAYER Metal3 ;
        RECT 0.000 44.740 0.400 45.140 ;
    END
  END s_wdata[54]
  PIN s_wdata[55]
    DIRECTION OUTPUT ;
    USE SIGNAL ;
    ANTENNADIFFAREA 0.708600 ;
    PORT
      LAYER Metal2 ;
        RECT 102.040 195.295 102.440 195.695 ;
    END
  END s_wdata[55]
  PIN s_wdata[56]
    DIRECTION OUTPUT ;
    USE SIGNAL ;
    ANTENNADIFFAREA 0.708600 ;
    PORT
      LAYER Metal2 ;
        RECT 154.840 195.295 155.240 195.695 ;
    END
  END s_wdata[56]
  PIN s_wdata[57]
    DIRECTION OUTPUT ;
    USE SIGNAL ;
    ANTENNADIFFAREA 0.708600 ;
    PORT
      LAYER Metal3 ;
        RECT 0.000 162.340 0.400 162.740 ;
    END
  END s_wdata[57]
  PIN s_wdata[58]
    DIRECTION OUTPUT ;
    USE SIGNAL ;
    ANTENNADIFFAREA 0.708600 ;
    PORT
      LAYER Metal3 ;
        RECT 176.575 136.300 176.975 136.700 ;
    END
  END s_wdata[58]
  PIN s_wdata[59]
    DIRECTION OUTPUT ;
    USE SIGNAL ;
    ANTENNADIFFAREA 0.708600 ;
    PORT
      LAYER Metal2 ;
        RECT 144.280 195.295 144.680 195.695 ;
    END
  END s_wdata[59]
  PIN s_wdata[5]
    DIRECTION OUTPUT ;
    USE SIGNAL ;
    ANTENNADIFFAREA 0.708600 ;
    PORT
      LAYER Metal2 ;
        RECT 126.040 195.295 126.440 195.695 ;
    END
  END s_wdata[5]
  PIN s_wdata[60]
    DIRECTION OUTPUT ;
    USE SIGNAL ;
    ANTENNADIFFAREA 0.708600 ;
    PORT
      LAYER Metal3 ;
        RECT 176.575 156.460 176.975 156.860 ;
    END
  END s_wdata[60]
  PIN s_wdata[61]
    DIRECTION OUTPUT ;
    USE SIGNAL ;
    ANTENNADIFFAREA 0.708600 ;
    PORT
      LAYER Metal2 ;
        RECT 132.760 195.295 133.160 195.695 ;
    END
  END s_wdata[61]
  PIN s_wdata[62]
    DIRECTION OUTPUT ;
    USE SIGNAL ;
    ANTENNADIFFAREA 0.708600 ;
    PORT
      LAYER Metal2 ;
        RECT 75.160 0.000 75.560 0.400 ;
    END
  END s_wdata[62]
  PIN s_wdata[63]
    DIRECTION OUTPUT ;
    USE SIGNAL ;
    ANTENNADIFFAREA 0.708600 ;
    PORT
      LAYER Metal3 ;
        RECT 0.000 34.660 0.400 35.060 ;
    END
  END s_wdata[63]
  PIN s_wdata[64]
    DIRECTION OUTPUT ;
    USE SIGNAL ;
    ANTENNADIFFAREA 0.708600 ;
    PORT
      LAYER Metal3 ;
        RECT 0.000 39.700 0.400 40.100 ;
    END
  END s_wdata[64]
  PIN s_wdata[65]
    DIRECTION OUTPUT ;
    USE SIGNAL ;
    ANTENNADIFFAREA 0.708600 ;
    PORT
      LAYER Metal2 ;
        RECT 26.200 195.295 26.600 195.695 ;
    END
  END s_wdata[65]
  PIN s_wdata[66]
    DIRECTION OUTPUT ;
    USE SIGNAL ;
    ANTENNADIFFAREA 0.708600 ;
    PORT
      LAYER Metal2 ;
        RECT 14.680 0.000 15.080 0.400 ;
    END
  END s_wdata[66]
  PIN s_wdata[67]
    DIRECTION OUTPUT ;
    USE SIGNAL ;
    ANTENNADIFFAREA 0.708600 ;
    PORT
      LAYER Metal2 ;
        RECT 92.440 0.000 92.840 0.400 ;
    END
  END s_wdata[67]
  PIN s_wdata[68]
    DIRECTION OUTPUT ;
    USE SIGNAL ;
    ANTENNADIFFAREA 0.708600 ;
    PORT
      LAYER Metal2 ;
        RECT 40.600 195.295 41.000 195.695 ;
    END
  END s_wdata[68]
  PIN s_wdata[69]
    DIRECTION OUTPUT ;
    USE SIGNAL ;
    ANTENNADIFFAREA 0.708600 ;
    PORT
      LAYER Metal2 ;
        RECT 127.000 195.295 127.400 195.695 ;
    END
  END s_wdata[69]
  PIN s_wdata[6]
    DIRECTION OUTPUT ;
    USE SIGNAL ;
    ANTENNADIFFAREA 0.708600 ;
    PORT
      LAYER Metal3 ;
        RECT 0.000 46.420 0.400 46.820 ;
    END
  END s_wdata[6]
  PIN s_wdata[70]
    DIRECTION OUTPUT ;
    USE SIGNAL ;
    ANTENNADIFFAREA 0.708600 ;
    PORT
      LAYER Metal3 ;
        RECT 0.000 48.940 0.400 49.340 ;
    END
  END s_wdata[70]
  PIN s_wdata[71]
    DIRECTION OUTPUT ;
    USE SIGNAL ;
    ANTENNADIFFAREA 0.708600 ;
    PORT
      LAYER Metal2 ;
        RECT 134.680 195.295 135.080 195.695 ;
    END
  END s_wdata[71]
  PIN s_wdata[72]
    DIRECTION OUTPUT ;
    USE SIGNAL ;
    ANTENNADIFFAREA 0.708600 ;
    PORT
      LAYER Metal3 ;
        RECT 176.575 137.980 176.975 138.380 ;
    END
  END s_wdata[72]
  PIN s_wdata[73]
    DIRECTION OUTPUT ;
    USE SIGNAL ;
    ANTENNADIFFAREA 0.708600 ;
    PORT
      LAYER Metal3 ;
        RECT 176.575 132.940 176.975 133.340 ;
    END
  END s_wdata[73]
  PIN s_wdata[74]
    DIRECTION OUTPUT ;
    USE SIGNAL ;
    ANTENNADIFFAREA 0.708600 ;
    PORT
      LAYER Metal2 ;
        RECT 123.160 195.295 123.560 195.695 ;
    END
  END s_wdata[74]
  PIN s_wdata[75]
    DIRECTION OUTPUT ;
    USE SIGNAL ;
    ANTENNADIFFAREA 0.708600 ;
    PORT
      LAYER Metal3 ;
        RECT 176.575 111.100 176.975 111.500 ;
    END
  END s_wdata[75]
  PIN s_wdata[76]
    DIRECTION OUTPUT ;
    USE SIGNAL ;
    ANTENNADIFFAREA 0.708600 ;
    PORT
      LAYER Metal3 ;
        RECT 0.000 161.500 0.400 161.900 ;
    END
  END s_wdata[76]
  PIN s_wdata[77]
    DIRECTION OUTPUT ;
    USE SIGNAL ;
    ANTENNADIFFAREA 0.708600 ;
    PORT
      LAYER Metal2 ;
        RECT 7.000 0.000 7.400 0.400 ;
    END
  END s_wdata[77]
  PIN s_wdata[78]
    DIRECTION OUTPUT ;
    USE SIGNAL ;
    ANTENNADIFFAREA 0.708600 ;
    PORT
      LAYER Metal3 ;
        RECT 176.575 133.780 176.975 134.180 ;
    END
  END s_wdata[78]
  PIN s_wdata[79]
    DIRECTION OUTPUT ;
    USE SIGNAL ;
    ANTENNADIFFAREA 0.708600 ;
    PORT
      LAYER Metal2 ;
        RECT 60.760 195.295 61.160 195.695 ;
    END
  END s_wdata[79]
  PIN s_wdata[7]
    DIRECTION OUTPUT ;
    USE SIGNAL ;
    ANTENNADIFFAREA 0.708600 ;
    PORT
      LAYER Metal2 ;
        RECT 135.640 195.295 136.040 195.695 ;
    END
  END s_wdata[7]
  PIN s_wdata[80]
    DIRECTION OUTPUT ;
    USE SIGNAL ;
    ANTENNADIFFAREA 0.708600 ;
    PORT
      LAYER Metal3 ;
        RECT 176.575 149.740 176.975 150.140 ;
    END
  END s_wdata[80]
  PIN s_wdata[81]
    DIRECTION OUTPUT ;
    USE SIGNAL ;
    ANTENNADIFFAREA 0.708600 ;
    PORT
      LAYER Metal3 ;
        RECT 176.575 143.020 176.975 143.420 ;
    END
  END s_wdata[81]
  PIN s_wdata[82]
    DIRECTION OUTPUT ;
    USE SIGNAL ;
    ANTENNADIFFAREA 0.708600 ;
    PORT
      LAYER Metal2 ;
        RECT 146.200 0.000 146.600 0.400 ;
    END
  END s_wdata[82]
  PIN s_wdata[83]
    DIRECTION OUTPUT ;
    USE SIGNAL ;
    ANTENNADIFFAREA 0.708600 ;
    PORT
      LAYER Metal2 ;
        RECT 142.360 195.295 142.760 195.695 ;
    END
  END s_wdata[83]
  PIN s_wdata[84]
    DIRECTION OUTPUT ;
    USE SIGNAL ;
    ANTENNADIFFAREA 0.708600 ;
    PORT
      LAYER Metal3 ;
        RECT 0.000 186.700 0.400 187.100 ;
    END
  END s_wdata[84]
  PIN s_wdata[85]
    DIRECTION OUTPUT ;
    USE SIGNAL ;
    ANTENNADIFFAREA 0.708600 ;
    PORT
      LAYER Metal2 ;
        RECT 148.120 0.000 148.520 0.400 ;
    END
  END s_wdata[85]
  PIN s_wdata[86]
    DIRECTION OUTPUT ;
    USE SIGNAL ;
    ANTENNADIFFAREA 0.708600 ;
    PORT
      LAYER Metal3 ;
        RECT 0.000 50.620 0.400 51.020 ;
    END
  END s_wdata[86]
  PIN s_wdata[87]
    DIRECTION OUTPUT ;
    USE SIGNAL ;
    ANTENNADIFFAREA 0.708600 ;
    PORT
      LAYER Metal2 ;
        RECT 150.040 195.295 150.440 195.695 ;
    END
  END s_wdata[87]
  PIN s_wdata[88]
    DIRECTION OUTPUT ;
    USE SIGNAL ;
    ANTENNADIFFAREA 0.708600 ;
    PORT
      LAYER Metal2 ;
        RECT 94.360 195.295 94.760 195.695 ;
    END
  END s_wdata[88]
  PIN s_wdata[89]
    DIRECTION OUTPUT ;
    USE SIGNAL ;
    ANTENNADIFFAREA 0.708600 ;
    PORT
      LAYER Metal3 ;
        RECT 0.000 164.020 0.400 164.420 ;
    END
  END s_wdata[89]
  PIN s_wdata[8]
    DIRECTION OUTPUT ;
    USE SIGNAL ;
    ANTENNADIFFAREA 0.708600 ;
    PORT
      LAYER Metal3 ;
        RECT 176.575 127.900 176.975 128.300 ;
    END
  END s_wdata[8]
  PIN s_wdata[90]
    DIRECTION OUTPUT ;
    USE SIGNAL ;
    ANTENNADIFFAREA 0.708600 ;
    PORT
      LAYER Metal3 ;
        RECT 176.575 153.100 176.975 153.500 ;
    END
  END s_wdata[90]
  PIN s_wdata[91]
    DIRECTION OUTPUT ;
    USE SIGNAL ;
    ANTENNADIFFAREA 0.708600 ;
    PORT
      LAYER Metal2 ;
        RECT 145.240 195.295 145.640 195.695 ;
    END
  END s_wdata[91]
  PIN s_wdata[92]
    DIRECTION OUTPUT ;
    USE SIGNAL ;
    ANTENNADIFFAREA 0.708600 ;
    PORT
      LAYER Metal3 ;
        RECT 176.575 124.540 176.975 124.940 ;
    END
  END s_wdata[92]
  PIN s_wdata[93]
    DIRECTION OUTPUT ;
    USE SIGNAL ;
    ANTENNADIFFAREA 0.708600 ;
    PORT
      LAYER Metal2 ;
        RECT 113.560 195.295 113.960 195.695 ;
    END
  END s_wdata[93]
  PIN s_wdata[94]
    DIRECTION OUTPUT ;
    USE SIGNAL ;
    ANTENNADIFFAREA 0.708600 ;
    PORT
      LAYER Metal2 ;
        RECT 19.480 0.000 19.880 0.400 ;
    END
  END s_wdata[94]
  PIN s_wdata[95]
    DIRECTION OUTPUT ;
    USE SIGNAL ;
    ANTENNADIFFAREA 0.708600 ;
    PORT
      LAYER Metal3 ;
        RECT 0.000 55.660 0.400 56.060 ;
    END
  END s_wdata[95]
  PIN s_wdata[96]
    DIRECTION OUTPUT ;
    USE SIGNAL ;
    ANTENNADIFFAREA 0.708600 ;
    PORT
      LAYER Metal3 ;
        RECT 0.000 37.180 0.400 37.580 ;
    END
  END s_wdata[96]
  PIN s_wdata[97]
    DIRECTION OUTPUT ;
    USE SIGNAL ;
    ANTENNADIFFAREA 0.708600 ;
    PORT
      LAYER Metal2 ;
        RECT 24.280 195.295 24.680 195.695 ;
    END
  END s_wdata[97]
  PIN s_wdata[98]
    DIRECTION OUTPUT ;
    USE SIGNAL ;
    ANTENNADIFFAREA 0.708600 ;
    PORT
      LAYER Metal2 ;
        RECT 13.720 0.000 14.120 0.400 ;
    END
  END s_wdata[98]
  PIN s_wdata[99]
    DIRECTION OUTPUT ;
    USE SIGNAL ;
    ANTENNADIFFAREA 0.708600 ;
    PORT
      LAYER Metal2 ;
        RECT 98.200 0.000 98.600 0.400 ;
    END
  END s_wdata[99]
  PIN s_wdata[9]
    DIRECTION OUTPUT ;
    USE SIGNAL ;
    ANTENNADIFFAREA 0.708600 ;
    PORT
      LAYER Metal3 ;
        RECT 176.575 135.460 176.975 135.860 ;
    END
  END s_wdata[9]
  PIN s_wready[0]
    DIRECTION INPUT ;
    USE SIGNAL ;
    ANTENNAGATEAREA 0.180700 ;
    PORT
      LAYER Metal3 ;
        RECT 0.000 132.100 0.400 132.500 ;
    END
  END s_wready[0]
  PIN s_wready[1]
    DIRECTION INPUT ;
    USE SIGNAL ;
    ANTENNAGATEAREA 0.180700 ;
    PORT
      LAYER Metal2 ;
        RECT 31.000 195.295 31.400 195.695 ;
    END
  END s_wready[1]
  PIN s_wready[2]
    DIRECTION INPUT ;
    USE SIGNAL ;
    ANTENNAGATEAREA 0.180700 ;
    PORT
      LAYER Metal2 ;
        RECT 28.120 195.295 28.520 195.695 ;
    END
  END s_wready[2]
  PIN s_wready[3]
    DIRECTION INPUT ;
    USE SIGNAL ;
    ANTENNAGATEAREA 0.180700 ;
    PORT
      LAYER Metal2 ;
        RECT 52.120 195.295 52.520 195.695 ;
    END
  END s_wready[3]
  PIN s_wstrb[0]
    DIRECTION OUTPUT ;
    USE SIGNAL ;
    ANTENNADIFFAREA 0.708600 ;
    PORT
      LAYER Metal3 ;
        RECT 176.575 24.580 176.975 24.980 ;
    END
  END s_wstrb[0]
  PIN s_wstrb[10]
    DIRECTION OUTPUT ;
    USE SIGNAL ;
    ANTENNADIFFAREA 0.708600 ;
    PORT
      LAYER Metal2 ;
        RECT 80.920 195.295 81.320 195.695 ;
    END
  END s_wstrb[10]
  PIN s_wstrb[11]
    DIRECTION OUTPUT ;
    USE SIGNAL ;
    ANTENNADIFFAREA 0.708600 ;
    PORT
      LAYER Metal2 ;
        RECT 155.800 195.295 156.200 195.695 ;
    END
  END s_wstrb[11]
  PIN s_wstrb[12]
    DIRECTION OUTPUT ;
    USE SIGNAL ;
    ANTENNADIFFAREA 0.708600 ;
    PORT
      LAYER Metal3 ;
        RECT 176.575 26.260 176.975 26.660 ;
    END
  END s_wstrb[12]
  PIN s_wstrb[13]
    DIRECTION OUTPUT ;
    USE SIGNAL ;
    ANTENNADIFFAREA 0.708600 ;
    PORT
      LAYER Metal2 ;
        RECT 32.920 195.295 33.320 195.695 ;
    END
  END s_wstrb[13]
  PIN s_wstrb[14]
    DIRECTION OUTPUT ;
    USE SIGNAL ;
    ANTENNADIFFAREA 0.708600 ;
    PORT
      LAYER Metal2 ;
        RECT 79.960 195.295 80.360 195.695 ;
    END
  END s_wstrb[14]
  PIN s_wstrb[15]
    DIRECTION OUTPUT ;
    USE SIGNAL ;
    ANTENNADIFFAREA 0.708600 ;
    PORT
      LAYER Metal2 ;
        RECT 156.760 195.295 157.160 195.695 ;
    END
  END s_wstrb[15]
  PIN s_wstrb[1]
    DIRECTION OUTPUT ;
    USE SIGNAL ;
    ANTENNADIFFAREA 0.708600 ;
    PORT
      LAYER Metal2 ;
        RECT 20.440 195.295 20.840 195.695 ;
    END
  END s_wstrb[1]
  PIN s_wstrb[2]
    DIRECTION OUTPUT ;
    USE SIGNAL ;
    ANTENNADIFFAREA 0.708600 ;
    PORT
      LAYER Metal2 ;
        RECT 84.760 195.295 85.160 195.695 ;
    END
  END s_wstrb[2]
  PIN s_wstrb[3]
    DIRECTION OUTPUT ;
    USE SIGNAL ;
    ANTENNADIFFAREA 0.708600 ;
    PORT
      LAYER Metal2 ;
        RECT 157.720 195.295 158.120 195.695 ;
    END
  END s_wstrb[3]
  PIN s_wstrb[4]
    DIRECTION OUTPUT ;
    USE SIGNAL ;
    ANTENNADIFFAREA 0.708600 ;
    PORT
      LAYER Metal3 ;
        RECT 176.575 27.100 176.975 27.500 ;
    END
  END s_wstrb[4]
  PIN s_wstrb[5]
    DIRECTION OUTPUT ;
    USE SIGNAL ;
    ANTENNADIFFAREA 0.708600 ;
    PORT
      LAYER Metal2 ;
        RECT 34.840 195.295 35.240 195.695 ;
    END
  END s_wstrb[5]
  PIN s_wstrb[6]
    DIRECTION OUTPUT ;
    USE SIGNAL ;
    ANTENNADIFFAREA 0.708600 ;
    PORT
      LAYER Metal2 ;
        RECT 22.360 195.295 22.760 195.695 ;
    END
  END s_wstrb[6]
  PIN s_wstrb[7]
    DIRECTION OUTPUT ;
    USE SIGNAL ;
    ANTENNADIFFAREA 0.708600 ;
    PORT
      LAYER Metal2 ;
        RECT 158.680 195.295 159.080 195.695 ;
    END
  END s_wstrb[7]
  PIN s_wstrb[8]
    DIRECTION OUTPUT ;
    USE SIGNAL ;
    ANTENNADIFFAREA 0.708600 ;
    PORT
      LAYER Metal3 ;
        RECT 176.575 25.420 176.975 25.820 ;
    END
  END s_wstrb[8]
  PIN s_wstrb[9]
    DIRECTION OUTPUT ;
    USE SIGNAL ;
    ANTENNADIFFAREA 0.708600 ;
    PORT
      LAYER Metal2 ;
        RECT 31.960 195.295 32.360 195.695 ;
    END
  END s_wstrb[9]
  PIN s_wvalid[0]
    DIRECTION OUTPUT ;
    USE SIGNAL ;
    ANTENNADIFFAREA 0.708600 ;
    PORT
      LAYER Metal2 ;
        RECT 43.480 195.295 43.880 195.695 ;
    END
  END s_wvalid[0]
  PIN s_wvalid[1]
    DIRECTION OUTPUT ;
    USE SIGNAL ;
    ANTENNADIFFAREA 0.708600 ;
    PORT
      LAYER Metal2 ;
        RECT 47.320 195.295 47.720 195.695 ;
    END
  END s_wvalid[1]
  PIN s_wvalid[2]
    DIRECTION OUTPUT ;
    USE SIGNAL ;
    ANTENNADIFFAREA 0.708600 ;
    PORT
      LAYER Metal2 ;
        RECT 53.080 195.295 53.480 195.695 ;
    END
  END s_wvalid[2]
  PIN s_wvalid[3]
    DIRECTION OUTPUT ;
    USE SIGNAL ;
    ANTENNADIFFAREA 0.708600 ;
    PORT
      LAYER Metal2 ;
        RECT 54.040 195.295 54.440 195.695 ;
    END
  END s_wvalid[3]
  OBS
      LAYER GatPoly ;
        RECT 5.760 14.970 170.880 177.810 ;
      LAYER Metal1 ;
        RECT 5.760 14.900 171.660 177.880 ;
      LAYER Metal2 ;
        RECT 0.375 195.085 18.310 195.295 ;
        RECT 19.130 195.085 19.270 195.295 ;
        RECT 20.090 195.085 20.230 195.295 ;
        RECT 21.050 195.085 21.190 195.295 ;
        RECT 22.010 195.085 22.150 195.295 ;
        RECT 22.970 195.085 23.110 195.295 ;
        RECT 23.930 195.085 24.070 195.295 ;
        RECT 24.890 195.085 25.030 195.295 ;
        RECT 25.850 195.085 25.990 195.295 ;
        RECT 26.810 195.085 26.950 195.295 ;
        RECT 27.770 195.085 27.910 195.295 ;
        RECT 28.730 195.085 28.870 195.295 ;
        RECT 29.690 195.085 29.830 195.295 ;
        RECT 30.650 195.085 30.790 195.295 ;
        RECT 31.610 195.085 31.750 195.295 ;
        RECT 32.570 195.085 32.710 195.295 ;
        RECT 33.530 195.085 33.670 195.295 ;
        RECT 34.490 195.085 34.630 195.295 ;
        RECT 35.450 195.085 35.590 195.295 ;
        RECT 36.410 195.085 36.550 195.295 ;
        RECT 37.370 195.085 37.510 195.295 ;
        RECT 38.330 195.085 38.470 195.295 ;
        RECT 39.290 195.085 39.430 195.295 ;
        RECT 40.250 195.085 40.390 195.295 ;
        RECT 41.210 195.085 41.350 195.295 ;
        RECT 42.170 195.085 42.310 195.295 ;
        RECT 43.130 195.085 43.270 195.295 ;
        RECT 44.090 195.085 44.230 195.295 ;
        RECT 45.050 195.085 45.190 195.295 ;
        RECT 46.010 195.085 46.150 195.295 ;
        RECT 46.970 195.085 47.110 195.295 ;
        RECT 47.930 195.085 48.070 195.295 ;
        RECT 48.890 195.085 49.030 195.295 ;
        RECT 49.850 195.085 49.990 195.295 ;
        RECT 50.810 195.085 50.950 195.295 ;
        RECT 51.770 195.085 51.910 195.295 ;
        RECT 52.730 195.085 52.870 195.295 ;
        RECT 53.690 195.085 53.830 195.295 ;
        RECT 54.650 195.085 54.790 195.295 ;
        RECT 55.610 195.085 55.750 195.295 ;
        RECT 56.570 195.085 56.710 195.295 ;
        RECT 57.530 195.085 57.670 195.295 ;
        RECT 58.490 195.085 58.630 195.295 ;
        RECT 59.450 195.085 59.590 195.295 ;
        RECT 60.410 195.085 60.550 195.295 ;
        RECT 61.370 195.085 61.510 195.295 ;
        RECT 62.330 195.085 62.470 195.295 ;
        RECT 63.290 195.085 63.430 195.295 ;
        RECT 64.250 195.085 64.390 195.295 ;
        RECT 65.210 195.085 65.350 195.295 ;
        RECT 66.170 195.085 66.310 195.295 ;
        RECT 67.130 195.085 67.270 195.295 ;
        RECT 68.090 195.085 68.230 195.295 ;
        RECT 69.050 195.085 69.190 195.295 ;
        RECT 70.010 195.085 70.150 195.295 ;
        RECT 70.970 195.085 71.110 195.295 ;
        RECT 71.930 195.085 72.070 195.295 ;
        RECT 72.890 195.085 73.030 195.295 ;
        RECT 73.850 195.085 73.990 195.295 ;
        RECT 74.810 195.085 74.950 195.295 ;
        RECT 75.770 195.085 75.910 195.295 ;
        RECT 76.730 195.085 76.870 195.295 ;
        RECT 77.690 195.085 77.830 195.295 ;
        RECT 78.650 195.085 78.790 195.295 ;
        RECT 79.610 195.085 79.750 195.295 ;
        RECT 80.570 195.085 80.710 195.295 ;
        RECT 81.530 195.085 81.670 195.295 ;
        RECT 82.490 195.085 82.630 195.295 ;
        RECT 83.450 195.085 83.590 195.295 ;
        RECT 84.410 195.085 84.550 195.295 ;
        RECT 85.370 195.085 85.510 195.295 ;
        RECT 86.330 195.085 86.470 195.295 ;
        RECT 87.290 195.085 87.430 195.295 ;
        RECT 88.250 195.085 88.390 195.295 ;
        RECT 89.210 195.085 89.350 195.295 ;
        RECT 90.170 195.085 90.310 195.295 ;
        RECT 91.130 195.085 91.270 195.295 ;
        RECT 92.090 195.085 92.230 195.295 ;
        RECT 93.050 195.085 93.190 195.295 ;
        RECT 94.010 195.085 94.150 195.295 ;
        RECT 94.970 195.085 95.110 195.295 ;
        RECT 95.930 195.085 96.070 195.295 ;
        RECT 96.890 195.085 97.030 195.295 ;
        RECT 97.850 195.085 97.990 195.295 ;
        RECT 98.810 195.085 98.950 195.295 ;
        RECT 99.770 195.085 99.910 195.295 ;
        RECT 100.730 195.085 100.870 195.295 ;
        RECT 101.690 195.085 101.830 195.295 ;
        RECT 102.650 195.085 102.790 195.295 ;
        RECT 103.610 195.085 103.750 195.295 ;
        RECT 104.570 195.085 104.710 195.295 ;
        RECT 105.530 195.085 105.670 195.295 ;
        RECT 106.490 195.085 106.630 195.295 ;
        RECT 107.450 195.085 107.590 195.295 ;
        RECT 108.410 195.085 108.550 195.295 ;
        RECT 109.370 195.085 109.510 195.295 ;
        RECT 110.330 195.085 110.470 195.295 ;
        RECT 111.290 195.085 111.430 195.295 ;
        RECT 112.250 195.085 112.390 195.295 ;
        RECT 113.210 195.085 113.350 195.295 ;
        RECT 114.170 195.085 114.310 195.295 ;
        RECT 115.130 195.085 115.270 195.295 ;
        RECT 116.090 195.085 116.230 195.295 ;
        RECT 117.050 195.085 117.190 195.295 ;
        RECT 118.010 195.085 118.150 195.295 ;
        RECT 118.970 195.085 119.110 195.295 ;
        RECT 119.930 195.085 120.070 195.295 ;
        RECT 120.890 195.085 121.030 195.295 ;
        RECT 121.850 195.085 121.990 195.295 ;
        RECT 122.810 195.085 122.950 195.295 ;
        RECT 123.770 195.085 123.910 195.295 ;
        RECT 124.730 195.085 124.870 195.295 ;
        RECT 125.690 195.085 125.830 195.295 ;
        RECT 126.650 195.085 126.790 195.295 ;
        RECT 127.610 195.085 127.750 195.295 ;
        RECT 128.570 195.085 128.710 195.295 ;
        RECT 129.530 195.085 129.670 195.295 ;
        RECT 130.490 195.085 130.630 195.295 ;
        RECT 131.450 195.085 131.590 195.295 ;
        RECT 132.410 195.085 132.550 195.295 ;
        RECT 133.370 195.085 133.510 195.295 ;
        RECT 134.330 195.085 134.470 195.295 ;
        RECT 135.290 195.085 135.430 195.295 ;
        RECT 136.250 195.085 136.390 195.295 ;
        RECT 137.210 195.085 137.350 195.295 ;
        RECT 138.170 195.085 138.310 195.295 ;
        RECT 139.130 195.085 139.270 195.295 ;
        RECT 140.090 195.085 140.230 195.295 ;
        RECT 141.050 195.085 141.190 195.295 ;
        RECT 142.010 195.085 142.150 195.295 ;
        RECT 142.970 195.085 143.110 195.295 ;
        RECT 143.930 195.085 144.070 195.295 ;
        RECT 144.890 195.085 145.030 195.295 ;
        RECT 145.850 195.085 145.990 195.295 ;
        RECT 146.810 195.085 146.950 195.295 ;
        RECT 147.770 195.085 147.910 195.295 ;
        RECT 148.730 195.085 148.870 195.295 ;
        RECT 149.690 195.085 149.830 195.295 ;
        RECT 150.650 195.085 150.790 195.295 ;
        RECT 151.610 195.085 151.750 195.295 ;
        RECT 152.570 195.085 152.710 195.295 ;
        RECT 153.530 195.085 153.670 195.295 ;
        RECT 154.490 195.085 154.630 195.295 ;
        RECT 155.450 195.085 155.590 195.295 ;
        RECT 156.410 195.085 156.550 195.295 ;
        RECT 157.370 195.085 157.510 195.295 ;
        RECT 158.330 195.085 158.470 195.295 ;
        RECT 159.290 195.085 159.430 195.295 ;
        RECT 160.250 195.085 160.390 195.295 ;
        RECT 161.210 195.085 176.265 195.295 ;
        RECT 0.375 0.610 176.265 195.085 ;
        RECT 0.375 0.400 1.990 0.610 ;
        RECT 2.810 0.400 2.950 0.610 ;
        RECT 3.770 0.400 4.870 0.610 ;
        RECT 5.690 0.400 5.830 0.610 ;
        RECT 6.650 0.400 6.790 0.610 ;
        RECT 7.610 0.400 7.750 0.610 ;
        RECT 8.570 0.400 8.710 0.610 ;
        RECT 9.530 0.400 9.670 0.610 ;
        RECT 10.490 0.400 10.630 0.610 ;
        RECT 11.450 0.400 11.590 0.610 ;
        RECT 12.410 0.400 12.550 0.610 ;
        RECT 13.370 0.400 13.510 0.610 ;
        RECT 14.330 0.400 14.470 0.610 ;
        RECT 15.290 0.400 15.430 0.610 ;
        RECT 16.250 0.400 16.390 0.610 ;
        RECT 17.210 0.400 17.350 0.610 ;
        RECT 18.170 0.400 18.310 0.610 ;
        RECT 19.130 0.400 19.270 0.610 ;
        RECT 20.090 0.400 20.230 0.610 ;
        RECT 21.050 0.400 21.190 0.610 ;
        RECT 22.010 0.400 22.150 0.610 ;
        RECT 22.970 0.400 23.110 0.610 ;
        RECT 23.930 0.400 24.070 0.610 ;
        RECT 24.890 0.400 25.030 0.610 ;
        RECT 25.850 0.400 25.990 0.610 ;
        RECT 26.810 0.400 26.950 0.610 ;
        RECT 27.770 0.400 27.910 0.610 ;
        RECT 28.730 0.400 28.870 0.610 ;
        RECT 29.690 0.400 29.830 0.610 ;
        RECT 30.650 0.400 30.790 0.610 ;
        RECT 31.610 0.400 31.750 0.610 ;
        RECT 32.570 0.400 32.710 0.610 ;
        RECT 33.530 0.400 33.670 0.610 ;
        RECT 34.490 0.400 34.630 0.610 ;
        RECT 35.450 0.400 35.590 0.610 ;
        RECT 36.410 0.400 36.550 0.610 ;
        RECT 37.370 0.400 37.510 0.610 ;
        RECT 38.330 0.400 38.470 0.610 ;
        RECT 39.290 0.400 39.430 0.610 ;
        RECT 40.250 0.400 40.390 0.610 ;
        RECT 41.210 0.400 41.350 0.610 ;
        RECT 42.170 0.400 42.310 0.610 ;
        RECT 43.130 0.400 43.270 0.610 ;
        RECT 44.090 0.400 44.230 0.610 ;
        RECT 45.050 0.400 45.190 0.610 ;
        RECT 46.010 0.400 46.150 0.610 ;
        RECT 46.970 0.400 47.110 0.610 ;
        RECT 47.930 0.400 48.070 0.610 ;
        RECT 48.890 0.400 49.030 0.610 ;
        RECT 49.850 0.400 49.990 0.610 ;
        RECT 50.810 0.400 50.950 0.610 ;
        RECT 51.770 0.400 51.910 0.610 ;
        RECT 52.730 0.400 52.870 0.610 ;
        RECT 53.690 0.400 53.830 0.610 ;
        RECT 54.650 0.400 54.790 0.610 ;
        RECT 55.610 0.400 55.750 0.610 ;
        RECT 56.570 0.400 56.710 0.610 ;
        RECT 57.530 0.400 57.670 0.610 ;
        RECT 58.490 0.400 58.630 0.610 ;
        RECT 59.450 0.400 59.590 0.610 ;
        RECT 60.410 0.400 60.550 0.610 ;
        RECT 61.370 0.400 61.510 0.610 ;
        RECT 62.330 0.400 62.470 0.610 ;
        RECT 63.290 0.400 63.430 0.610 ;
        RECT 64.250 0.400 64.390 0.610 ;
        RECT 65.210 0.400 65.350 0.610 ;
        RECT 66.170 0.400 66.310 0.610 ;
        RECT 67.130 0.400 67.270 0.610 ;
        RECT 68.090 0.400 68.230 0.610 ;
        RECT 69.050 0.400 69.190 0.610 ;
        RECT 70.010 0.400 70.150 0.610 ;
        RECT 70.970 0.400 71.110 0.610 ;
        RECT 71.930 0.400 72.070 0.610 ;
        RECT 72.890 0.400 73.030 0.610 ;
        RECT 73.850 0.400 73.990 0.610 ;
        RECT 74.810 0.400 74.950 0.610 ;
        RECT 75.770 0.400 75.910 0.610 ;
        RECT 76.730 0.400 76.870 0.610 ;
        RECT 77.690 0.400 77.830 0.610 ;
        RECT 78.650 0.400 78.790 0.610 ;
        RECT 79.610 0.400 79.750 0.610 ;
        RECT 80.570 0.400 80.710 0.610 ;
        RECT 81.530 0.400 81.670 0.610 ;
        RECT 82.490 0.400 82.630 0.610 ;
        RECT 83.450 0.400 83.590 0.610 ;
        RECT 84.410 0.400 84.550 0.610 ;
        RECT 85.370 0.400 85.510 0.610 ;
        RECT 86.330 0.400 86.470 0.610 ;
        RECT 87.290 0.400 87.430 0.610 ;
        RECT 88.250 0.400 88.390 0.610 ;
        RECT 89.210 0.400 89.350 0.610 ;
        RECT 90.170 0.400 90.310 0.610 ;
        RECT 91.130 0.400 91.270 0.610 ;
        RECT 92.090 0.400 92.230 0.610 ;
        RECT 93.050 0.400 93.190 0.610 ;
        RECT 94.010 0.400 94.150 0.610 ;
        RECT 94.970 0.400 95.110 0.610 ;
        RECT 95.930 0.400 96.070 0.610 ;
        RECT 96.890 0.400 97.030 0.610 ;
        RECT 97.850 0.400 97.990 0.610 ;
        RECT 98.810 0.400 98.950 0.610 ;
        RECT 99.770 0.400 99.910 0.610 ;
        RECT 100.730 0.400 100.870 0.610 ;
        RECT 101.690 0.400 101.830 0.610 ;
        RECT 102.650 0.400 102.790 0.610 ;
        RECT 103.610 0.400 103.750 0.610 ;
        RECT 104.570 0.400 104.710 0.610 ;
        RECT 105.530 0.400 105.670 0.610 ;
        RECT 106.490 0.400 106.630 0.610 ;
        RECT 107.450 0.400 107.590 0.610 ;
        RECT 108.410 0.400 108.550 0.610 ;
        RECT 109.370 0.400 109.510 0.610 ;
        RECT 110.330 0.400 110.470 0.610 ;
        RECT 111.290 0.400 111.430 0.610 ;
        RECT 112.250 0.400 112.390 0.610 ;
        RECT 113.210 0.400 113.350 0.610 ;
        RECT 114.170 0.400 114.310 0.610 ;
        RECT 115.130 0.400 115.270 0.610 ;
        RECT 116.090 0.400 116.230 0.610 ;
        RECT 117.050 0.400 117.190 0.610 ;
        RECT 118.010 0.400 118.150 0.610 ;
        RECT 118.970 0.400 119.110 0.610 ;
        RECT 119.930 0.400 120.070 0.610 ;
        RECT 120.890 0.400 121.030 0.610 ;
        RECT 121.850 0.400 121.990 0.610 ;
        RECT 122.810 0.400 122.950 0.610 ;
        RECT 123.770 0.400 123.910 0.610 ;
        RECT 124.730 0.400 124.870 0.610 ;
        RECT 125.690 0.400 125.830 0.610 ;
        RECT 126.650 0.400 126.790 0.610 ;
        RECT 127.610 0.400 127.750 0.610 ;
        RECT 128.570 0.400 128.710 0.610 ;
        RECT 129.530 0.400 129.670 0.610 ;
        RECT 130.490 0.400 130.630 0.610 ;
        RECT 131.450 0.400 131.590 0.610 ;
        RECT 132.410 0.400 132.550 0.610 ;
        RECT 133.370 0.400 133.510 0.610 ;
        RECT 134.330 0.400 134.470 0.610 ;
        RECT 135.290 0.400 135.430 0.610 ;
        RECT 136.250 0.400 136.390 0.610 ;
        RECT 137.210 0.400 137.350 0.610 ;
        RECT 138.170 0.400 138.310 0.610 ;
        RECT 139.130 0.400 139.270 0.610 ;
        RECT 140.090 0.400 140.230 0.610 ;
        RECT 141.050 0.400 141.190 0.610 ;
        RECT 142.010 0.400 142.150 0.610 ;
        RECT 142.970 0.400 143.110 0.610 ;
        RECT 143.930 0.400 144.070 0.610 ;
        RECT 144.890 0.400 145.030 0.610 ;
        RECT 145.850 0.400 145.990 0.610 ;
        RECT 146.810 0.400 146.950 0.610 ;
        RECT 147.770 0.400 147.910 0.610 ;
        RECT 148.730 0.400 148.870 0.610 ;
        RECT 149.690 0.400 149.830 0.610 ;
        RECT 150.650 0.400 150.790 0.610 ;
        RECT 151.610 0.400 151.750 0.610 ;
        RECT 152.570 0.400 152.710 0.610 ;
        RECT 153.530 0.400 153.670 0.610 ;
        RECT 154.490 0.400 154.630 0.610 ;
        RECT 155.450 0.400 155.590 0.610 ;
        RECT 156.410 0.400 156.550 0.610 ;
        RECT 157.370 0.400 157.510 0.610 ;
        RECT 158.330 0.400 158.470 0.610 ;
        RECT 159.290 0.400 159.430 0.610 ;
        RECT 160.250 0.400 160.390 0.610 ;
        RECT 161.210 0.400 176.265 0.610 ;
      LAYER Metal3 ;
        RECT 0.610 193.210 176.365 193.725 ;
        RECT 0.400 193.190 176.575 193.210 ;
        RECT 0.610 192.370 176.365 193.190 ;
        RECT 0.400 192.350 176.575 192.370 ;
        RECT 0.610 191.530 176.365 192.350 ;
        RECT 0.400 191.510 176.575 191.530 ;
        RECT 0.610 190.690 176.365 191.510 ;
        RECT 0.400 190.670 176.575 190.690 ;
        RECT 0.610 189.850 176.365 190.670 ;
        RECT 0.400 189.830 176.575 189.850 ;
        RECT 0.610 189.010 176.365 189.830 ;
        RECT 0.400 188.990 176.575 189.010 ;
        RECT 0.610 188.170 176.365 188.990 ;
        RECT 0.400 188.150 176.575 188.170 ;
        RECT 0.610 187.330 176.365 188.150 ;
        RECT 0.400 187.310 176.575 187.330 ;
        RECT 0.610 186.490 176.365 187.310 ;
        RECT 0.400 186.470 176.575 186.490 ;
        RECT 0.610 185.650 176.365 186.470 ;
        RECT 0.400 185.630 176.575 185.650 ;
        RECT 0.610 184.810 176.365 185.630 ;
        RECT 0.400 184.790 176.575 184.810 ;
        RECT 0.610 183.970 176.365 184.790 ;
        RECT 0.400 183.950 176.575 183.970 ;
        RECT 0.610 183.130 176.365 183.950 ;
        RECT 0.400 183.110 176.575 183.130 ;
        RECT 0.610 182.290 176.365 183.110 ;
        RECT 0.400 182.270 176.575 182.290 ;
        RECT 0.610 181.450 176.365 182.270 ;
        RECT 0.400 181.430 176.575 181.450 ;
        RECT 0.610 180.610 176.365 181.430 ;
        RECT 0.400 180.590 176.575 180.610 ;
        RECT 0.610 179.770 176.365 180.590 ;
        RECT 0.400 179.750 176.575 179.770 ;
        RECT 0.610 178.930 176.365 179.750 ;
        RECT 0.400 178.910 176.575 178.930 ;
        RECT 0.610 178.090 176.365 178.910 ;
        RECT 0.400 178.070 176.575 178.090 ;
        RECT 0.610 177.250 176.365 178.070 ;
        RECT 0.400 177.230 176.575 177.250 ;
        RECT 0.610 176.410 176.365 177.230 ;
        RECT 0.400 176.390 176.575 176.410 ;
        RECT 0.610 175.570 176.365 176.390 ;
        RECT 0.400 175.550 176.575 175.570 ;
        RECT 0.610 174.730 176.365 175.550 ;
        RECT 0.400 174.710 176.575 174.730 ;
        RECT 0.610 173.890 176.365 174.710 ;
        RECT 0.400 173.870 176.575 173.890 ;
        RECT 0.610 173.050 176.365 173.870 ;
        RECT 0.400 173.030 176.575 173.050 ;
        RECT 0.610 172.210 176.365 173.030 ;
        RECT 0.400 172.190 176.575 172.210 ;
        RECT 0.610 171.370 176.365 172.190 ;
        RECT 0.400 171.350 176.575 171.370 ;
        RECT 0.610 170.530 176.365 171.350 ;
        RECT 0.400 170.510 176.575 170.530 ;
        RECT 0.610 169.690 176.365 170.510 ;
        RECT 0.400 169.670 176.575 169.690 ;
        RECT 0.610 168.850 176.575 169.670 ;
        RECT 0.400 168.830 176.575 168.850 ;
        RECT 0.610 168.010 176.575 168.830 ;
        RECT 0.400 167.990 176.575 168.010 ;
        RECT 0.610 167.170 176.575 167.990 ;
        RECT 0.400 167.150 176.575 167.170 ;
        RECT 0.610 166.330 176.575 167.150 ;
        RECT 0.400 166.310 176.575 166.330 ;
        RECT 0.610 165.490 176.365 166.310 ;
        RECT 0.400 165.470 176.575 165.490 ;
        RECT 0.610 164.650 176.365 165.470 ;
        RECT 0.400 164.630 176.575 164.650 ;
        RECT 0.610 163.810 176.365 164.630 ;
        RECT 0.400 163.790 176.575 163.810 ;
        RECT 0.610 162.970 176.365 163.790 ;
        RECT 0.400 162.950 176.575 162.970 ;
        RECT 0.610 162.130 176.365 162.950 ;
        RECT 0.400 162.110 176.575 162.130 ;
        RECT 0.610 161.290 176.365 162.110 ;
        RECT 0.400 161.270 176.575 161.290 ;
        RECT 0.610 160.450 176.365 161.270 ;
        RECT 0.400 160.430 176.575 160.450 ;
        RECT 0.610 159.610 176.365 160.430 ;
        RECT 0.400 159.590 176.575 159.610 ;
        RECT 0.610 158.770 176.365 159.590 ;
        RECT 0.400 158.750 176.575 158.770 ;
        RECT 0.610 157.930 176.365 158.750 ;
        RECT 0.400 157.910 176.575 157.930 ;
        RECT 0.610 157.090 176.365 157.910 ;
        RECT 0.400 157.070 176.575 157.090 ;
        RECT 0.610 156.250 176.365 157.070 ;
        RECT 0.400 156.230 176.575 156.250 ;
        RECT 0.610 155.410 176.365 156.230 ;
        RECT 0.400 155.390 176.575 155.410 ;
        RECT 0.610 154.570 176.365 155.390 ;
        RECT 0.400 154.550 176.575 154.570 ;
        RECT 0.610 153.730 176.365 154.550 ;
        RECT 0.400 153.710 176.575 153.730 ;
        RECT 0.610 152.890 176.365 153.710 ;
        RECT 0.400 152.870 176.575 152.890 ;
        RECT 0.610 152.050 176.365 152.870 ;
        RECT 0.400 152.030 176.575 152.050 ;
        RECT 0.610 151.210 176.365 152.030 ;
        RECT 0.400 151.190 176.575 151.210 ;
        RECT 0.610 150.370 176.365 151.190 ;
        RECT 0.400 150.350 176.575 150.370 ;
        RECT 0.610 149.530 176.365 150.350 ;
        RECT 0.400 149.510 176.575 149.530 ;
        RECT 0.610 148.690 176.365 149.510 ;
        RECT 0.400 148.670 176.575 148.690 ;
        RECT 0.610 147.850 176.365 148.670 ;
        RECT 0.400 147.830 176.575 147.850 ;
        RECT 0.610 147.010 176.365 147.830 ;
        RECT 0.400 146.990 176.575 147.010 ;
        RECT 0.610 146.170 176.365 146.990 ;
        RECT 0.400 146.150 176.575 146.170 ;
        RECT 0.610 145.330 176.365 146.150 ;
        RECT 0.400 145.310 176.575 145.330 ;
        RECT 0.610 144.490 176.365 145.310 ;
        RECT 0.400 144.470 176.575 144.490 ;
        RECT 0.610 143.650 176.365 144.470 ;
        RECT 0.400 143.630 176.575 143.650 ;
        RECT 0.610 142.810 176.365 143.630 ;
        RECT 0.400 142.790 176.575 142.810 ;
        RECT 0.610 141.970 176.365 142.790 ;
        RECT 0.400 141.950 176.575 141.970 ;
        RECT 0.610 141.130 176.365 141.950 ;
        RECT 0.400 141.110 176.575 141.130 ;
        RECT 0.610 140.290 176.365 141.110 ;
        RECT 0.400 140.270 176.575 140.290 ;
        RECT 0.610 139.450 176.365 140.270 ;
        RECT 0.400 139.430 176.575 139.450 ;
        RECT 0.610 138.610 176.365 139.430 ;
        RECT 0.400 138.590 176.575 138.610 ;
        RECT 0.610 137.770 176.365 138.590 ;
        RECT 0.400 137.750 176.575 137.770 ;
        RECT 0.610 136.930 176.365 137.750 ;
        RECT 0.400 136.910 176.575 136.930 ;
        RECT 0.610 136.090 176.365 136.910 ;
        RECT 0.400 136.070 176.575 136.090 ;
        RECT 0.610 135.250 176.365 136.070 ;
        RECT 0.400 135.230 176.575 135.250 ;
        RECT 0.610 134.410 176.365 135.230 ;
        RECT 0.400 134.390 176.575 134.410 ;
        RECT 0.610 133.570 176.365 134.390 ;
        RECT 0.400 133.550 176.575 133.570 ;
        RECT 0.610 132.730 176.365 133.550 ;
        RECT 0.400 132.710 176.575 132.730 ;
        RECT 0.610 131.890 176.365 132.710 ;
        RECT 0.400 131.870 176.575 131.890 ;
        RECT 0.610 131.050 176.365 131.870 ;
        RECT 0.400 131.030 176.575 131.050 ;
        RECT 0.610 130.210 176.365 131.030 ;
        RECT 0.400 130.190 176.575 130.210 ;
        RECT 0.610 129.370 176.365 130.190 ;
        RECT 0.400 129.350 176.575 129.370 ;
        RECT 0.610 128.530 176.365 129.350 ;
        RECT 0.400 128.510 176.575 128.530 ;
        RECT 0.610 127.690 176.365 128.510 ;
        RECT 0.400 127.670 176.575 127.690 ;
        RECT 0.610 126.850 176.365 127.670 ;
        RECT 0.400 126.830 176.575 126.850 ;
        RECT 0.610 126.010 176.365 126.830 ;
        RECT 0.400 125.990 176.575 126.010 ;
        RECT 0.610 125.170 176.365 125.990 ;
        RECT 0.400 125.150 176.575 125.170 ;
        RECT 0.610 124.330 176.365 125.150 ;
        RECT 0.400 124.310 176.575 124.330 ;
        RECT 0.610 123.490 176.365 124.310 ;
        RECT 0.400 123.470 176.575 123.490 ;
        RECT 0.610 122.650 176.365 123.470 ;
        RECT 0.400 122.630 176.575 122.650 ;
        RECT 0.610 121.810 176.365 122.630 ;
        RECT 0.400 121.790 176.575 121.810 ;
        RECT 0.610 120.970 176.365 121.790 ;
        RECT 0.400 120.950 176.575 120.970 ;
        RECT 0.610 120.130 176.365 120.950 ;
        RECT 0.400 120.110 176.575 120.130 ;
        RECT 0.610 119.290 176.365 120.110 ;
        RECT 0.400 119.270 176.575 119.290 ;
        RECT 0.610 118.450 176.365 119.270 ;
        RECT 0.400 118.430 176.575 118.450 ;
        RECT 0.610 117.610 176.365 118.430 ;
        RECT 0.400 117.590 176.575 117.610 ;
        RECT 0.610 116.770 176.365 117.590 ;
        RECT 0.400 116.750 176.575 116.770 ;
        RECT 0.610 115.930 176.365 116.750 ;
        RECT 0.400 115.910 176.575 115.930 ;
        RECT 0.610 115.090 176.365 115.910 ;
        RECT 0.400 115.070 176.575 115.090 ;
        RECT 0.610 114.250 176.365 115.070 ;
        RECT 0.400 114.230 176.575 114.250 ;
        RECT 0.610 113.410 176.365 114.230 ;
        RECT 0.400 113.390 176.575 113.410 ;
        RECT 0.610 112.570 176.365 113.390 ;
        RECT 0.400 112.550 176.575 112.570 ;
        RECT 0.610 111.730 176.365 112.550 ;
        RECT 0.400 111.710 176.575 111.730 ;
        RECT 0.610 110.890 176.365 111.710 ;
        RECT 0.400 110.870 176.575 110.890 ;
        RECT 0.610 110.050 176.365 110.870 ;
        RECT 0.400 110.030 176.575 110.050 ;
        RECT 0.610 109.210 176.365 110.030 ;
        RECT 0.400 109.190 176.575 109.210 ;
        RECT 0.610 108.370 176.365 109.190 ;
        RECT 0.400 108.350 176.575 108.370 ;
        RECT 0.610 107.530 176.365 108.350 ;
        RECT 0.400 107.510 176.575 107.530 ;
        RECT 0.610 106.690 176.365 107.510 ;
        RECT 0.400 106.670 176.575 106.690 ;
        RECT 0.610 105.850 176.365 106.670 ;
        RECT 0.400 105.830 176.575 105.850 ;
        RECT 0.610 105.010 176.365 105.830 ;
        RECT 0.400 104.990 176.575 105.010 ;
        RECT 0.610 104.170 176.365 104.990 ;
        RECT 0.400 104.150 176.575 104.170 ;
        RECT 0.610 103.330 176.365 104.150 ;
        RECT 0.400 103.310 176.575 103.330 ;
        RECT 0.610 102.490 176.365 103.310 ;
        RECT 0.400 102.470 176.575 102.490 ;
        RECT 0.610 101.650 176.365 102.470 ;
        RECT 0.400 101.630 176.575 101.650 ;
        RECT 0.610 100.810 176.365 101.630 ;
        RECT 0.400 100.790 176.575 100.810 ;
        RECT 0.610 99.970 176.365 100.790 ;
        RECT 0.400 99.950 176.575 99.970 ;
        RECT 0.610 99.130 176.365 99.950 ;
        RECT 0.400 99.110 176.575 99.130 ;
        RECT 0.610 98.290 176.365 99.110 ;
        RECT 0.400 98.270 176.575 98.290 ;
        RECT 0.610 97.450 176.365 98.270 ;
        RECT 0.400 97.430 176.575 97.450 ;
        RECT 0.610 96.610 176.365 97.430 ;
        RECT 0.400 96.590 176.575 96.610 ;
        RECT 0.610 95.770 176.365 96.590 ;
        RECT 0.400 95.750 176.575 95.770 ;
        RECT 0.610 94.930 176.365 95.750 ;
        RECT 0.400 94.910 176.575 94.930 ;
        RECT 0.610 94.090 176.365 94.910 ;
        RECT 0.400 94.070 176.575 94.090 ;
        RECT 0.610 93.250 176.365 94.070 ;
        RECT 0.400 93.230 176.575 93.250 ;
        RECT 0.610 92.410 176.365 93.230 ;
        RECT 0.400 92.390 176.575 92.410 ;
        RECT 0.610 91.570 176.365 92.390 ;
        RECT 0.400 91.550 176.575 91.570 ;
        RECT 0.610 90.730 176.365 91.550 ;
        RECT 0.400 90.710 176.575 90.730 ;
        RECT 0.610 89.890 176.365 90.710 ;
        RECT 0.400 89.870 176.575 89.890 ;
        RECT 0.610 89.050 176.365 89.870 ;
        RECT 0.400 89.030 176.575 89.050 ;
        RECT 0.610 88.210 176.365 89.030 ;
        RECT 0.400 88.190 176.575 88.210 ;
        RECT 0.610 87.370 176.365 88.190 ;
        RECT 0.400 87.350 176.575 87.370 ;
        RECT 0.610 86.530 176.365 87.350 ;
        RECT 0.400 86.510 176.575 86.530 ;
        RECT 0.610 85.690 176.365 86.510 ;
        RECT 0.400 85.670 176.575 85.690 ;
        RECT 0.610 84.850 176.365 85.670 ;
        RECT 0.400 84.830 176.575 84.850 ;
        RECT 0.610 84.010 176.365 84.830 ;
        RECT 0.400 83.990 176.575 84.010 ;
        RECT 0.610 83.170 176.365 83.990 ;
        RECT 0.400 83.150 176.575 83.170 ;
        RECT 0.610 82.330 176.365 83.150 ;
        RECT 0.400 82.310 176.575 82.330 ;
        RECT 0.610 81.490 176.365 82.310 ;
        RECT 0.400 81.470 176.575 81.490 ;
        RECT 0.610 80.650 176.365 81.470 ;
        RECT 0.400 80.630 176.575 80.650 ;
        RECT 0.610 79.810 176.365 80.630 ;
        RECT 0.400 79.790 176.575 79.810 ;
        RECT 0.610 78.970 176.365 79.790 ;
        RECT 0.400 78.950 176.575 78.970 ;
        RECT 0.610 78.130 176.365 78.950 ;
        RECT 0.400 78.110 176.575 78.130 ;
        RECT 0.610 77.290 176.365 78.110 ;
        RECT 0.400 77.270 176.575 77.290 ;
        RECT 0.610 76.450 176.365 77.270 ;
        RECT 0.400 76.430 176.575 76.450 ;
        RECT 0.610 75.610 176.365 76.430 ;
        RECT 0.400 75.590 176.575 75.610 ;
        RECT 0.610 74.770 176.365 75.590 ;
        RECT 0.400 74.750 176.575 74.770 ;
        RECT 0.610 73.930 176.365 74.750 ;
        RECT 0.400 73.910 176.575 73.930 ;
        RECT 0.610 73.090 176.365 73.910 ;
        RECT 0.400 73.070 176.575 73.090 ;
        RECT 0.610 72.250 176.365 73.070 ;
        RECT 0.400 72.230 176.575 72.250 ;
        RECT 0.610 71.410 176.365 72.230 ;
        RECT 0.400 71.390 176.575 71.410 ;
        RECT 0.610 70.570 176.365 71.390 ;
        RECT 0.400 70.550 176.575 70.570 ;
        RECT 0.610 69.730 176.365 70.550 ;
        RECT 0.400 69.710 176.575 69.730 ;
        RECT 0.610 68.890 176.365 69.710 ;
        RECT 0.400 68.870 176.575 68.890 ;
        RECT 0.610 68.050 176.365 68.870 ;
        RECT 0.400 68.030 176.575 68.050 ;
        RECT 0.610 67.210 176.365 68.030 ;
        RECT 0.400 67.190 176.575 67.210 ;
        RECT 0.610 66.370 176.365 67.190 ;
        RECT 0.400 66.350 176.575 66.370 ;
        RECT 0.610 65.530 176.365 66.350 ;
        RECT 0.400 65.510 176.575 65.530 ;
        RECT 0.610 64.690 176.365 65.510 ;
        RECT 0.400 64.670 176.575 64.690 ;
        RECT 0.610 63.850 176.365 64.670 ;
        RECT 0.400 63.830 176.575 63.850 ;
        RECT 0.610 63.010 176.365 63.830 ;
        RECT 0.400 62.990 176.575 63.010 ;
        RECT 0.610 62.170 176.365 62.990 ;
        RECT 0.400 62.150 176.575 62.170 ;
        RECT 0.610 61.330 176.365 62.150 ;
        RECT 0.400 61.310 176.575 61.330 ;
        RECT 0.610 60.490 176.365 61.310 ;
        RECT 0.400 60.470 176.575 60.490 ;
        RECT 0.610 59.650 176.365 60.470 ;
        RECT 0.400 59.630 176.575 59.650 ;
        RECT 0.610 58.810 176.365 59.630 ;
        RECT 0.400 58.790 176.575 58.810 ;
        RECT 0.610 57.970 176.365 58.790 ;
        RECT 0.400 57.950 176.575 57.970 ;
        RECT 0.610 57.130 176.365 57.950 ;
        RECT 0.400 57.110 176.575 57.130 ;
        RECT 0.610 56.290 176.365 57.110 ;
        RECT 0.400 56.270 176.575 56.290 ;
        RECT 0.610 55.450 176.365 56.270 ;
        RECT 0.400 55.430 176.575 55.450 ;
        RECT 0.610 54.610 176.365 55.430 ;
        RECT 0.400 54.590 176.575 54.610 ;
        RECT 0.610 53.770 176.365 54.590 ;
        RECT 0.400 53.750 176.575 53.770 ;
        RECT 0.610 52.930 176.365 53.750 ;
        RECT 0.400 52.910 176.575 52.930 ;
        RECT 0.610 52.090 176.365 52.910 ;
        RECT 0.400 52.070 176.575 52.090 ;
        RECT 0.610 51.250 176.365 52.070 ;
        RECT 0.400 51.230 176.575 51.250 ;
        RECT 0.610 50.410 176.365 51.230 ;
        RECT 0.400 50.390 176.575 50.410 ;
        RECT 0.610 49.570 176.365 50.390 ;
        RECT 0.400 49.550 176.575 49.570 ;
        RECT 0.610 48.730 176.365 49.550 ;
        RECT 0.400 48.710 176.575 48.730 ;
        RECT 0.610 47.890 176.365 48.710 ;
        RECT 0.400 47.870 176.575 47.890 ;
        RECT 0.610 47.050 176.365 47.870 ;
        RECT 0.400 47.030 176.575 47.050 ;
        RECT 0.610 46.210 176.365 47.030 ;
        RECT 0.400 46.190 176.575 46.210 ;
        RECT 0.610 45.370 176.365 46.190 ;
        RECT 0.400 45.350 176.575 45.370 ;
        RECT 0.610 44.530 176.365 45.350 ;
        RECT 0.400 44.510 176.575 44.530 ;
        RECT 0.610 43.690 176.365 44.510 ;
        RECT 0.400 43.670 176.575 43.690 ;
        RECT 0.610 42.850 176.365 43.670 ;
        RECT 0.400 42.830 176.575 42.850 ;
        RECT 0.610 42.010 176.365 42.830 ;
        RECT 0.400 41.990 176.575 42.010 ;
        RECT 0.610 41.170 176.365 41.990 ;
        RECT 0.400 41.150 176.575 41.170 ;
        RECT 0.610 40.330 176.365 41.150 ;
        RECT 0.400 40.310 176.575 40.330 ;
        RECT 0.610 39.490 176.365 40.310 ;
        RECT 0.400 39.470 176.575 39.490 ;
        RECT 0.610 38.650 176.365 39.470 ;
        RECT 0.400 38.630 176.575 38.650 ;
        RECT 0.610 37.810 176.365 38.630 ;
        RECT 0.400 37.790 176.575 37.810 ;
        RECT 0.610 36.970 176.365 37.790 ;
        RECT 0.400 36.950 176.575 36.970 ;
        RECT 0.610 36.130 176.365 36.950 ;
        RECT 0.400 36.110 176.575 36.130 ;
        RECT 0.610 35.290 176.365 36.110 ;
        RECT 0.400 35.270 176.575 35.290 ;
        RECT 0.610 34.450 176.365 35.270 ;
        RECT 0.400 34.430 176.575 34.450 ;
        RECT 0.610 33.610 176.365 34.430 ;
        RECT 0.400 33.590 176.575 33.610 ;
        RECT 0.610 32.770 176.365 33.590 ;
        RECT 0.400 32.750 176.575 32.770 ;
        RECT 0.610 31.930 176.365 32.750 ;
        RECT 0.400 31.910 176.575 31.930 ;
        RECT 0.610 31.090 176.365 31.910 ;
        RECT 0.400 31.070 176.575 31.090 ;
        RECT 0.610 30.250 176.365 31.070 ;
        RECT 0.400 30.230 176.575 30.250 ;
        RECT 0.610 29.410 176.365 30.230 ;
        RECT 0.400 29.390 176.575 29.410 ;
        RECT 0.610 28.570 176.365 29.390 ;
        RECT 0.400 28.550 176.575 28.570 ;
        RECT 0.610 27.730 176.365 28.550 ;
        RECT 0.400 27.710 176.575 27.730 ;
        RECT 0.610 26.890 176.365 27.710 ;
        RECT 0.400 26.870 176.575 26.890 ;
        RECT 0.610 26.050 176.365 26.870 ;
        RECT 0.400 26.030 176.575 26.050 ;
        RECT 0.610 25.210 176.365 26.030 ;
        RECT 0.400 25.190 176.575 25.210 ;
        RECT 0.610 24.370 176.365 25.190 ;
        RECT 0.400 24.350 176.575 24.370 ;
        RECT 0.610 23.530 176.365 24.350 ;
        RECT 0.400 23.510 176.575 23.530 ;
        RECT 0.610 22.690 176.365 23.510 ;
        RECT 0.400 22.670 176.575 22.690 ;
        RECT 0.610 21.850 176.365 22.670 ;
        RECT 0.400 21.830 176.575 21.850 ;
        RECT 0.610 21.010 176.365 21.830 ;
        RECT 0.400 20.990 176.575 21.010 ;
        RECT 0.610 20.170 176.365 20.990 ;
        RECT 0.400 20.150 176.575 20.170 ;
        RECT 0.610 19.330 176.365 20.150 ;
        RECT 0.400 19.310 176.575 19.330 ;
        RECT 0.610 18.490 176.365 19.310 ;
        RECT 0.400 18.470 176.575 18.490 ;
        RECT 0.610 17.650 176.365 18.470 ;
        RECT 0.400 17.630 176.575 17.650 ;
        RECT 0.610 16.810 176.365 17.630 ;
        RECT 0.400 16.790 176.575 16.810 ;
        RECT 0.610 15.970 176.365 16.790 ;
        RECT 0.400 15.950 176.575 15.970 ;
        RECT 0.610 15.130 176.365 15.950 ;
        RECT 0.400 15.110 176.575 15.130 ;
        RECT 0.610 14.290 176.365 15.110 ;
        RECT 0.400 14.270 176.575 14.290 ;
        RECT 0.610 13.450 176.365 14.270 ;
        RECT 0.400 13.430 176.575 13.450 ;
        RECT 0.610 12.610 176.365 13.430 ;
        RECT 0.400 12.590 176.575 12.610 ;
        RECT 0.610 11.770 176.365 12.590 ;
        RECT 0.400 11.750 176.575 11.770 ;
        RECT 0.610 10.930 176.365 11.750 ;
        RECT 0.400 10.910 176.575 10.930 ;
        RECT 0.610 10.090 176.365 10.910 ;
        RECT 0.400 10.070 176.575 10.090 ;
        RECT 0.610 9.250 176.365 10.070 ;
        RECT 0.400 9.230 176.575 9.250 ;
        RECT 0.610 8.410 176.365 9.230 ;
        RECT 0.400 8.390 176.575 8.410 ;
        RECT 0.610 7.570 176.365 8.390 ;
        RECT 0.400 7.550 176.575 7.570 ;
        RECT 0.610 6.730 176.365 7.550 ;
        RECT 0.400 6.710 176.575 6.730 ;
        RECT 0.610 5.890 176.575 6.710 ;
        RECT 0.400 5.870 176.575 5.890 ;
        RECT 0.610 5.050 176.575 5.870 ;
        RECT 0.400 5.030 176.575 5.050 ;
        RECT 0.610 4.210 176.575 5.030 ;
        RECT 0.400 4.190 176.575 4.210 ;
        RECT 0.610 3.370 176.575 4.190 ;
        RECT 0.400 3.350 176.575 3.370 ;
        RECT 0.610 2.530 176.575 3.350 ;
        RECT 0.400 2.510 176.575 2.530 ;
        RECT 0.610 1.690 176.575 2.510 ;
        RECT 0.400 0.735 176.575 1.690 ;
      LAYER Metal4 ;
        RECT 0.375 0.695 172.420 193.765 ;
      LAYER Metal5 ;
        RECT 0.335 1.580 171.525 189.730 ;
      LAYER TopMetal1 ;
        RECT 0.820 179.930 163.180 190.240 ;
        RECT 0.820 102.920 16.620 179.930 ;
        RECT 22.100 179.520 92.220 179.930 ;
        RECT 22.100 102.920 22.820 179.520 ;
        RECT 28.300 102.920 92.220 179.520 ;
        RECT 97.700 179.520 163.180 179.930 ;
        RECT 97.700 102.920 98.420 179.520 ;
        RECT 103.900 102.920 163.180 179.520 ;
  END
END interconnect_macro
END LIBRARY

